VERSION 5.8 ;
BUSBITCHARS "[]" ;
DIVIDERCHAR "/" ;
UNITS
    DATABASE MICRONS 1000 ;
END UNITS

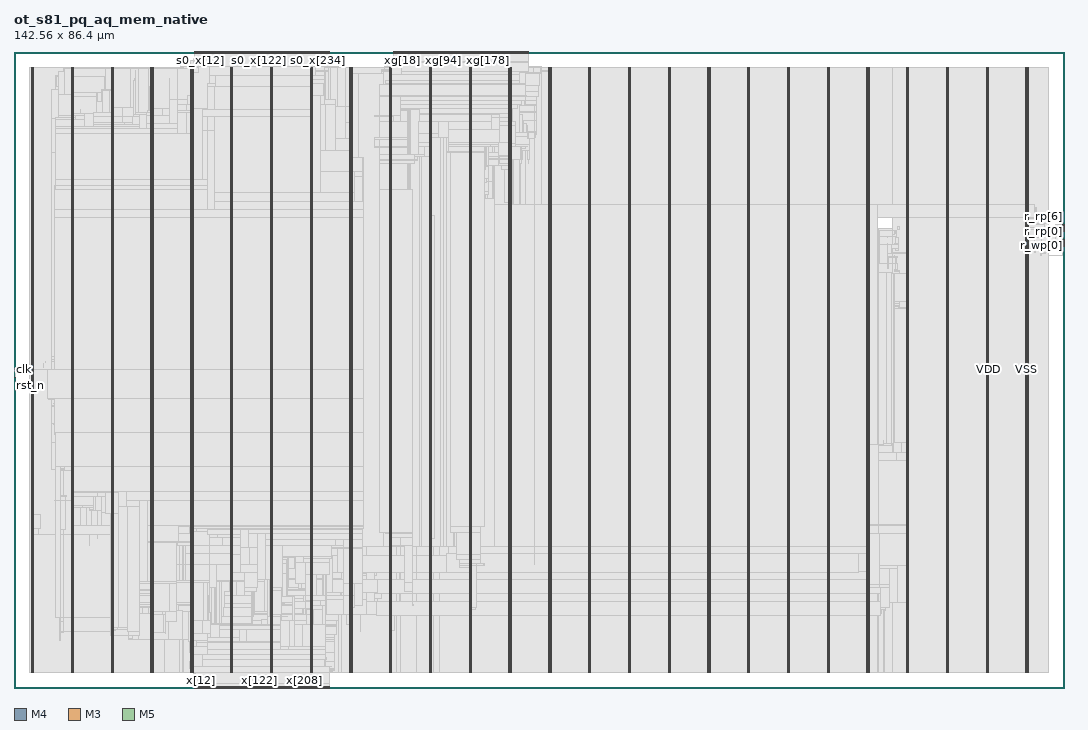
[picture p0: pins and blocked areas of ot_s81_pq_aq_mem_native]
MACRO ot_s81_pq_aq_mem_native
  FOREIGN ot_s81_pq_aq_mem_native 0 0 ;
  CLASS BLOCK ;
  SIZE 142.56 BY 86.4 ;
  PIN clk
    DIRECTION INPUT ;
    USE SIGNAL ;
    PORT
      LAYER M4 ;
        RECT  0 43.2 0.192 43.224 ;
    END
    PORT
      LAYER M4 ;
        RECT  0.156 43.2 0.205 43.224 ;
    END
  END clk
  PIN r_rp[0]
    DIRECTION OUTPUT ;
    USE SIGNAL ;
    PORT
      LAYER M4 ;
        RECT  142.368 62.016 142.56 62.04 ;
    END
  END r_rp[0]
  PIN r_rp[1]
    DIRECTION OUTPUT ;
    USE SIGNAL ;
    PORT
      LAYER M4 ;
        RECT  142.368 62.16 142.56 62.184 ;
    END
  END r_rp[1]
  PIN r_rp[2]
    DIRECTION OUTPUT ;
    USE SIGNAL ;
    PORT
      LAYER M4 ;
        RECT  142.368 62.304 142.56 62.328 ;
    END
  END r_rp[2]
  PIN r_rp[3]
    DIRECTION OUTPUT ;
    USE SIGNAL ;
    PORT
      LAYER M4 ;
        RECT  142.368 62.448 142.56 62.472 ;
    END
  END r_rp[3]
  PIN r_rp[4]
    DIRECTION OUTPUT ;
    USE SIGNAL ;
    PORT
      LAYER M4 ;
        RECT  142.368 62.592 142.56 62.616 ;
    END
  END r_rp[4]
  PIN r_rp[5]
    DIRECTION OUTPUT ;
    USE SIGNAL ;
    PORT
      LAYER M4 ;
        RECT  142.368 62.736 142.56 62.76 ;
    END
  END r_rp[5]
  PIN r_rp[6]
    DIRECTION OUTPUT ;
    USE SIGNAL ;
    PORT
      LAYER M4 ;
        RECT  142.368 62.88 142.56 62.904 ;
    END
  END r_rp[6]
  PIN r_wp[0]
    DIRECTION OUTPUT ;
    USE SIGNAL ;
    PORT
      LAYER M4 ;
        RECT  142.368 60 142.56 60.024 ;
    END
  END r_wp[0]
  PIN r_wp[1]
    DIRECTION OUTPUT ;
    USE SIGNAL ;
    PORT
      LAYER M4 ;
        RECT  142.368 60.144 142.56 60.168 ;
    END
  END r_wp[1]
  PIN r_wp[2]
    DIRECTION OUTPUT ;
    USE SIGNAL ;
    PORT
      LAYER M4 ;
        RECT  142.368 60.288 142.56 60.312 ;
    END
  END r_wp[2]
  PIN r_wp[3]
    DIRECTION OUTPUT ;
    USE SIGNAL ;
    PORT
      LAYER M4 ;
        RECT  142.368 60.432 142.56 60.456 ;
    END
  END r_wp[3]
  PIN r_wp[4]
    DIRECTION OUTPUT ;
    USE SIGNAL ;
    PORT
      LAYER M4 ;
        RECT  142.368 60.576 142.56 60.6 ;
    END
  END r_wp[4]
  PIN r_wp[5]
    DIRECTION OUTPUT ;
    USE SIGNAL ;
    PORT
      LAYER M4 ;
        RECT  142.368 60.72 142.56 60.744 ;
    END
  END r_wp[5]
  PIN r_wp[6]
    DIRECTION OUTPUT ;
    USE SIGNAL ;
    PORT
      LAYER M4 ;
        RECT  142.368 60.864 142.56 60.888 ;
    END
  END r_wp[6]
  PIN rst_n
    DIRECTION INPUT ;
    USE SIGNAL ;
    PORT
      LAYER M4 ;
        RECT  0 42.192 0.192 42.216 ;
    END
    PORT
      LAYER M4 ;
        RECT  0.156 42.192 0.245 42.216 ;
    END
  END rst_n
  PIN s0_x[0]
    DIRECTION OUTPUT ;
    USE SIGNAL ;
    PORT
      LAYER M3 ;
        RECT  24.48 86.256 24.498 86.4 ;
    END
  END s0_x[0]
  PIN s0_x[100]
    DIRECTION OUTPUT ;
    USE SIGNAL ;
    PORT
      LAYER M3 ;
        RECT  31.68 86.256 31.698 86.4 ;
    END
  END s0_x[100]
  PIN s0_x[101]
    DIRECTION OUTPUT ;
    USE SIGNAL ;
    PORT
      LAYER M5 ;
        RECT  31.728 86.208 31.752 86.4 ;
    END
  END s0_x[101]
  PIN s0_x[102]
    DIRECTION OUTPUT ;
    USE SIGNAL ;
    PORT
      LAYER M3 ;
        RECT  31.824 86.256 31.842 86.4 ;
    END
  END s0_x[102]
  PIN s0_x[103]
    DIRECTION OUTPUT ;
    USE SIGNAL ;
    PORT
      LAYER M5 ;
        RECT  31.872 86.208 31.896 86.4 ;
    END
  END s0_x[103]
  PIN s0_x[104]
    DIRECTION OUTPUT ;
    USE SIGNAL ;
    PORT
      LAYER M3 ;
        RECT  31.968 86.256 31.986 86.4 ;
    END
  END s0_x[104]
  PIN s0_x[105]
    DIRECTION OUTPUT ;
    USE SIGNAL ;
    PORT
      LAYER M5 ;
        RECT  32.016 86.208 32.04 86.4 ;
    END
  END s0_x[105]
  PIN s0_x[106]
    DIRECTION OUTPUT ;
    USE SIGNAL ;
    PORT
      LAYER M3 ;
        RECT  32.112 86.256 32.13 86.4 ;
    END
  END s0_x[106]
  PIN s0_x[107]
    DIRECTION OUTPUT ;
    USE SIGNAL ;
    PORT
      LAYER M5 ;
        RECT  32.16 86.208 32.184 86.4 ;
    END
  END s0_x[107]
  PIN s0_x[108]
    DIRECTION OUTPUT ;
    USE SIGNAL ;
    PORT
      LAYER M3 ;
        RECT  32.256 86.256 32.274 86.4 ;
    END
  END s0_x[108]
  PIN s0_x[109]
    DIRECTION OUTPUT ;
    USE SIGNAL ;
    PORT
      LAYER M5 ;
        RECT  32.304 86.208 32.328 86.4 ;
    END
  END s0_x[109]
  PIN s0_x[10]
    DIRECTION OUTPUT ;
    USE SIGNAL ;
    PORT
      LAYER M3 ;
        RECT  25.2 86.256 25.218 86.4 ;
    END
  END s0_x[10]
  PIN s0_x[110]
    DIRECTION OUTPUT ;
    USE SIGNAL ;
    PORT
      LAYER M3 ;
        RECT  32.4 86.256 32.418 86.4 ;
    END
  END s0_x[110]
  PIN s0_x[111]
    DIRECTION OUTPUT ;
    USE SIGNAL ;
    PORT
      LAYER M5 ;
        RECT  32.448 86.208 32.472 86.4 ;
    END
  END s0_x[111]
  PIN s0_x[112]
    DIRECTION OUTPUT ;
    USE SIGNAL ;
    PORT
      LAYER M3 ;
        RECT  32.544 86.256 32.562 86.4 ;
    END
  END s0_x[112]
  PIN s0_x[113]
    DIRECTION OUTPUT ;
    USE SIGNAL ;
    PORT
      LAYER M5 ;
        RECT  32.592 86.208 32.616 86.4 ;
    END
  END s0_x[113]
  PIN s0_x[114]
    DIRECTION OUTPUT ;
    USE SIGNAL ;
    PORT
      LAYER M3 ;
        RECT  32.688 86.256 32.706 86.4 ;
    END
  END s0_x[114]
  PIN s0_x[115]
    DIRECTION OUTPUT ;
    USE SIGNAL ;
    PORT
      LAYER M5 ;
        RECT  32.736 86.208 32.76 86.4 ;
    END
  END s0_x[115]
  PIN s0_x[116]
    DIRECTION OUTPUT ;
    USE SIGNAL ;
    PORT
      LAYER M3 ;
        RECT  32.832 86.256 32.85 86.4 ;
    END
  END s0_x[116]
  PIN s0_x[117]
    DIRECTION OUTPUT ;
    USE SIGNAL ;
    PORT
      LAYER M5 ;
        RECT  32.88 86.208 32.904 86.4 ;
    END
  END s0_x[117]
  PIN s0_x[118]
    DIRECTION OUTPUT ;
    USE SIGNAL ;
    PORT
      LAYER M3 ;
        RECT  32.976 86.256 32.994 86.4 ;
    END
  END s0_x[118]
  PIN s0_x[119]
    DIRECTION OUTPUT ;
    USE SIGNAL ;
    PORT
      LAYER M5 ;
        RECT  33.024 86.208 33.048 86.4 ;
    END
  END s0_x[119]
  PIN s0_x[11]
    DIRECTION OUTPUT ;
    USE SIGNAL ;
    PORT
      LAYER M5 ;
        RECT  25.248 86.208 25.272 86.4 ;
    END
  END s0_x[11]
  PIN s0_x[120]
    DIRECTION OUTPUT ;
    USE SIGNAL ;
    PORT
      LAYER M3 ;
        RECT  33.12 86.256 33.138 86.4 ;
    END
  END s0_x[120]
  PIN s0_x[121]
    DIRECTION OUTPUT ;
    USE SIGNAL ;
    PORT
      LAYER M5 ;
        RECT  33.168 86.208 33.192 86.4 ;
    END
  END s0_x[121]
  PIN s0_x[122]
    DIRECTION OUTPUT ;
    USE SIGNAL ;
    PORT
      LAYER M3 ;
        RECT  33.264 86.256 33.282 86.4 ;
    END
  END s0_x[122]
  PIN s0_x[123]
    DIRECTION OUTPUT ;
    USE SIGNAL ;
    PORT
      LAYER M5 ;
        RECT  33.312 86.208 33.336 86.4 ;
    END
  END s0_x[123]
  PIN s0_x[124]
    DIRECTION OUTPUT ;
    USE SIGNAL ;
    PORT
      LAYER M3 ;
        RECT  33.408 86.256 33.426 86.4 ;
    END
  END s0_x[124]
  PIN s0_x[125]
    DIRECTION OUTPUT ;
    USE SIGNAL ;
    PORT
      LAYER M5 ;
        RECT  33.456 86.208 33.48 86.4 ;
    END
  END s0_x[125]
  PIN s0_x[126]
    DIRECTION OUTPUT ;
    USE SIGNAL ;
    PORT
      LAYER M3 ;
        RECT  33.552 86.256 33.57 86.4 ;
    END
  END s0_x[126]
  PIN s0_x[127]
    DIRECTION OUTPUT ;
    USE SIGNAL ;
    PORT
      LAYER M5 ;
        RECT  33.6 86.208 33.624 86.4 ;
    END
  END s0_x[127]
  PIN s0_x[128]
    DIRECTION OUTPUT ;
    USE SIGNAL ;
    PORT
      LAYER M3 ;
        RECT  33.696 86.256 33.714 86.4 ;
    END
  END s0_x[128]
  PIN s0_x[129]
    DIRECTION OUTPUT ;
    USE SIGNAL ;
    PORT
      LAYER M5 ;
        RECT  33.744 86.208 33.768 86.4 ;
    END
  END s0_x[129]
  PIN s0_x[12]
    DIRECTION OUTPUT ;
    USE SIGNAL ;
    PORT
      LAYER M3 ;
        RECT  25.344 86.256 25.362 86.4 ;
    END
  END s0_x[12]
  PIN s0_x[130]
    DIRECTION OUTPUT ;
    USE SIGNAL ;
    PORT
      LAYER M3 ;
        RECT  33.84 86.256 33.858 86.4 ;
    END
  END s0_x[130]
  PIN s0_x[131]
    DIRECTION OUTPUT ;
    USE SIGNAL ;
    PORT
      LAYER M5 ;
        RECT  33.888 86.208 33.912 86.4 ;
    END
  END s0_x[131]
  PIN s0_x[132]
    DIRECTION OUTPUT ;
    USE SIGNAL ;
    PORT
      LAYER M3 ;
        RECT  33.984 86.256 34.002 86.4 ;
    END
  END s0_x[132]
  PIN s0_x[133]
    DIRECTION OUTPUT ;
    USE SIGNAL ;
    PORT
      LAYER M5 ;
        RECT  34.032 86.208 34.056 86.4 ;
    END
  END s0_x[133]
  PIN s0_x[134]
    DIRECTION OUTPUT ;
    USE SIGNAL ;
    PORT
      LAYER M3 ;
        RECT  34.128 86.256 34.146 86.4 ;
    END
  END s0_x[134]
  PIN s0_x[135]
    DIRECTION OUTPUT ;
    USE SIGNAL ;
    PORT
      LAYER M5 ;
        RECT  34.176 86.208 34.2 86.4 ;
    END
  END s0_x[135]
  PIN s0_x[136]
    DIRECTION OUTPUT ;
    USE SIGNAL ;
    PORT
      LAYER M3 ;
        RECT  34.272 86.256 34.29 86.4 ;
    END
  END s0_x[136]
  PIN s0_x[137]
    DIRECTION OUTPUT ;
    USE SIGNAL ;
    PORT
      LAYER M5 ;
        RECT  34.32 86.208 34.344 86.4 ;
    END
  END s0_x[137]
  PIN s0_x[138]
    DIRECTION OUTPUT ;
    USE SIGNAL ;
    PORT
      LAYER M3 ;
        RECT  34.416 86.256 34.434 86.4 ;
    END
  END s0_x[138]
  PIN s0_x[139]
    DIRECTION OUTPUT ;
    USE SIGNAL ;
    PORT
      LAYER M5 ;
        RECT  34.464 86.208 34.488 86.4 ;
    END
  END s0_x[139]
  PIN s0_x[13]
    DIRECTION OUTPUT ;
    USE SIGNAL ;
    PORT
      LAYER M5 ;
        RECT  25.392 86.208 25.416 86.4 ;
    END
  END s0_x[13]
  PIN s0_x[140]
    DIRECTION OUTPUT ;
    USE SIGNAL ;
    PORT
      LAYER M3 ;
        RECT  34.56 86.256 34.578 86.4 ;
    END
  END s0_x[140]
  PIN s0_x[141]
    DIRECTION OUTPUT ;
    USE SIGNAL ;
    PORT
      LAYER M5 ;
        RECT  34.608 86.208 34.632 86.4 ;
    END
  END s0_x[141]
  PIN s0_x[142]
    DIRECTION OUTPUT ;
    USE SIGNAL ;
    PORT
      LAYER M3 ;
        RECT  34.704 86.256 34.722 86.4 ;
    END
  END s0_x[142]
  PIN s0_x[143]
    DIRECTION OUTPUT ;
    USE SIGNAL ;
    PORT
      LAYER M5 ;
        RECT  34.752 86.208 34.776 86.4 ;
    END
  END s0_x[143]
  PIN s0_x[144]
    DIRECTION OUTPUT ;
    USE SIGNAL ;
    PORT
      LAYER M3 ;
        RECT  34.848 86.256 34.866 86.4 ;
    END
  END s0_x[144]
  PIN s0_x[145]
    DIRECTION OUTPUT ;
    USE SIGNAL ;
    PORT
      LAYER M5 ;
        RECT  34.896 86.208 34.92 86.4 ;
    END
  END s0_x[145]
  PIN s0_x[146]
    DIRECTION OUTPUT ;
    USE SIGNAL ;
    PORT
      LAYER M3 ;
        RECT  34.992 86.256 35.01 86.4 ;
    END
  END s0_x[146]
  PIN s0_x[147]
    DIRECTION OUTPUT ;
    USE SIGNAL ;
    PORT
      LAYER M5 ;
        RECT  35.04 86.208 35.064 86.4 ;
    END
  END s0_x[147]
  PIN s0_x[148]
    DIRECTION OUTPUT ;
    USE SIGNAL ;
    PORT
      LAYER M3 ;
        RECT  35.136 86.256 35.154 86.4 ;
    END
  END s0_x[148]
  PIN s0_x[149]
    DIRECTION OUTPUT ;
    USE SIGNAL ;
    PORT
      LAYER M5 ;
        RECT  35.184 86.208 35.208 86.4 ;
    END
  END s0_x[149]
  PIN s0_x[14]
    DIRECTION OUTPUT ;
    USE SIGNAL ;
    PORT
      LAYER M3 ;
        RECT  25.488 86.256 25.506 86.4 ;
    END
  END s0_x[14]
  PIN s0_x[150]
    DIRECTION OUTPUT ;
    USE SIGNAL ;
    PORT
      LAYER M3 ;
        RECT  35.28 86.256 35.298 86.4 ;
    END
  END s0_x[150]
  PIN s0_x[151]
    DIRECTION OUTPUT ;
    USE SIGNAL ;
    PORT
      LAYER M5 ;
        RECT  35.328 86.208 35.352 86.4 ;
    END
  END s0_x[151]
  PIN s0_x[152]
    DIRECTION OUTPUT ;
    USE SIGNAL ;
    PORT
      LAYER M3 ;
        RECT  35.424 86.256 35.442 86.4 ;
    END
  END s0_x[152]
  PIN s0_x[153]
    DIRECTION OUTPUT ;
    USE SIGNAL ;
    PORT
      LAYER M5 ;
        RECT  35.472 86.208 35.496 86.4 ;
    END
  END s0_x[153]
  PIN s0_x[154]
    DIRECTION OUTPUT ;
    USE SIGNAL ;
    PORT
      LAYER M3 ;
        RECT  35.568 86.256 35.586 86.4 ;
    END
  END s0_x[154]
  PIN s0_x[155]
    DIRECTION OUTPUT ;
    USE SIGNAL ;
    PORT
      LAYER M5 ;
        RECT  35.616 86.208 35.64 86.4 ;
    END
  END s0_x[155]
  PIN s0_x[156]
    DIRECTION OUTPUT ;
    USE SIGNAL ;
    PORT
      LAYER M3 ;
        RECT  35.712 86.256 35.73 86.4 ;
    END
  END s0_x[156]
  PIN s0_x[157]
    DIRECTION OUTPUT ;
    USE SIGNAL ;
    PORT
      LAYER M5 ;
        RECT  35.76 86.208 35.784 86.4 ;
    END
  END s0_x[157]
  PIN s0_x[158]
    DIRECTION OUTPUT ;
    USE SIGNAL ;
    PORT
      LAYER M3 ;
        RECT  35.856 86.256 35.874 86.4 ;
    END
  END s0_x[158]
  PIN s0_x[159]
    DIRECTION OUTPUT ;
    USE SIGNAL ;
    PORT
      LAYER M5 ;
        RECT  35.904 86.208 35.928 86.4 ;
    END
  END s0_x[159]
  PIN s0_x[15]
    DIRECTION OUTPUT ;
    USE SIGNAL ;
    PORT
      LAYER M5 ;
        RECT  25.536 86.208 25.56 86.4 ;
    END
  END s0_x[15]
  PIN s0_x[160]
    DIRECTION OUTPUT ;
    USE SIGNAL ;
    PORT
      LAYER M3 ;
        RECT  36 86.256 36.018 86.4 ;
    END
  END s0_x[160]
  PIN s0_x[161]
    DIRECTION OUTPUT ;
    USE SIGNAL ;
    PORT
      LAYER M5 ;
        RECT  36.048 86.208 36.072 86.4 ;
    END
  END s0_x[161]
  PIN s0_x[162]
    DIRECTION OUTPUT ;
    USE SIGNAL ;
    PORT
      LAYER M3 ;
        RECT  36.144 86.256 36.162 86.4 ;
    END
  END s0_x[162]
  PIN s0_x[163]
    DIRECTION OUTPUT ;
    USE SIGNAL ;
    PORT
      LAYER M5 ;
        RECT  36.192 86.208 36.216 86.4 ;
    END
  END s0_x[163]
  PIN s0_x[164]
    DIRECTION OUTPUT ;
    USE SIGNAL ;
    PORT
      LAYER M3 ;
        RECT  36.288 86.256 36.306 86.4 ;
    END
  END s0_x[164]
  PIN s0_x[165]
    DIRECTION OUTPUT ;
    USE SIGNAL ;
    PORT
      LAYER M5 ;
        RECT  36.336 86.208 36.36 86.4 ;
    END
  END s0_x[165]
  PIN s0_x[166]
    DIRECTION OUTPUT ;
    USE SIGNAL ;
    PORT
      LAYER M3 ;
        RECT  36.432 86.256 36.45 86.4 ;
    END
  END s0_x[166]
  PIN s0_x[167]
    DIRECTION OUTPUT ;
    USE SIGNAL ;
    PORT
      LAYER M5 ;
        RECT  36.48 86.208 36.504 86.4 ;
    END
  END s0_x[167]
  PIN s0_x[168]
    DIRECTION OUTPUT ;
    USE SIGNAL ;
    PORT
      LAYER M3 ;
        RECT  36.576 86.256 36.594 86.4 ;
    END
  END s0_x[168]
  PIN s0_x[169]
    DIRECTION OUTPUT ;
    USE SIGNAL ;
    PORT
      LAYER M5 ;
        RECT  36.624 86.208 36.648 86.4 ;
    END
  END s0_x[169]
  PIN s0_x[16]
    DIRECTION OUTPUT ;
    USE SIGNAL ;
    PORT
      LAYER M3 ;
        RECT  25.632 86.256 25.65 86.4 ;
    END
  END s0_x[16]
  PIN s0_x[170]
    DIRECTION OUTPUT ;
    USE SIGNAL ;
    PORT
      LAYER M3 ;
        RECT  36.72 86.256 36.738 86.4 ;
    END
  END s0_x[170]
  PIN s0_x[171]
    DIRECTION OUTPUT ;
    USE SIGNAL ;
    PORT
      LAYER M5 ;
        RECT  36.768 86.208 36.792 86.4 ;
    END
  END s0_x[171]
  PIN s0_x[172]
    DIRECTION OUTPUT ;
    USE SIGNAL ;
    PORT
      LAYER M3 ;
        RECT  36.864 86.256 36.882 86.4 ;
    END
  END s0_x[172]
  PIN s0_x[173]
    DIRECTION OUTPUT ;
    USE SIGNAL ;
    PORT
      LAYER M5 ;
        RECT  36.912 86.208 36.936 86.4 ;
    END
  END s0_x[173]
  PIN s0_x[174]
    DIRECTION OUTPUT ;
    USE SIGNAL ;
    PORT
      LAYER M3 ;
        RECT  37.008 86.256 37.026 86.4 ;
    END
  END s0_x[174]
  PIN s0_x[175]
    DIRECTION OUTPUT ;
    USE SIGNAL ;
    PORT
      LAYER M5 ;
        RECT  37.056 86.208 37.08 86.4 ;
    END
  END s0_x[175]
  PIN s0_x[176]
    DIRECTION OUTPUT ;
    USE SIGNAL ;
    PORT
      LAYER M3 ;
        RECT  37.152 86.256 37.17 86.4 ;
    END
  END s0_x[176]
  PIN s0_x[177]
    DIRECTION OUTPUT ;
    USE SIGNAL ;
    PORT
      LAYER M5 ;
        RECT  37.2 86.208 37.224 86.4 ;
    END
  END s0_x[177]
  PIN s0_x[178]
    DIRECTION OUTPUT ;
    USE SIGNAL ;
    PORT
      LAYER M3 ;
        RECT  37.296 86.256 37.314 86.4 ;
    END
  END s0_x[178]
  PIN s0_x[179]
    DIRECTION OUTPUT ;
    USE SIGNAL ;
    PORT
      LAYER M5 ;
        RECT  37.344 86.208 37.368 86.4 ;
    END
  END s0_x[179]
  PIN s0_x[17]
    DIRECTION OUTPUT ;
    USE SIGNAL ;
    PORT
      LAYER M5 ;
        RECT  25.68 86.208 25.704 86.4 ;
    END
  END s0_x[17]
  PIN s0_x[180]
    DIRECTION OUTPUT ;
    USE SIGNAL ;
    PORT
      LAYER M3 ;
        RECT  37.44 86.256 37.458 86.4 ;
    END
  END s0_x[180]
  PIN s0_x[181]
    DIRECTION OUTPUT ;
    USE SIGNAL ;
    PORT
      LAYER M5 ;
        RECT  37.488 86.208 37.512 86.4 ;
    END
  END s0_x[181]
  PIN s0_x[182]
    DIRECTION OUTPUT ;
    USE SIGNAL ;
    PORT
      LAYER M3 ;
        RECT  37.584 86.256 37.602 86.4 ;
    END
  END s0_x[182]
  PIN s0_x[183]
    DIRECTION OUTPUT ;
    USE SIGNAL ;
    PORT
      LAYER M5 ;
        RECT  37.632 86.208 37.656 86.4 ;
    END
  END s0_x[183]
  PIN s0_x[184]
    DIRECTION OUTPUT ;
    USE SIGNAL ;
    PORT
      LAYER M3 ;
        RECT  37.728 86.256 37.746 86.4 ;
    END
  END s0_x[184]
  PIN s0_x[185]
    DIRECTION OUTPUT ;
    USE SIGNAL ;
    PORT
      LAYER M5 ;
        RECT  37.776 86.208 37.8 86.4 ;
    END
  END s0_x[185]
  PIN s0_x[186]
    DIRECTION OUTPUT ;
    USE SIGNAL ;
    PORT
      LAYER M3 ;
        RECT  37.872 86.256 37.89 86.4 ;
    END
  END s0_x[186]
  PIN s0_x[187]
    DIRECTION OUTPUT ;
    USE SIGNAL ;
    PORT
      LAYER M5 ;
        RECT  37.92 86.208 37.944 86.4 ;
    END
  END s0_x[187]
  PIN s0_x[188]
    DIRECTION OUTPUT ;
    USE SIGNAL ;
    PORT
      LAYER M3 ;
        RECT  38.016 86.256 38.034 86.4 ;
    END
  END s0_x[188]
  PIN s0_x[189]
    DIRECTION OUTPUT ;
    USE SIGNAL ;
    PORT
      LAYER M5 ;
        RECT  38.064 86.208 38.088 86.4 ;
    END
  END s0_x[189]
  PIN s0_x[18]
    DIRECTION OUTPUT ;
    USE SIGNAL ;
    PORT
      LAYER M3 ;
        RECT  25.776 86.256 25.794 86.4 ;
    END
  END s0_x[18]
  PIN s0_x[190]
    DIRECTION OUTPUT ;
    USE SIGNAL ;
    PORT
      LAYER M3 ;
        RECT  38.16 86.256 38.178 86.4 ;
    END
  END s0_x[190]
  PIN s0_x[191]
    DIRECTION OUTPUT ;
    USE SIGNAL ;
    PORT
      LAYER M5 ;
        RECT  38.208 86.208 38.232 86.4 ;
    END
  END s0_x[191]
  PIN s0_x[192]
    DIRECTION OUTPUT ;
    USE SIGNAL ;
    PORT
      LAYER M3 ;
        RECT  38.304 86.256 38.322 86.4 ;
    END
  END s0_x[192]
  PIN s0_x[193]
    DIRECTION OUTPUT ;
    USE SIGNAL ;
    PORT
      LAYER M5 ;
        RECT  38.352 86.208 38.376 86.4 ;
    END
  END s0_x[193]
  PIN s0_x[194]
    DIRECTION OUTPUT ;
    USE SIGNAL ;
    PORT
      LAYER M3 ;
        RECT  38.448 86.256 38.466 86.4 ;
    END
  END s0_x[194]
  PIN s0_x[195]
    DIRECTION OUTPUT ;
    USE SIGNAL ;
    PORT
      LAYER M5 ;
        RECT  38.496 86.208 38.52 86.4 ;
    END
  END s0_x[195]
  PIN s0_x[196]
    DIRECTION OUTPUT ;
    USE SIGNAL ;
    PORT
      LAYER M3 ;
        RECT  38.592 86.256 38.61 86.4 ;
    END
  END s0_x[196]
  PIN s0_x[197]
    DIRECTION OUTPUT ;
    USE SIGNAL ;
    PORT
      LAYER M5 ;
        RECT  38.64 86.208 38.664 86.4 ;
    END
  END s0_x[197]
  PIN s0_x[198]
    DIRECTION OUTPUT ;
    USE SIGNAL ;
    PORT
      LAYER M3 ;
        RECT  38.736 86.256 38.754 86.4 ;
    END
  END s0_x[198]
  PIN s0_x[199]
    DIRECTION OUTPUT ;
    USE SIGNAL ;
    PORT
      LAYER M5 ;
        RECT  38.784 86.208 38.808 86.4 ;
    END
  END s0_x[199]
  PIN s0_x[19]
    DIRECTION OUTPUT ;
    USE SIGNAL ;
    PORT
      LAYER M5 ;
        RECT  25.824 86.208 25.848 86.4 ;
    END
  END s0_x[19]
  PIN s0_x[1]
    DIRECTION OUTPUT ;
    USE SIGNAL ;
    PORT
      LAYER M5 ;
        RECT  24.528 86.208 24.552 86.4 ;
    END
  END s0_x[1]
  PIN s0_x[200]
    DIRECTION OUTPUT ;
    USE SIGNAL ;
    PORT
      LAYER M3 ;
        RECT  38.88 86.256 38.898 86.4 ;
    END
  END s0_x[200]
  PIN s0_x[201]
    DIRECTION OUTPUT ;
    USE SIGNAL ;
    PORT
      LAYER M5 ;
        RECT  38.928 86.208 38.952 86.4 ;
    END
  END s0_x[201]
  PIN s0_x[202]
    DIRECTION OUTPUT ;
    USE SIGNAL ;
    PORT
      LAYER M3 ;
        RECT  39.024 86.256 39.042 86.4 ;
    END
  END s0_x[202]
  PIN s0_x[203]
    DIRECTION OUTPUT ;
    USE SIGNAL ;
    PORT
      LAYER M5 ;
        RECT  39.072 86.208 39.096 86.4 ;
    END
  END s0_x[203]
  PIN s0_x[204]
    DIRECTION OUTPUT ;
    USE SIGNAL ;
    PORT
      LAYER M3 ;
        RECT  39.168 86.256 39.186 86.4 ;
    END
  END s0_x[204]
  PIN s0_x[205]
    DIRECTION OUTPUT ;
    USE SIGNAL ;
    PORT
      LAYER M5 ;
        RECT  39.216 86.208 39.24 86.4 ;
    END
  END s0_x[205]
  PIN s0_x[206]
    DIRECTION OUTPUT ;
    USE SIGNAL ;
    PORT
      LAYER M3 ;
        RECT  39.312 86.256 39.33 86.4 ;
    END
  END s0_x[206]
  PIN s0_x[207]
    DIRECTION OUTPUT ;
    USE SIGNAL ;
    PORT
      LAYER M5 ;
        RECT  39.36 86.208 39.384 86.4 ;
    END
  END s0_x[207]
  PIN s0_x[208]
    DIRECTION OUTPUT ;
    USE SIGNAL ;
    PORT
      LAYER M3 ;
        RECT  39.456 86.256 39.474 86.4 ;
    END
  END s0_x[208]
  PIN s0_x[209]
    DIRECTION OUTPUT ;
    USE SIGNAL ;
    PORT
      LAYER M5 ;
        RECT  39.504 86.208 39.528 86.4 ;
    END
  END s0_x[209]
  PIN s0_x[20]
    DIRECTION OUTPUT ;
    USE SIGNAL ;
    PORT
      LAYER M3 ;
        RECT  25.92 86.256 25.938 86.4 ;
    END
  END s0_x[20]
  PIN s0_x[210]
    DIRECTION OUTPUT ;
    USE SIGNAL ;
    PORT
      LAYER M3 ;
        RECT  39.6 86.256 39.618 86.4 ;
    END
  END s0_x[210]
  PIN s0_x[211]
    DIRECTION OUTPUT ;
    USE SIGNAL ;
    PORT
      LAYER M5 ;
        RECT  39.648 86.208 39.672 86.4 ;
    END
  END s0_x[211]
  PIN s0_x[212]
    DIRECTION OUTPUT ;
    USE SIGNAL ;
    PORT
      LAYER M3 ;
        RECT  39.744 86.256 39.762 86.4 ;
    END
  END s0_x[212]
  PIN s0_x[213]
    DIRECTION OUTPUT ;
    USE SIGNAL ;
    PORT
      LAYER M5 ;
        RECT  39.792 86.208 39.816 86.4 ;
    END
  END s0_x[213]
  PIN s0_x[214]
    DIRECTION OUTPUT ;
    USE SIGNAL ;
    PORT
      LAYER M3 ;
        RECT  39.888 86.256 39.906 86.4 ;
    END
  END s0_x[214]
  PIN s0_x[215]
    DIRECTION OUTPUT ;
    USE SIGNAL ;
    PORT
      LAYER M5 ;
        RECT  39.936 86.208 39.96 86.4 ;
    END
  END s0_x[215]
  PIN s0_x[216]
    DIRECTION OUTPUT ;
    USE SIGNAL ;
    PORT
      LAYER M3 ;
        RECT  40.032 86.256 40.05 86.4 ;
    END
  END s0_x[216]
  PIN s0_x[217]
    DIRECTION OUTPUT ;
    USE SIGNAL ;
    PORT
      LAYER M5 ;
        RECT  40.08 86.208 40.104 86.4 ;
    END
  END s0_x[217]
  PIN s0_x[218]
    DIRECTION OUTPUT ;
    USE SIGNAL ;
    PORT
      LAYER M3 ;
        RECT  40.176 86.256 40.194 86.4 ;
    END
  END s0_x[218]
  PIN s0_x[219]
    DIRECTION OUTPUT ;
    USE SIGNAL ;
    PORT
      LAYER M5 ;
        RECT  40.224 86.208 40.248 86.4 ;
    END
  END s0_x[219]
  PIN s0_x[21]
    DIRECTION OUTPUT ;
    USE SIGNAL ;
    PORT
      LAYER M5 ;
        RECT  25.968 86.208 25.992 86.4 ;
    END
  END s0_x[21]
  PIN s0_x[220]
    DIRECTION OUTPUT ;
    USE SIGNAL ;
    PORT
      LAYER M3 ;
        RECT  40.32 86.256 40.338 86.4 ;
    END
  END s0_x[220]
  PIN s0_x[221]
    DIRECTION OUTPUT ;
    USE SIGNAL ;
    PORT
      LAYER M5 ;
        RECT  40.368 86.208 40.392 86.4 ;
    END
  END s0_x[221]
  PIN s0_x[222]
    DIRECTION OUTPUT ;
    USE SIGNAL ;
    PORT
      LAYER M3 ;
        RECT  40.464 86.256 40.482 86.4 ;
    END
  END s0_x[222]
  PIN s0_x[223]
    DIRECTION OUTPUT ;
    USE SIGNAL ;
    PORT
      LAYER M5 ;
        RECT  40.512 86.208 40.536 86.4 ;
    END
  END s0_x[223]
  PIN s0_x[224]
    DIRECTION OUTPUT ;
    USE SIGNAL ;
    PORT
      LAYER M3 ;
        RECT  40.608 86.256 40.626 86.4 ;
    END
  END s0_x[224]
  PIN s0_x[225]
    DIRECTION OUTPUT ;
    USE SIGNAL ;
    PORT
      LAYER M5 ;
        RECT  40.656 86.208 40.68 86.4 ;
    END
  END s0_x[225]
  PIN s0_x[226]
    DIRECTION OUTPUT ;
    USE SIGNAL ;
    PORT
      LAYER M3 ;
        RECT  40.752 86.256 40.77 86.4 ;
    END
  END s0_x[226]
  PIN s0_x[227]
    DIRECTION OUTPUT ;
    USE SIGNAL ;
    PORT
      LAYER M5 ;
        RECT  40.8 86.208 40.824 86.4 ;
    END
  END s0_x[227]
  PIN s0_x[228]
    DIRECTION OUTPUT ;
    USE SIGNAL ;
    PORT
      LAYER M3 ;
        RECT  40.896 86.256 40.914 86.4 ;
    END
  END s0_x[228]
  PIN s0_x[229]
    DIRECTION OUTPUT ;
    USE SIGNAL ;
    PORT
      LAYER M5 ;
        RECT  40.944 86.208 40.968 86.4 ;
    END
  END s0_x[229]
  PIN s0_x[22]
    DIRECTION OUTPUT ;
    USE SIGNAL ;
    PORT
      LAYER M3 ;
        RECT  26.064 86.256 26.082 86.4 ;
    END
  END s0_x[22]
  PIN s0_x[230]
    DIRECTION OUTPUT ;
    USE SIGNAL ;
    PORT
      LAYER M3 ;
        RECT  41.04 86.256 41.058 86.4 ;
    END
  END s0_x[230]
  PIN s0_x[231]
    DIRECTION OUTPUT ;
    USE SIGNAL ;
    PORT
      LAYER M5 ;
        RECT  41.088 86.208 41.112 86.4 ;
    END
  END s0_x[231]
  PIN s0_x[232]
    DIRECTION OUTPUT ;
    USE SIGNAL ;
    PORT
      LAYER M3 ;
        RECT  41.184 86.256 41.202 86.4 ;
    END
  END s0_x[232]
  PIN s0_x[233]
    DIRECTION OUTPUT ;
    USE SIGNAL ;
    PORT
      LAYER M5 ;
        RECT  41.232 86.208 41.256 86.4 ;
    END
  END s0_x[233]
  PIN s0_x[234]
    DIRECTION OUTPUT ;
    USE SIGNAL ;
    PORT
      LAYER M3 ;
        RECT  41.328 86.256 41.346 86.4 ;
    END
  END s0_x[234]
  PIN s0_x[235]
    DIRECTION OUTPUT ;
    USE SIGNAL ;
    PORT
      LAYER M5 ;
        RECT  41.376 86.208 41.4 86.4 ;
    END
  END s0_x[235]
  PIN s0_x[236]
    DIRECTION OUTPUT ;
    USE SIGNAL ;
    PORT
      LAYER M3 ;
        RECT  41.472 86.256 41.49 86.4 ;
    END
  END s0_x[236]
  PIN s0_x[237]
    DIRECTION OUTPUT ;
    USE SIGNAL ;
    PORT
      LAYER M5 ;
        RECT  41.52 86.208 41.544 86.4 ;
    END
  END s0_x[237]
  PIN s0_x[238]
    DIRECTION OUTPUT ;
    USE SIGNAL ;
    PORT
      LAYER M3 ;
        RECT  41.616 86.256 41.634 86.4 ;
    END
  END s0_x[238]
  PIN s0_x[239]
    DIRECTION OUTPUT ;
    USE SIGNAL ;
    PORT
      LAYER M5 ;
        RECT  41.664 86.208 41.688 86.4 ;
    END
  END s0_x[239]
  PIN s0_x[23]
    DIRECTION OUTPUT ;
    USE SIGNAL ;
    PORT
      LAYER M5 ;
        RECT  26.112 86.208 26.136 86.4 ;
    END
  END s0_x[23]
  PIN s0_x[240]
    DIRECTION OUTPUT ;
    USE SIGNAL ;
    PORT
      LAYER M3 ;
        RECT  41.76 86.256 41.778 86.4 ;
    END
  END s0_x[240]
  PIN s0_x[241]
    DIRECTION OUTPUT ;
    USE SIGNAL ;
    PORT
      LAYER M5 ;
        RECT  41.808 86.208 41.832 86.4 ;
    END
  END s0_x[241]
  PIN s0_x[242]
    DIRECTION OUTPUT ;
    USE SIGNAL ;
    PORT
      LAYER M3 ;
        RECT  41.904 86.256 41.922 86.4 ;
    END
  END s0_x[242]
  PIN s0_x[243]
    DIRECTION OUTPUT ;
    USE SIGNAL ;
    PORT
      LAYER M5 ;
        RECT  41.952 86.208 41.976 86.4 ;
    END
  END s0_x[243]
  PIN s0_x[244]
    DIRECTION OUTPUT ;
    USE SIGNAL ;
    PORT
      LAYER M3 ;
        RECT  42.048 86.256 42.066 86.4 ;
    END
  END s0_x[244]
  PIN s0_x[245]
    DIRECTION OUTPUT ;
    USE SIGNAL ;
    PORT
      LAYER M5 ;
        RECT  42.096 86.208 42.12 86.4 ;
    END
  END s0_x[245]
  PIN s0_x[246]
    DIRECTION OUTPUT ;
    USE SIGNAL ;
    PORT
      LAYER M3 ;
        RECT  42.192 86.256 42.21 86.4 ;
    END
  END s0_x[246]
  PIN s0_x[247]
    DIRECTION OUTPUT ;
    USE SIGNAL ;
    PORT
      LAYER M5 ;
        RECT  42.24 86.208 42.264 86.4 ;
    END
  END s0_x[247]
  PIN s0_x[248]
    DIRECTION OUTPUT ;
    USE SIGNAL ;
    PORT
      LAYER M3 ;
        RECT  42.336 86.256 42.354 86.4 ;
    END
  END s0_x[248]
  PIN s0_x[249]
    DIRECTION OUTPUT ;
    USE SIGNAL ;
    PORT
      LAYER M5 ;
        RECT  42.384 86.208 42.408 86.4 ;
    END
  END s0_x[249]
  PIN s0_x[24]
    DIRECTION OUTPUT ;
    USE SIGNAL ;
    PORT
      LAYER M3 ;
        RECT  26.208 86.256 26.226 86.4 ;
    END
  END s0_x[24]
  PIN s0_x[250]
    DIRECTION OUTPUT ;
    USE SIGNAL ;
    PORT
      LAYER M3 ;
        RECT  42.48 86.256 42.498 86.4 ;
    END
  END s0_x[250]
  PIN s0_x[251]
    DIRECTION OUTPUT ;
    USE SIGNAL ;
    PORT
      LAYER M5 ;
        RECT  42.528 86.208 42.552 86.4 ;
    END
  END s0_x[251]
  PIN s0_x[252]
    DIRECTION OUTPUT ;
    USE SIGNAL ;
    PORT
      LAYER M3 ;
        RECT  42.624 86.256 42.642 86.4 ;
    END
  END s0_x[252]
  PIN s0_x[253]
    DIRECTION OUTPUT ;
    USE SIGNAL ;
    PORT
      LAYER M5 ;
        RECT  42.672 86.208 42.696 86.4 ;
    END
  END s0_x[253]
  PIN s0_x[254]
    DIRECTION OUTPUT ;
    USE SIGNAL ;
    PORT
      LAYER M3 ;
        RECT  42.768 86.256 42.786 86.4 ;
    END
  END s0_x[254]
  PIN s0_x[255]
    DIRECTION OUTPUT ;
    USE SIGNAL ;
    PORT
      LAYER M5 ;
        RECT  42.816 86.208 42.84 86.4 ;
    END
  END s0_x[255]
  PIN s0_x[25]
    DIRECTION OUTPUT ;
    USE SIGNAL ;
    PORT
      LAYER M5 ;
        RECT  26.256 86.208 26.28 86.4 ;
    END
  END s0_x[25]
  PIN s0_x[26]
    DIRECTION OUTPUT ;
    USE SIGNAL ;
    PORT
      LAYER M3 ;
        RECT  26.352 86.256 26.37 86.4 ;
    END
  END s0_x[26]
  PIN s0_x[27]
    DIRECTION OUTPUT ;
    USE SIGNAL ;
    PORT
      LAYER M5 ;
        RECT  26.4 86.208 26.424 86.4 ;
    END
  END s0_x[27]
  PIN s0_x[28]
    DIRECTION OUTPUT ;
    USE SIGNAL ;
    PORT
      LAYER M3 ;
        RECT  26.496 86.256 26.514 86.4 ;
    END
  END s0_x[28]
  PIN s0_x[29]
    DIRECTION OUTPUT ;
    USE SIGNAL ;
    PORT
      LAYER M5 ;
        RECT  26.544 86.208 26.568 86.4 ;
    END
  END s0_x[29]
  PIN s0_x[2]
    DIRECTION OUTPUT ;
    USE SIGNAL ;
    PORT
      LAYER M3 ;
        RECT  24.624 86.256 24.642 86.4 ;
    END
  END s0_x[2]
  PIN s0_x[30]
    DIRECTION OUTPUT ;
    USE SIGNAL ;
    PORT
      LAYER M3 ;
        RECT  26.64 86.256 26.658 86.4 ;
    END
  END s0_x[30]
  PIN s0_x[31]
    DIRECTION OUTPUT ;
    USE SIGNAL ;
    PORT
      LAYER M5 ;
        RECT  26.688 86.208 26.712 86.4 ;
    END
  END s0_x[31]
  PIN s0_x[32]
    DIRECTION OUTPUT ;
    USE SIGNAL ;
    PORT
      LAYER M3 ;
        RECT  26.784 86.256 26.802 86.4 ;
    END
  END s0_x[32]
  PIN s0_x[33]
    DIRECTION OUTPUT ;
    USE SIGNAL ;
    PORT
      LAYER M5 ;
        RECT  26.832 86.208 26.856 86.4 ;
    END
  END s0_x[33]
  PIN s0_x[34]
    DIRECTION OUTPUT ;
    USE SIGNAL ;
    PORT
      LAYER M3 ;
        RECT  26.928 86.256 26.946 86.4 ;
    END
  END s0_x[34]
  PIN s0_x[35]
    DIRECTION OUTPUT ;
    USE SIGNAL ;
    PORT
      LAYER M5 ;
        RECT  26.976 86.208 27 86.4 ;
    END
  END s0_x[35]
  PIN s0_x[36]
    DIRECTION OUTPUT ;
    USE SIGNAL ;
    PORT
      LAYER M3 ;
        RECT  27.072 86.256 27.09 86.4 ;
    END
  END s0_x[36]
  PIN s0_x[37]
    DIRECTION OUTPUT ;
    USE SIGNAL ;
    PORT
      LAYER M5 ;
        RECT  27.12 86.208 27.144 86.4 ;
    END
  END s0_x[37]
  PIN s0_x[38]
    DIRECTION OUTPUT ;
    USE SIGNAL ;
    PORT
      LAYER M3 ;
        RECT  27.216 86.256 27.234 86.4 ;
    END
  END s0_x[38]
  PIN s0_x[39]
    DIRECTION OUTPUT ;
    USE SIGNAL ;
    PORT
      LAYER M5 ;
        RECT  27.264 86.208 27.288 86.4 ;
    END
  END s0_x[39]
  PIN s0_x[3]
    DIRECTION OUTPUT ;
    USE SIGNAL ;
    PORT
      LAYER M5 ;
        RECT  24.672 86.208 24.696 86.4 ;
    END
  END s0_x[3]
  PIN s0_x[40]
    DIRECTION OUTPUT ;
    USE SIGNAL ;
    PORT
      LAYER M3 ;
        RECT  27.36 86.256 27.378 86.4 ;
    END
  END s0_x[40]
  PIN s0_x[41]
    DIRECTION OUTPUT ;
    USE SIGNAL ;
    PORT
      LAYER M5 ;
        RECT  27.408 86.208 27.432 86.4 ;
    END
  END s0_x[41]
  PIN s0_x[42]
    DIRECTION OUTPUT ;
    USE SIGNAL ;
    PORT
      LAYER M3 ;
        RECT  27.504 86.256 27.522 86.4 ;
    END
  END s0_x[42]
  PIN s0_x[43]
    DIRECTION OUTPUT ;
    USE SIGNAL ;
    PORT
      LAYER M5 ;
        RECT  27.552 86.208 27.576 86.4 ;
    END
  END s0_x[43]
  PIN s0_x[44]
    DIRECTION OUTPUT ;
    USE SIGNAL ;
    PORT
      LAYER M3 ;
        RECT  27.648 86.256 27.666 86.4 ;
    END
  END s0_x[44]
  PIN s0_x[45]
    DIRECTION OUTPUT ;
    USE SIGNAL ;
    PORT
      LAYER M5 ;
        RECT  27.696 86.208 27.72 86.4 ;
    END
  END s0_x[45]
  PIN s0_x[46]
    DIRECTION OUTPUT ;
    USE SIGNAL ;
    PORT
      LAYER M3 ;
        RECT  27.792 86.256 27.81 86.4 ;
    END
  END s0_x[46]
  PIN s0_x[47]
    DIRECTION OUTPUT ;
    USE SIGNAL ;
    PORT
      LAYER M5 ;
        RECT  27.84 86.208 27.864 86.4 ;
    END
  END s0_x[47]
  PIN s0_x[48]
    DIRECTION OUTPUT ;
    USE SIGNAL ;
    PORT
      LAYER M3 ;
        RECT  27.936 86.256 27.954 86.4 ;
    END
  END s0_x[48]
  PIN s0_x[49]
    DIRECTION OUTPUT ;
    USE SIGNAL ;
    PORT
      LAYER M5 ;
        RECT  27.984 86.208 28.008 86.4 ;
    END
  END s0_x[49]
  PIN s0_x[4]
    DIRECTION OUTPUT ;
    USE SIGNAL ;
    PORT
      LAYER M3 ;
        RECT  24.768 86.256 24.786 86.4 ;
    END
  END s0_x[4]
  PIN s0_x[50]
    DIRECTION OUTPUT ;
    USE SIGNAL ;
    PORT
      LAYER M3 ;
        RECT  28.08 86.256 28.098 86.4 ;
    END
  END s0_x[50]
  PIN s0_x[51]
    DIRECTION OUTPUT ;
    USE SIGNAL ;
    PORT
      LAYER M5 ;
        RECT  28.128 86.208 28.152 86.4 ;
    END
  END s0_x[51]
  PIN s0_x[52]
    DIRECTION OUTPUT ;
    USE SIGNAL ;
    PORT
      LAYER M3 ;
        RECT  28.224 86.256 28.242 86.4 ;
    END
  END s0_x[52]
  PIN s0_x[53]
    DIRECTION OUTPUT ;
    USE SIGNAL ;
    PORT
      LAYER M5 ;
        RECT  28.272 86.208 28.296 86.4 ;
    END
  END s0_x[53]
  PIN s0_x[54]
    DIRECTION OUTPUT ;
    USE SIGNAL ;
    PORT
      LAYER M3 ;
        RECT  28.368 86.256 28.386 86.4 ;
    END
  END s0_x[54]
  PIN s0_x[55]
    DIRECTION OUTPUT ;
    USE SIGNAL ;
    PORT
      LAYER M5 ;
        RECT  28.416 86.208 28.44 86.4 ;
    END
  END s0_x[55]
  PIN s0_x[56]
    DIRECTION OUTPUT ;
    USE SIGNAL ;
    PORT
      LAYER M3 ;
        RECT  28.512 86.256 28.53 86.4 ;
    END
  END s0_x[56]
  PIN s0_x[57]
    DIRECTION OUTPUT ;
    USE SIGNAL ;
    PORT
      LAYER M5 ;
        RECT  28.56 86.208 28.584 86.4 ;
    END
  END s0_x[57]
  PIN s0_x[58]
    DIRECTION OUTPUT ;
    USE SIGNAL ;
    PORT
      LAYER M3 ;
        RECT  28.656 86.256 28.674 86.4 ;
    END
  END s0_x[58]
  PIN s0_x[59]
    DIRECTION OUTPUT ;
    USE SIGNAL ;
    PORT
      LAYER M5 ;
        RECT  28.704 86.208 28.728 86.4 ;
    END
  END s0_x[59]
  PIN s0_x[5]
    DIRECTION OUTPUT ;
    USE SIGNAL ;
    PORT
      LAYER M5 ;
        RECT  24.816 86.208 24.84 86.4 ;
    END
  END s0_x[5]
  PIN s0_x[60]
    DIRECTION OUTPUT ;
    USE SIGNAL ;
    PORT
      LAYER M3 ;
        RECT  28.8 86.256 28.818 86.4 ;
    END
  END s0_x[60]
  PIN s0_x[61]
    DIRECTION OUTPUT ;
    USE SIGNAL ;
    PORT
      LAYER M5 ;
        RECT  28.848 86.208 28.872 86.4 ;
    END
  END s0_x[61]
  PIN s0_x[62]
    DIRECTION OUTPUT ;
    USE SIGNAL ;
    PORT
      LAYER M3 ;
        RECT  28.944 86.256 28.962 86.4 ;
    END
  END s0_x[62]
  PIN s0_x[63]
    DIRECTION OUTPUT ;
    USE SIGNAL ;
    PORT
      LAYER M5 ;
        RECT  28.992 86.208 29.016 86.4 ;
    END
  END s0_x[63]
  PIN s0_x[64]
    DIRECTION OUTPUT ;
    USE SIGNAL ;
    PORT
      LAYER M3 ;
        RECT  29.088 86.256 29.106 86.4 ;
    END
  END s0_x[64]
  PIN s0_x[65]
    DIRECTION OUTPUT ;
    USE SIGNAL ;
    PORT
      LAYER M5 ;
        RECT  29.136 86.208 29.16 86.4 ;
    END
  END s0_x[65]
  PIN s0_x[66]
    DIRECTION OUTPUT ;
    USE SIGNAL ;
    PORT
      LAYER M3 ;
        RECT  29.232 86.256 29.25 86.4 ;
    END
  END s0_x[66]
  PIN s0_x[67]
    DIRECTION OUTPUT ;
    USE SIGNAL ;
    PORT
      LAYER M5 ;
        RECT  29.28 86.208 29.304 86.4 ;
    END
  END s0_x[67]
  PIN s0_x[68]
    DIRECTION OUTPUT ;
    USE SIGNAL ;
    PORT
      LAYER M3 ;
        RECT  29.376 86.256 29.394 86.4 ;
    END
  END s0_x[68]
  PIN s0_x[69]
    DIRECTION OUTPUT ;
    USE SIGNAL ;
    PORT
      LAYER M5 ;
        RECT  29.424 86.208 29.448 86.4 ;
    END
  END s0_x[69]
  PIN s0_x[6]
    DIRECTION OUTPUT ;
    USE SIGNAL ;
    PORT
      LAYER M3 ;
        RECT  24.912 86.256 24.93 86.4 ;
    END
  END s0_x[6]
  PIN s0_x[70]
    DIRECTION OUTPUT ;
    USE SIGNAL ;
    PORT
      LAYER M3 ;
        RECT  29.52 86.256 29.538 86.4 ;
    END
  END s0_x[70]
  PIN s0_x[71]
    DIRECTION OUTPUT ;
    USE SIGNAL ;
    PORT
      LAYER M5 ;
        RECT  29.568 86.208 29.592 86.4 ;
    END
  END s0_x[71]
  PIN s0_x[72]
    DIRECTION OUTPUT ;
    USE SIGNAL ;
    PORT
      LAYER M3 ;
        RECT  29.664 86.256 29.682 86.4 ;
    END
  END s0_x[72]
  PIN s0_x[73]
    DIRECTION OUTPUT ;
    USE SIGNAL ;
    PORT
      LAYER M5 ;
        RECT  29.712 86.208 29.736 86.4 ;
    END
  END s0_x[73]
  PIN s0_x[74]
    DIRECTION OUTPUT ;
    USE SIGNAL ;
    PORT
      LAYER M3 ;
        RECT  29.808 86.256 29.826 86.4 ;
    END
  END s0_x[74]
  PIN s0_x[75]
    DIRECTION OUTPUT ;
    USE SIGNAL ;
    PORT
      LAYER M5 ;
        RECT  29.856 86.208 29.88 86.4 ;
    END
  END s0_x[75]
  PIN s0_x[76]
    DIRECTION OUTPUT ;
    USE SIGNAL ;
    PORT
      LAYER M3 ;
        RECT  29.952 86.256 29.97 86.4 ;
    END
  END s0_x[76]
  PIN s0_x[77]
    DIRECTION OUTPUT ;
    USE SIGNAL ;
    PORT
      LAYER M5 ;
        RECT  30 86.208 30.024 86.4 ;
    END
  END s0_x[77]
  PIN s0_x[78]
    DIRECTION OUTPUT ;
    USE SIGNAL ;
    PORT
      LAYER M3 ;
        RECT  30.096 86.256 30.114 86.4 ;
    END
  END s0_x[78]
  PIN s0_x[79]
    DIRECTION OUTPUT ;
    USE SIGNAL ;
    PORT
      LAYER M5 ;
        RECT  30.144 86.208 30.168 86.4 ;
    END
  END s0_x[79]
  PIN s0_x[7]
    DIRECTION OUTPUT ;
    USE SIGNAL ;
    PORT
      LAYER M5 ;
        RECT  24.96 86.208 24.984 86.4 ;
    END
  END s0_x[7]
  PIN s0_x[80]
    DIRECTION OUTPUT ;
    USE SIGNAL ;
    PORT
      LAYER M3 ;
        RECT  30.24 86.256 30.258 86.4 ;
    END
  END s0_x[80]
  PIN s0_x[81]
    DIRECTION OUTPUT ;
    USE SIGNAL ;
    PORT
      LAYER M5 ;
        RECT  30.288 86.208 30.312 86.4 ;
    END
  END s0_x[81]
  PIN s0_x[82]
    DIRECTION OUTPUT ;
    USE SIGNAL ;
    PORT
      LAYER M3 ;
        RECT  30.384 86.256 30.402 86.4 ;
    END
  END s0_x[82]
  PIN s0_x[83]
    DIRECTION OUTPUT ;
    USE SIGNAL ;
    PORT
      LAYER M5 ;
        RECT  30.432 86.208 30.456 86.4 ;
    END
  END s0_x[83]
  PIN s0_x[84]
    DIRECTION OUTPUT ;
    USE SIGNAL ;
    PORT
      LAYER M3 ;
        RECT  30.528 86.256 30.546 86.4 ;
    END
  END s0_x[84]
  PIN s0_x[85]
    DIRECTION OUTPUT ;
    USE SIGNAL ;
    PORT
      LAYER M5 ;
        RECT  30.576 86.208 30.6 86.4 ;
    END
  END s0_x[85]
  PIN s0_x[86]
    DIRECTION OUTPUT ;
    USE SIGNAL ;
    PORT
      LAYER M3 ;
        RECT  30.672 86.256 30.69 86.4 ;
    END
  END s0_x[86]
  PIN s0_x[87]
    DIRECTION OUTPUT ;
    USE SIGNAL ;
    PORT
      LAYER M5 ;
        RECT  30.72 86.208 30.744 86.4 ;
    END
  END s0_x[87]
  PIN s0_x[88]
    DIRECTION OUTPUT ;
    USE SIGNAL ;
    PORT
      LAYER M3 ;
        RECT  30.816 86.256 30.834 86.4 ;
    END
  END s0_x[88]
  PIN s0_x[89]
    DIRECTION OUTPUT ;
    USE SIGNAL ;
    PORT
      LAYER M5 ;
        RECT  30.864 86.208 30.888 86.4 ;
    END
  END s0_x[89]
  PIN s0_x[8]
    DIRECTION OUTPUT ;
    USE SIGNAL ;
    PORT
      LAYER M3 ;
        RECT  25.056 86.256 25.074 86.4 ;
    END
  END s0_x[8]
  PIN s0_x[90]
    DIRECTION OUTPUT ;
    USE SIGNAL ;
    PORT
      LAYER M3 ;
        RECT  30.96 86.256 30.978 86.4 ;
    END
  END s0_x[90]
  PIN s0_x[91]
    DIRECTION OUTPUT ;
    USE SIGNAL ;
    PORT
      LAYER M5 ;
        RECT  31.008 86.208 31.032 86.4 ;
    END
  END s0_x[91]
  PIN s0_x[92]
    DIRECTION OUTPUT ;
    USE SIGNAL ;
    PORT
      LAYER M3 ;
        RECT  31.104 86.256 31.122 86.4 ;
    END
  END s0_x[92]
  PIN s0_x[93]
    DIRECTION OUTPUT ;
    USE SIGNAL ;
    PORT
      LAYER M5 ;
        RECT  31.152 86.208 31.176 86.4 ;
    END
  END s0_x[93]
  PIN s0_x[94]
    DIRECTION OUTPUT ;
    USE SIGNAL ;
    PORT
      LAYER M3 ;
        RECT  31.248 86.256 31.266 86.4 ;
    END
  END s0_x[94]
  PIN s0_x[95]
    DIRECTION OUTPUT ;
    USE SIGNAL ;
    PORT
      LAYER M5 ;
        RECT  31.296 86.208 31.32 86.4 ;
    END
  END s0_x[95]
  PIN s0_x[96]
    DIRECTION OUTPUT ;
    USE SIGNAL ;
    PORT
      LAYER M3 ;
        RECT  31.392 86.256 31.41 86.4 ;
    END
  END s0_x[96]
  PIN s0_x[97]
    DIRECTION OUTPUT ;
    USE SIGNAL ;
    PORT
      LAYER M5 ;
        RECT  31.44 86.208 31.464 86.4 ;
    END
  END s0_x[97]
  PIN s0_x[98]
    DIRECTION OUTPUT ;
    USE SIGNAL ;
    PORT
      LAYER M3 ;
        RECT  31.536 86.256 31.554 86.4 ;
    END
  END s0_x[98]
  PIN s0_x[99]
    DIRECTION OUTPUT ;
    USE SIGNAL ;
    PORT
      LAYER M5 ;
        RECT  31.584 86.208 31.608 86.4 ;
    END
  END s0_x[99]
  PIN s0_x[9]
    DIRECTION OUTPUT ;
    USE SIGNAL ;
    PORT
      LAYER M5 ;
        RECT  25.104 86.208 25.128 86.4 ;
    END
  END s0_x[9]
  PIN x[0]
    DIRECTION INPUT ;
    USE SIGNAL ;
    PORT
      LAYER M3 ;
        RECT  24.48 0 24.498 0.144 ;
    END
  END x[0]
  PIN x[100]
    DIRECTION INPUT ;
    USE SIGNAL ;
    PORT
      LAYER M3 ;
        RECT  31.68 0 31.698 0.144 ;
    END
  END x[100]
  PIN x[101]
    DIRECTION INPUT ;
    USE SIGNAL ;
    PORT
      LAYER M5 ;
        RECT  31.728 0 31.752 0.192 ;
    END
  END x[101]
  PIN x[102]
    DIRECTION INPUT ;
    USE SIGNAL ;
    PORT
      LAYER M3 ;
        RECT  31.824 0 31.842 0.144 ;
    END
  END x[102]
  PIN x[103]
    DIRECTION INPUT ;
    USE SIGNAL ;
    PORT
      LAYER M5 ;
        RECT  31.872 0 31.896 0.192 ;
    END
  END x[103]
  PIN x[104]
    DIRECTION INPUT ;
    USE SIGNAL ;
    PORT
      LAYER M3 ;
        RECT  31.968 0 31.986 0.144 ;
    END
  END x[104]
  PIN x[105]
    DIRECTION INPUT ;
    USE SIGNAL ;
    PORT
      LAYER M5 ;
        RECT  32.016 0 32.04 0.192 ;
    END
  END x[105]
  PIN x[106]
    DIRECTION INPUT ;
    USE SIGNAL ;
    PORT
      LAYER M3 ;
        RECT  32.112 0 32.13 0.144 ;
    END
  END x[106]
  PIN x[107]
    DIRECTION INPUT ;
    USE SIGNAL ;
    PORT
      LAYER M5 ;
        RECT  32.16 0 32.184 0.192 ;
    END
  END x[107]
  PIN x[108]
    DIRECTION INPUT ;
    USE SIGNAL ;
    PORT
      LAYER M3 ;
        RECT  32.256 0 32.274 0.144 ;
    END
  END x[108]
  PIN x[109]
    DIRECTION INPUT ;
    USE SIGNAL ;
    PORT
      LAYER M5 ;
        RECT  32.304 0 32.328 0.192 ;
    END
  END x[109]
  PIN x[10]
    DIRECTION INPUT ;
    USE SIGNAL ;
    PORT
      LAYER M3 ;
        RECT  25.2 0 25.218 0.144 ;
    END
  END x[10]
  PIN x[110]
    DIRECTION INPUT ;
    USE SIGNAL ;
    PORT
      LAYER M3 ;
        RECT  32.4 0 32.418 0.144 ;
    END
  END x[110]
  PIN x[111]
    DIRECTION INPUT ;
    USE SIGNAL ;
    PORT
      LAYER M5 ;
        RECT  32.448 0 32.472 0.192 ;
    END
  END x[111]
  PIN x[112]
    DIRECTION INPUT ;
    USE SIGNAL ;
    PORT
      LAYER M3 ;
        RECT  32.544 0 32.562 0.144 ;
    END
  END x[112]
  PIN x[113]
    DIRECTION INPUT ;
    USE SIGNAL ;
    PORT
      LAYER M5 ;
        RECT  32.592 0 32.616 0.192 ;
    END
  END x[113]
  PIN x[114]
    DIRECTION INPUT ;
    USE SIGNAL ;
    PORT
      LAYER M3 ;
        RECT  32.688 0 32.706 0.144 ;
    END
  END x[114]
  PIN x[115]
    DIRECTION INPUT ;
    USE SIGNAL ;
    PORT
      LAYER M5 ;
        RECT  32.736 0 32.76 0.192 ;
    END
  END x[115]
  PIN x[116]
    DIRECTION INPUT ;
    USE SIGNAL ;
    PORT
      LAYER M3 ;
        RECT  32.832 0 32.85 0.144 ;
    END
  END x[116]
  PIN x[117]
    DIRECTION INPUT ;
    USE SIGNAL ;
    PORT
      LAYER M5 ;
        RECT  32.88 0 32.904 0.192 ;
    END
  END x[117]
  PIN x[118]
    DIRECTION INPUT ;
    USE SIGNAL ;
    PORT
      LAYER M3 ;
        RECT  32.976 0 32.994 0.144 ;
    END
  END x[118]
  PIN x[119]
    DIRECTION INPUT ;
    USE SIGNAL ;
    PORT
      LAYER M5 ;
        RECT  33.024 0 33.048 0.192 ;
    END
  END x[119]
  PIN x[11]
    DIRECTION INPUT ;
    USE SIGNAL ;
    PORT
      LAYER M5 ;
        RECT  25.248 0 25.272 0.192 ;
    END
  END x[11]
  PIN x[120]
    DIRECTION INPUT ;
    USE SIGNAL ;
    PORT
      LAYER M3 ;
        RECT  33.12 0 33.138 0.144 ;
    END
  END x[120]
  PIN x[121]
    DIRECTION INPUT ;
    USE SIGNAL ;
    PORT
      LAYER M5 ;
        RECT  33.168 0 33.192 0.192 ;
    END
  END x[121]
  PIN x[122]
    DIRECTION INPUT ;
    USE SIGNAL ;
    PORT
      LAYER M3 ;
        RECT  33.264 0 33.282 0.144 ;
    END
  END x[122]
  PIN x[123]
    DIRECTION INPUT ;
    USE SIGNAL ;
    PORT
      LAYER M5 ;
        RECT  33.312 0 33.336 0.192 ;
    END
  END x[123]
  PIN x[124]
    DIRECTION INPUT ;
    USE SIGNAL ;
    PORT
      LAYER M3 ;
        RECT  33.408 0 33.426 0.144 ;
    END
  END x[124]
  PIN x[125]
    DIRECTION INPUT ;
    USE SIGNAL ;
    PORT
      LAYER M5 ;
        RECT  33.456 0 33.48 0.192 ;
    END
  END x[125]
  PIN x[126]
    DIRECTION INPUT ;
    USE SIGNAL ;
    PORT
      LAYER M3 ;
        RECT  33.552 0 33.57 0.144 ;
    END
  END x[126]
  PIN x[127]
    DIRECTION INPUT ;
    USE SIGNAL ;
    PORT
      LAYER M5 ;
        RECT  33.6 0 33.624 0.192 ;
    END
  END x[127]
  PIN x[128]
    DIRECTION INPUT ;
    USE SIGNAL ;
    PORT
      LAYER M3 ;
        RECT  33.696 0 33.714 0.144 ;
    END
  END x[128]
  PIN x[129]
    DIRECTION INPUT ;
    USE SIGNAL ;
    PORT
      LAYER M5 ;
        RECT  33.744 0 33.768 0.192 ;
    END
  END x[129]
  PIN x[12]
    DIRECTION INPUT ;
    USE SIGNAL ;
    PORT
      LAYER M3 ;
        RECT  25.344 0 25.362 0.144 ;
    END
  END x[12]
  PIN x[130]
    DIRECTION INPUT ;
    USE SIGNAL ;
    PORT
      LAYER M3 ;
        RECT  33.84 0 33.858 0.144 ;
    END
  END x[130]
  PIN x[131]
    DIRECTION INPUT ;
    USE SIGNAL ;
    PORT
      LAYER M5 ;
        RECT  33.888 0 33.912 0.192 ;
    END
  END x[131]
  PIN x[132]
    DIRECTION INPUT ;
    USE SIGNAL ;
    PORT
      LAYER M3 ;
        RECT  33.984 0 34.002 0.144 ;
    END
  END x[132]
  PIN x[133]
    DIRECTION INPUT ;
    USE SIGNAL ;
    PORT
      LAYER M5 ;
        RECT  34.032 0 34.056 0.192 ;
    END
  END x[133]
  PIN x[134]
    DIRECTION INPUT ;
    USE SIGNAL ;
    PORT
      LAYER M3 ;
        RECT  34.128 0 34.146 0.144 ;
    END
  END x[134]
  PIN x[135]
    DIRECTION INPUT ;
    USE SIGNAL ;
    PORT
      LAYER M5 ;
        RECT  34.176 0 34.2 0.192 ;
    END
  END x[135]
  PIN x[136]
    DIRECTION INPUT ;
    USE SIGNAL ;
    PORT
      LAYER M3 ;
        RECT  34.272 0 34.29 0.144 ;
    END
  END x[136]
  PIN x[137]
    DIRECTION INPUT ;
    USE SIGNAL ;
    PORT
      LAYER M5 ;
        RECT  34.32 0 34.344 0.192 ;
    END
  END x[137]
  PIN x[138]
    DIRECTION INPUT ;
    USE SIGNAL ;
    PORT
      LAYER M3 ;
        RECT  34.416 0 34.434 0.144 ;
    END
  END x[138]
  PIN x[139]
    DIRECTION INPUT ;
    USE SIGNAL ;
    PORT
      LAYER M5 ;
        RECT  34.464 0 34.488 0.192 ;
    END
  END x[139]
  PIN x[13]
    DIRECTION INPUT ;
    USE SIGNAL ;
    PORT
      LAYER M5 ;
        RECT  25.392 0 25.416 0.192 ;
    END
  END x[13]
  PIN x[140]
    DIRECTION INPUT ;
    USE SIGNAL ;
    PORT
      LAYER M3 ;
        RECT  34.56 0 34.578 0.144 ;
    END
  END x[140]
  PIN x[141]
    DIRECTION INPUT ;
    USE SIGNAL ;
    PORT
      LAYER M5 ;
        RECT  34.608 0 34.632 0.192 ;
    END
  END x[141]
  PIN x[142]
    DIRECTION INPUT ;
    USE SIGNAL ;
    PORT
      LAYER M3 ;
        RECT  34.704 0 34.722 0.144 ;
    END
  END x[142]
  PIN x[143]
    DIRECTION INPUT ;
    USE SIGNAL ;
    PORT
      LAYER M5 ;
        RECT  34.752 0 34.776 0.192 ;
    END
  END x[143]
  PIN x[144]
    DIRECTION INPUT ;
    USE SIGNAL ;
    PORT
      LAYER M3 ;
        RECT  34.848 0 34.866 0.144 ;
    END
  END x[144]
  PIN x[145]
    DIRECTION INPUT ;
    USE SIGNAL ;
    PORT
      LAYER M5 ;
        RECT  34.896 0 34.92 0.192 ;
    END
  END x[145]
  PIN x[146]
    DIRECTION INPUT ;
    USE SIGNAL ;
    PORT
      LAYER M3 ;
        RECT  34.992 0 35.01 0.144 ;
    END
  END x[146]
  PIN x[147]
    DIRECTION INPUT ;
    USE SIGNAL ;
    PORT
      LAYER M5 ;
        RECT  35.04 0 35.064 0.192 ;
    END
  END x[147]
  PIN x[148]
    DIRECTION INPUT ;
    USE SIGNAL ;
    PORT
      LAYER M3 ;
        RECT  35.136 0 35.154 0.144 ;
    END
  END x[148]
  PIN x[149]
    DIRECTION INPUT ;
    USE SIGNAL ;
    PORT
      LAYER M5 ;
        RECT  35.184 0 35.208 0.192 ;
    END
  END x[149]
  PIN x[14]
    DIRECTION INPUT ;
    USE SIGNAL ;
    PORT
      LAYER M3 ;
        RECT  25.488 0 25.506 0.144 ;
    END
  END x[14]
  PIN x[150]
    DIRECTION INPUT ;
    USE SIGNAL ;
    PORT
      LAYER M3 ;
        RECT  35.28 0 35.298 0.144 ;
    END
  END x[150]
  PIN x[151]
    DIRECTION INPUT ;
    USE SIGNAL ;
    PORT
      LAYER M5 ;
        RECT  35.328 0 35.352 0.192 ;
    END
  END x[151]
  PIN x[152]
    DIRECTION INPUT ;
    USE SIGNAL ;
    PORT
      LAYER M3 ;
        RECT  35.424 0 35.442 0.144 ;
    END
  END x[152]
  PIN x[153]
    DIRECTION INPUT ;
    USE SIGNAL ;
    PORT
      LAYER M5 ;
        RECT  35.472 0 35.496 0.192 ;
    END
  END x[153]
  PIN x[154]
    DIRECTION INPUT ;
    USE SIGNAL ;
    PORT
      LAYER M3 ;
        RECT  35.568 0 35.586 0.144 ;
    END
  END x[154]
  PIN x[155]
    DIRECTION INPUT ;
    USE SIGNAL ;
    PORT
      LAYER M5 ;
        RECT  35.616 0 35.64 0.192 ;
    END
  END x[155]
  PIN x[156]
    DIRECTION INPUT ;
    USE SIGNAL ;
    PORT
      LAYER M3 ;
        RECT  35.712 0 35.73 0.144 ;
    END
  END x[156]
  PIN x[157]
    DIRECTION INPUT ;
    USE SIGNAL ;
    PORT
      LAYER M5 ;
        RECT  35.76 0 35.784 0.192 ;
    END
  END x[157]
  PIN x[158]
    DIRECTION INPUT ;
    USE SIGNAL ;
    PORT
      LAYER M3 ;
        RECT  35.856 0 35.874 0.144 ;
    END
  END x[158]
  PIN x[159]
    DIRECTION INPUT ;
    USE SIGNAL ;
    PORT
      LAYER M5 ;
        RECT  35.904 0 35.928 0.192 ;
    END
  END x[159]
  PIN x[15]
    DIRECTION INPUT ;
    USE SIGNAL ;
    PORT
      LAYER M5 ;
        RECT  25.536 0 25.56 0.192 ;
    END
  END x[15]
  PIN x[160]
    DIRECTION INPUT ;
    USE SIGNAL ;
    PORT
      LAYER M3 ;
        RECT  36 0 36.018 0.144 ;
    END
  END x[160]
  PIN x[161]
    DIRECTION INPUT ;
    USE SIGNAL ;
    PORT
      LAYER M5 ;
        RECT  36.048 0 36.072 0.192 ;
    END
  END x[161]
  PIN x[162]
    DIRECTION INPUT ;
    USE SIGNAL ;
    PORT
      LAYER M3 ;
        RECT  36.144 0 36.162 0.144 ;
    END
  END x[162]
  PIN x[163]
    DIRECTION INPUT ;
    USE SIGNAL ;
    PORT
      LAYER M5 ;
        RECT  36.192 0 36.216 0.192 ;
    END
  END x[163]
  PIN x[164]
    DIRECTION INPUT ;
    USE SIGNAL ;
    PORT
      LAYER M3 ;
        RECT  36.288 0 36.306 0.144 ;
    END
  END x[164]
  PIN x[165]
    DIRECTION INPUT ;
    USE SIGNAL ;
    PORT
      LAYER M5 ;
        RECT  36.336 0 36.36 0.192 ;
    END
  END x[165]
  PIN x[166]
    DIRECTION INPUT ;
    USE SIGNAL ;
    PORT
      LAYER M3 ;
        RECT  36.432 0 36.45 0.144 ;
    END
  END x[166]
  PIN x[167]
    DIRECTION INPUT ;
    USE SIGNAL ;
    PORT
      LAYER M5 ;
        RECT  36.48 0 36.504 0.192 ;
    END
  END x[167]
  PIN x[168]
    DIRECTION INPUT ;
    USE SIGNAL ;
    PORT
      LAYER M3 ;
        RECT  36.576 0 36.594 0.144 ;
    END
  END x[168]
  PIN x[169]
    DIRECTION INPUT ;
    USE SIGNAL ;
    PORT
      LAYER M5 ;
        RECT  36.624 0 36.648 0.192 ;
    END
  END x[169]
  PIN x[16]
    DIRECTION INPUT ;
    USE SIGNAL ;
    PORT
      LAYER M3 ;
        RECT  25.632 0 25.65 0.144 ;
    END
  END x[16]
  PIN x[170]
    DIRECTION INPUT ;
    USE SIGNAL ;
    PORT
      LAYER M3 ;
        RECT  36.72 0 36.738 0.144 ;
    END
  END x[170]
  PIN x[171]
    DIRECTION INPUT ;
    USE SIGNAL ;
    PORT
      LAYER M5 ;
        RECT  36.768 0 36.792 0.192 ;
    END
  END x[171]
  PIN x[172]
    DIRECTION INPUT ;
    USE SIGNAL ;
    PORT
      LAYER M3 ;
        RECT  36.864 0 36.882 0.144 ;
    END
  END x[172]
  PIN x[173]
    DIRECTION INPUT ;
    USE SIGNAL ;
    PORT
      LAYER M5 ;
        RECT  36.912 0 36.936 0.192 ;
    END
  END x[173]
  PIN x[174]
    DIRECTION INPUT ;
    USE SIGNAL ;
    PORT
      LAYER M3 ;
        RECT  37.008 0 37.026 0.144 ;
    END
  END x[174]
  PIN x[175]
    DIRECTION INPUT ;
    USE SIGNAL ;
    PORT
      LAYER M5 ;
        RECT  37.056 0 37.08 0.192 ;
    END
  END x[175]
  PIN x[176]
    DIRECTION INPUT ;
    USE SIGNAL ;
    PORT
      LAYER M3 ;
        RECT  37.152 0 37.17 0.144 ;
    END
  END x[176]
  PIN x[177]
    DIRECTION INPUT ;
    USE SIGNAL ;
    PORT
      LAYER M5 ;
        RECT  37.2 0 37.224 0.192 ;
    END
  END x[177]
  PIN x[178]
    DIRECTION INPUT ;
    USE SIGNAL ;
    PORT
      LAYER M3 ;
        RECT  37.296 0 37.314 0.144 ;
    END
  END x[178]
  PIN x[179]
    DIRECTION INPUT ;
    USE SIGNAL ;
    PORT
      LAYER M5 ;
        RECT  37.344 0 37.368 0.192 ;
    END
  END x[179]
  PIN x[17]
    DIRECTION INPUT ;
    USE SIGNAL ;
    PORT
      LAYER M5 ;
        RECT  25.68 0 25.704 0.192 ;
    END
  END x[17]
  PIN x[180]
    DIRECTION INPUT ;
    USE SIGNAL ;
    PORT
      LAYER M3 ;
        RECT  37.44 0 37.458 0.144 ;
    END
  END x[180]
  PIN x[181]
    DIRECTION INPUT ;
    USE SIGNAL ;
    PORT
      LAYER M5 ;
        RECT  37.488 0 37.512 0.192 ;
    END
  END x[181]
  PIN x[182]
    DIRECTION INPUT ;
    USE SIGNAL ;
    PORT
      LAYER M3 ;
        RECT  37.584 0 37.602 0.144 ;
    END
  END x[182]
  PIN x[183]
    DIRECTION INPUT ;
    USE SIGNAL ;
    PORT
      LAYER M5 ;
        RECT  37.632 0 37.656 0.192 ;
    END
  END x[183]
  PIN x[184]
    DIRECTION INPUT ;
    USE SIGNAL ;
    PORT
      LAYER M3 ;
        RECT  37.728 0 37.746 0.144 ;
    END
  END x[184]
  PIN x[185]
    DIRECTION INPUT ;
    USE SIGNAL ;
    PORT
      LAYER M5 ;
        RECT  37.776 0 37.8 0.192 ;
    END
  END x[185]
  PIN x[186]
    DIRECTION INPUT ;
    USE SIGNAL ;
    PORT
      LAYER M3 ;
        RECT  37.872 0 37.89 0.144 ;
    END
  END x[186]
  PIN x[187]
    DIRECTION INPUT ;
    USE SIGNAL ;
    PORT
      LAYER M5 ;
        RECT  37.92 0 37.944 0.192 ;
    END
  END x[187]
  PIN x[188]
    DIRECTION INPUT ;
    USE SIGNAL ;
    PORT
      LAYER M3 ;
        RECT  38.016 0 38.034 0.144 ;
    END
  END x[188]
  PIN x[189]
    DIRECTION INPUT ;
    USE SIGNAL ;
    PORT
      LAYER M5 ;
        RECT  38.064 0 38.088 0.192 ;
    END
  END x[189]
  PIN x[18]
    DIRECTION INPUT ;
    USE SIGNAL ;
    PORT
      LAYER M3 ;
        RECT  25.776 0 25.794 0.144 ;
    END
  END x[18]
  PIN x[190]
    DIRECTION INPUT ;
    USE SIGNAL ;
    PORT
      LAYER M3 ;
        RECT  38.16 0 38.178 0.144 ;
    END
  END x[190]
  PIN x[191]
    DIRECTION INPUT ;
    USE SIGNAL ;
    PORT
      LAYER M5 ;
        RECT  38.208 0 38.232 0.192 ;
    END
  END x[191]
  PIN x[192]
    DIRECTION INPUT ;
    USE SIGNAL ;
    PORT
      LAYER M3 ;
        RECT  38.304 0 38.322 0.144 ;
    END
  END x[192]
  PIN x[193]
    DIRECTION INPUT ;
    USE SIGNAL ;
    PORT
      LAYER M5 ;
        RECT  38.352 0 38.376 0.192 ;
    END
  END x[193]
  PIN x[194]
    DIRECTION INPUT ;
    USE SIGNAL ;
    PORT
      LAYER M3 ;
        RECT  38.448 0 38.466 0.144 ;
    END
  END x[194]
  PIN x[195]
    DIRECTION INPUT ;
    USE SIGNAL ;
    PORT
      LAYER M5 ;
        RECT  38.496 0 38.52 0.192 ;
    END
  END x[195]
  PIN x[196]
    DIRECTION INPUT ;
    USE SIGNAL ;
    PORT
      LAYER M3 ;
        RECT  38.592 0 38.61 0.144 ;
    END
  END x[196]
  PIN x[197]
    DIRECTION INPUT ;
    USE SIGNAL ;
    PORT
      LAYER M5 ;
        RECT  38.64 0 38.664 0.192 ;
    END
  END x[197]
  PIN x[198]
    DIRECTION INPUT ;
    USE SIGNAL ;
    PORT
      LAYER M3 ;
        RECT  38.736 0 38.754 0.144 ;
    END
  END x[198]
  PIN x[199]
    DIRECTION INPUT ;
    USE SIGNAL ;
    PORT
      LAYER M5 ;
        RECT  38.784 0 38.808 0.192 ;
    END
  END x[199]
  PIN x[19]
    DIRECTION INPUT ;
    USE SIGNAL ;
    PORT
      LAYER M5 ;
        RECT  25.824 0 25.848 0.192 ;
    END
  END x[19]
  PIN x[1]
    DIRECTION INPUT ;
    USE SIGNAL ;
    PORT
      LAYER M5 ;
        RECT  24.528 0 24.552 0.192 ;
    END
  END x[1]
  PIN x[200]
    DIRECTION INPUT ;
    USE SIGNAL ;
    PORT
      LAYER M3 ;
        RECT  38.88 0 38.898 0.144 ;
    END
  END x[200]
  PIN x[201]
    DIRECTION INPUT ;
    USE SIGNAL ;
    PORT
      LAYER M5 ;
        RECT  38.928 0 38.952 0.192 ;
    END
  END x[201]
  PIN x[202]
    DIRECTION INPUT ;
    USE SIGNAL ;
    PORT
      LAYER M3 ;
        RECT  39.024 0 39.042 0.144 ;
    END
  END x[202]
  PIN x[203]
    DIRECTION INPUT ;
    USE SIGNAL ;
    PORT
      LAYER M5 ;
        RECT  39.072 0 39.096 0.192 ;
    END
  END x[203]
  PIN x[204]
    DIRECTION INPUT ;
    USE SIGNAL ;
    PORT
      LAYER M3 ;
        RECT  39.168 0 39.186 0.144 ;
    END
  END x[204]
  PIN x[205]
    DIRECTION INPUT ;
    USE SIGNAL ;
    PORT
      LAYER M5 ;
        RECT  39.216 0 39.24 0.192 ;
    END
  END x[205]
  PIN x[206]
    DIRECTION INPUT ;
    USE SIGNAL ;
    PORT
      LAYER M3 ;
        RECT  39.312 0 39.33 0.144 ;
    END
  END x[206]
  PIN x[207]
    DIRECTION INPUT ;
    USE SIGNAL ;
    PORT
      LAYER M5 ;
        RECT  39.36 0 39.384 0.192 ;
    END
  END x[207]
  PIN x[208]
    DIRECTION INPUT ;
    USE SIGNAL ;
    PORT
      LAYER M3 ;
        RECT  39.456 0 39.474 0.144 ;
    END
  END x[208]
  PIN x[209]
    DIRECTION INPUT ;
    USE SIGNAL ;
    PORT
      LAYER M5 ;
        RECT  39.504 0 39.528 0.192 ;
    END
  END x[209]
  PIN x[20]
    DIRECTION INPUT ;
    USE SIGNAL ;
    PORT
      LAYER M3 ;
        RECT  25.92 0 25.938 0.144 ;
    END
  END x[20]
  PIN x[210]
    DIRECTION INPUT ;
    USE SIGNAL ;
    PORT
      LAYER M3 ;
        RECT  39.6 0 39.618 0.144 ;
    END
  END x[210]
  PIN x[211]
    DIRECTION INPUT ;
    USE SIGNAL ;
    PORT
      LAYER M5 ;
        RECT  39.648 0 39.672 0.192 ;
    END
  END x[211]
  PIN x[212]
    DIRECTION INPUT ;
    USE SIGNAL ;
    PORT
      LAYER M3 ;
        RECT  39.744 0 39.762 0.144 ;
    END
  END x[212]
  PIN x[213]
    DIRECTION INPUT ;
    USE SIGNAL ;
    PORT
      LAYER M5 ;
        RECT  39.792 0 39.816 0.192 ;
    END
  END x[213]
  PIN x[214]
    DIRECTION INPUT ;
    USE SIGNAL ;
    PORT
      LAYER M3 ;
        RECT  39.888 0 39.906 0.144 ;
    END
  END x[214]
  PIN x[215]
    DIRECTION INPUT ;
    USE SIGNAL ;
    PORT
      LAYER M5 ;
        RECT  39.936 0 39.96 0.192 ;
    END
  END x[215]
  PIN x[216]
    DIRECTION INPUT ;
    USE SIGNAL ;
    PORT
      LAYER M3 ;
        RECT  40.032 0 40.05 0.144 ;
    END
  END x[216]
  PIN x[217]
    DIRECTION INPUT ;
    USE SIGNAL ;
    PORT
      LAYER M5 ;
        RECT  40.08 0 40.104 0.192 ;
    END
  END x[217]
  PIN x[218]
    DIRECTION INPUT ;
    USE SIGNAL ;
    PORT
      LAYER M3 ;
        RECT  40.176 0 40.194 0.144 ;
    END
  END x[218]
  PIN x[219]
    DIRECTION INPUT ;
    USE SIGNAL ;
    PORT
      LAYER M5 ;
        RECT  40.224 0 40.248 0.192 ;
    END
  END x[219]
  PIN x[21]
    DIRECTION INPUT ;
    USE SIGNAL ;
    PORT
      LAYER M5 ;
        RECT  25.968 0 25.992 0.192 ;
    END
  END x[21]
  PIN x[220]
    DIRECTION INPUT ;
    USE SIGNAL ;
    PORT
      LAYER M3 ;
        RECT  40.32 0 40.338 0.144 ;
    END
  END x[220]
  PIN x[221]
    DIRECTION INPUT ;
    USE SIGNAL ;
    PORT
      LAYER M5 ;
        RECT  40.368 0 40.392 0.192 ;
    END
  END x[221]
  PIN x[222]
    DIRECTION INPUT ;
    USE SIGNAL ;
    PORT
      LAYER M3 ;
        RECT  40.464 0 40.482 0.144 ;
    END
  END x[222]
  PIN x[223]
    DIRECTION INPUT ;
    USE SIGNAL ;
    PORT
      LAYER M5 ;
        RECT  40.512 0 40.536 0.192 ;
    END
  END x[223]
  PIN x[224]
    DIRECTION INPUT ;
    USE SIGNAL ;
    PORT
      LAYER M3 ;
        RECT  40.608 0 40.626 0.144 ;
    END
  END x[224]
  PIN x[225]
    DIRECTION INPUT ;
    USE SIGNAL ;
    PORT
      LAYER M5 ;
        RECT  40.656 0 40.68 0.192 ;
    END
  END x[225]
  PIN x[226]
    DIRECTION INPUT ;
    USE SIGNAL ;
    PORT
      LAYER M3 ;
        RECT  40.752 0 40.77 0.144 ;
    END
  END x[226]
  PIN x[227]
    DIRECTION INPUT ;
    USE SIGNAL ;
    PORT
      LAYER M5 ;
        RECT  40.8 0 40.824 0.192 ;
    END
  END x[227]
  PIN x[228]
    DIRECTION INPUT ;
    USE SIGNAL ;
    PORT
      LAYER M3 ;
        RECT  40.896 0 40.914 0.144 ;
    END
  END x[228]
  PIN x[229]
    DIRECTION INPUT ;
    USE SIGNAL ;
    PORT
      LAYER M5 ;
        RECT  40.944 0 40.968 0.192 ;
    END
  END x[229]
  PIN x[22]
    DIRECTION INPUT ;
    USE SIGNAL ;
    PORT
      LAYER M3 ;
        RECT  26.064 0 26.082 0.144 ;
    END
  END x[22]
  PIN x[230]
    DIRECTION INPUT ;
    USE SIGNAL ;
    PORT
      LAYER M3 ;
        RECT  41.04 0 41.058 0.144 ;
    END
  END x[230]
  PIN x[231]
    DIRECTION INPUT ;
    USE SIGNAL ;
    PORT
      LAYER M5 ;
        RECT  41.088 0 41.112 0.192 ;
    END
  END x[231]
  PIN x[232]
    DIRECTION INPUT ;
    USE SIGNAL ;
    PORT
      LAYER M3 ;
        RECT  41.184 0 41.202 0.144 ;
    END
  END x[232]
  PIN x[233]
    DIRECTION INPUT ;
    USE SIGNAL ;
    PORT
      LAYER M5 ;
        RECT  41.232 0 41.256 0.192 ;
    END
  END x[233]
  PIN x[234]
    DIRECTION INPUT ;
    USE SIGNAL ;
    PORT
      LAYER M3 ;
        RECT  41.328 0 41.346 0.144 ;
    END
  END x[234]
  PIN x[235]
    DIRECTION INPUT ;
    USE SIGNAL ;
    PORT
      LAYER M5 ;
        RECT  41.376 0 41.4 0.192 ;
    END
  END x[235]
  PIN x[236]
    DIRECTION INPUT ;
    USE SIGNAL ;
    PORT
      LAYER M3 ;
        RECT  41.472 0 41.49 0.144 ;
    END
  END x[236]
  PIN x[237]
    DIRECTION INPUT ;
    USE SIGNAL ;
    PORT
      LAYER M5 ;
        RECT  41.52 0 41.544 0.192 ;
    END
  END x[237]
  PIN x[238]
    DIRECTION INPUT ;
    USE SIGNAL ;
    PORT
      LAYER M3 ;
        RECT  41.616 0 41.634 0.144 ;
    END
  END x[238]
  PIN x[239]
    DIRECTION INPUT ;
    USE SIGNAL ;
    PORT
      LAYER M5 ;
        RECT  41.664 0 41.688 0.192 ;
    END
  END x[239]
  PIN x[23]
    DIRECTION INPUT ;
    USE SIGNAL ;
    PORT
      LAYER M5 ;
        RECT  26.112 0 26.136 0.192 ;
    END
  END x[23]
  PIN x[240]
    DIRECTION INPUT ;
    USE SIGNAL ;
    PORT
      LAYER M3 ;
        RECT  41.76 0 41.778 0.144 ;
    END
  END x[240]
  PIN x[241]
    DIRECTION INPUT ;
    USE SIGNAL ;
    PORT
      LAYER M5 ;
        RECT  41.808 0 41.832 0.192 ;
    END
  END x[241]
  PIN x[242]
    DIRECTION INPUT ;
    USE SIGNAL ;
    PORT
      LAYER M3 ;
        RECT  41.904 0 41.922 0.144 ;
    END
  END x[242]
  PIN x[243]
    DIRECTION INPUT ;
    USE SIGNAL ;
    PORT
      LAYER M5 ;
        RECT  41.952 0 41.976 0.192 ;
    END
  END x[243]
  PIN x[244]
    DIRECTION INPUT ;
    USE SIGNAL ;
    PORT
      LAYER M3 ;
        RECT  42.048 0 42.066 0.144 ;
    END
  END x[244]
  PIN x[245]
    DIRECTION INPUT ;
    USE SIGNAL ;
    PORT
      LAYER M5 ;
        RECT  42.096 0 42.12 0.192 ;
    END
  END x[245]
  PIN x[246]
    DIRECTION INPUT ;
    USE SIGNAL ;
    PORT
      LAYER M3 ;
        RECT  42.192 0 42.21 0.144 ;
    END
  END x[246]
  PIN x[247]
    DIRECTION INPUT ;
    USE SIGNAL ;
    PORT
      LAYER M5 ;
        RECT  42.24 0 42.264 0.192 ;
    END
  END x[247]
  PIN x[248]
    DIRECTION INPUT ;
    USE SIGNAL ;
    PORT
      LAYER M3 ;
        RECT  42.336 0 42.354 0.144 ;
    END
  END x[248]
  PIN x[249]
    DIRECTION INPUT ;
    USE SIGNAL ;
    PORT
      LAYER M5 ;
        RECT  42.384 0 42.408 0.192 ;
    END
  END x[249]
  PIN x[24]
    DIRECTION INPUT ;
    USE SIGNAL ;
    PORT
      LAYER M3 ;
        RECT  26.208 0 26.226 0.144 ;
    END
  END x[24]
  PIN x[250]
    DIRECTION INPUT ;
    USE SIGNAL ;
    PORT
      LAYER M3 ;
        RECT  42.48 0 42.498 0.144 ;
    END
  END x[250]
  PIN x[251]
    DIRECTION INPUT ;
    USE SIGNAL ;
    PORT
      LAYER M5 ;
        RECT  42.528 0 42.552 0.192 ;
    END
  END x[251]
  PIN x[252]
    DIRECTION INPUT ;
    USE SIGNAL ;
    PORT
      LAYER M3 ;
        RECT  42.624 0 42.642 0.144 ;
    END
  END x[252]
  PIN x[253]
    DIRECTION INPUT ;
    USE SIGNAL ;
    PORT
      LAYER M5 ;
        RECT  42.672 0 42.696 0.192 ;
    END
  END x[253]
  PIN x[254]
    DIRECTION INPUT ;
    USE SIGNAL ;
    PORT
      LAYER M3 ;
        RECT  42.768 0 42.786 0.144 ;
    END
  END x[254]
  PIN x[255]
    DIRECTION INPUT ;
    USE SIGNAL ;
    PORT
      LAYER M5 ;
        RECT  42.816 0 42.84 0.192 ;
    END
  END x[255]
  PIN x[25]
    DIRECTION INPUT ;
    USE SIGNAL ;
    PORT
      LAYER M5 ;
        RECT  26.256 0 26.28 0.192 ;
    END
  END x[25]
  PIN x[26]
    DIRECTION INPUT ;
    USE SIGNAL ;
    PORT
      LAYER M3 ;
        RECT  26.352 0 26.37 0.144 ;
    END
  END x[26]
  PIN x[27]
    DIRECTION INPUT ;
    USE SIGNAL ;
    PORT
      LAYER M5 ;
        RECT  26.4 0 26.424 0.192 ;
    END
  END x[27]
  PIN x[28]
    DIRECTION INPUT ;
    USE SIGNAL ;
    PORT
      LAYER M3 ;
        RECT  26.496 0 26.514 0.144 ;
    END
  END x[28]
  PIN x[29]
    DIRECTION INPUT ;
    USE SIGNAL ;
    PORT
      LAYER M5 ;
        RECT  26.544 0 26.568 0.192 ;
    END
  END x[29]
  PIN x[2]
    DIRECTION INPUT ;
    USE SIGNAL ;
    PORT
      LAYER M3 ;
        RECT  24.624 0 24.642 0.144 ;
    END
  END x[2]
  PIN x[30]
    DIRECTION INPUT ;
    USE SIGNAL ;
    PORT
      LAYER M3 ;
        RECT  26.64 0 26.658 0.144 ;
    END
  END x[30]
  PIN x[31]
    DIRECTION INPUT ;
    USE SIGNAL ;
    PORT
      LAYER M5 ;
        RECT  26.688 0 26.712 0.192 ;
    END
  END x[31]
  PIN x[32]
    DIRECTION INPUT ;
    USE SIGNAL ;
    PORT
      LAYER M3 ;
        RECT  26.784 0 26.802 0.144 ;
    END
  END x[32]
  PIN x[33]
    DIRECTION INPUT ;
    USE SIGNAL ;
    PORT
      LAYER M5 ;
        RECT  26.832 0 26.856 0.192 ;
    END
  END x[33]
  PIN x[34]
    DIRECTION INPUT ;
    USE SIGNAL ;
    PORT
      LAYER M3 ;
        RECT  26.928 0 26.946 0.144 ;
    END
  END x[34]
  PIN x[35]
    DIRECTION INPUT ;
    USE SIGNAL ;
    PORT
      LAYER M5 ;
        RECT  26.976 0 27 0.192 ;
    END
  END x[35]
  PIN x[36]
    DIRECTION INPUT ;
    USE SIGNAL ;
    PORT
      LAYER M3 ;
        RECT  27.072 0 27.09 0.144 ;
    END
  END x[36]
  PIN x[37]
    DIRECTION INPUT ;
    USE SIGNAL ;
    PORT
      LAYER M5 ;
        RECT  27.12 0 27.144 0.192 ;
    END
  END x[37]
  PIN x[38]
    DIRECTION INPUT ;
    USE SIGNAL ;
    PORT
      LAYER M3 ;
        RECT  27.216 0 27.234 0.144 ;
    END
  END x[38]
  PIN x[39]
    DIRECTION INPUT ;
    USE SIGNAL ;
    PORT
      LAYER M5 ;
        RECT  27.264 0 27.288 0.192 ;
    END
  END x[39]
  PIN x[3]
    DIRECTION INPUT ;
    USE SIGNAL ;
    PORT
      LAYER M5 ;
        RECT  24.672 0 24.696 0.192 ;
    END
  END x[3]
  PIN x[40]
    DIRECTION INPUT ;
    USE SIGNAL ;
    PORT
      LAYER M3 ;
        RECT  27.36 0 27.378 0.144 ;
    END
  END x[40]
  PIN x[41]
    DIRECTION INPUT ;
    USE SIGNAL ;
    PORT
      LAYER M5 ;
        RECT  27.408 0 27.432 0.192 ;
    END
  END x[41]
  PIN x[42]
    DIRECTION INPUT ;
    USE SIGNAL ;
    PORT
      LAYER M3 ;
        RECT  27.504 0 27.522 0.144 ;
    END
  END x[42]
  PIN x[43]
    DIRECTION INPUT ;
    USE SIGNAL ;
    PORT
      LAYER M5 ;
        RECT  27.552 0 27.576 0.192 ;
    END
  END x[43]
  PIN x[44]
    DIRECTION INPUT ;
    USE SIGNAL ;
    PORT
      LAYER M3 ;
        RECT  27.648 0 27.666 0.144 ;
    END
  END x[44]
  PIN x[45]
    DIRECTION INPUT ;
    USE SIGNAL ;
    PORT
      LAYER M5 ;
        RECT  27.696 0 27.72 0.192 ;
    END
  END x[45]
  PIN x[46]
    DIRECTION INPUT ;
    USE SIGNAL ;
    PORT
      LAYER M3 ;
        RECT  27.792 0 27.81 0.144 ;
    END
  END x[46]
  PIN x[47]
    DIRECTION INPUT ;
    USE SIGNAL ;
    PORT
      LAYER M5 ;
        RECT  27.84 0 27.864 0.192 ;
    END
  END x[47]
  PIN x[48]
    DIRECTION INPUT ;
    USE SIGNAL ;
    PORT
      LAYER M3 ;
        RECT  27.936 0 27.954 0.144 ;
    END
  END x[48]
  PIN x[49]
    DIRECTION INPUT ;
    USE SIGNAL ;
    PORT
      LAYER M5 ;
        RECT  27.984 0 28.008 0.192 ;
    END
  END x[49]
  PIN x[4]
    DIRECTION INPUT ;
    USE SIGNAL ;
    PORT
      LAYER M3 ;
        RECT  24.768 0 24.786 0.144 ;
    END
  END x[4]
  PIN x[50]
    DIRECTION INPUT ;
    USE SIGNAL ;
    PORT
      LAYER M3 ;
        RECT  28.08 0 28.098 0.144 ;
    END
  END x[50]
  PIN x[51]
    DIRECTION INPUT ;
    USE SIGNAL ;
    PORT
      LAYER M5 ;
        RECT  28.128 0 28.152 0.192 ;
    END
  END x[51]
  PIN x[52]
    DIRECTION INPUT ;
    USE SIGNAL ;
    PORT
      LAYER M3 ;
        RECT  28.224 0 28.242 0.144 ;
    END
  END x[52]
  PIN x[53]
    DIRECTION INPUT ;
    USE SIGNAL ;
    PORT
      LAYER M5 ;
        RECT  28.272 0 28.296 0.192 ;
    END
  END x[53]
  PIN x[54]
    DIRECTION INPUT ;
    USE SIGNAL ;
    PORT
      LAYER M3 ;
        RECT  28.368 0 28.386 0.144 ;
    END
  END x[54]
  PIN x[55]
    DIRECTION INPUT ;
    USE SIGNAL ;
    PORT
      LAYER M5 ;
        RECT  28.416 0 28.44 0.192 ;
    END
  END x[55]
  PIN x[56]
    DIRECTION INPUT ;
    USE SIGNAL ;
    PORT
      LAYER M3 ;
        RECT  28.512 0 28.53 0.144 ;
    END
  END x[56]
  PIN x[57]
    DIRECTION INPUT ;
    USE SIGNAL ;
    PORT
      LAYER M5 ;
        RECT  28.56 0 28.584 0.192 ;
    END
  END x[57]
  PIN x[58]
    DIRECTION INPUT ;
    USE SIGNAL ;
    PORT
      LAYER M3 ;
        RECT  28.656 0 28.674 0.144 ;
    END
  END x[58]
  PIN x[59]
    DIRECTION INPUT ;
    USE SIGNAL ;
    PORT
      LAYER M5 ;
        RECT  28.704 0 28.728 0.192 ;
    END
  END x[59]
  PIN x[5]
    DIRECTION INPUT ;
    USE SIGNAL ;
    PORT
      LAYER M5 ;
        RECT  24.816 0 24.84 0.192 ;
    END
  END x[5]
  PIN x[60]
    DIRECTION INPUT ;
    USE SIGNAL ;
    PORT
      LAYER M3 ;
        RECT  28.8 0 28.818 0.144 ;
    END
  END x[60]
  PIN x[61]
    DIRECTION INPUT ;
    USE SIGNAL ;
    PORT
      LAYER M5 ;
        RECT  28.848 0 28.872 0.192 ;
    END
  END x[61]
  PIN x[62]
    DIRECTION INPUT ;
    USE SIGNAL ;
    PORT
      LAYER M3 ;
        RECT  28.944 0 28.962 0.144 ;
    END
  END x[62]
  PIN x[63]
    DIRECTION INPUT ;
    USE SIGNAL ;
    PORT
      LAYER M5 ;
        RECT  28.992 0 29.016 0.192 ;
    END
  END x[63]
  PIN x[64]
    DIRECTION INPUT ;
    USE SIGNAL ;
    PORT
      LAYER M3 ;
        RECT  29.088 0 29.106 0.144 ;
    END
  END x[64]
  PIN x[65]
    DIRECTION INPUT ;
    USE SIGNAL ;
    PORT
      LAYER M5 ;
        RECT  29.136 0 29.16 0.192 ;
    END
  END x[65]
  PIN x[66]
    DIRECTION INPUT ;
    USE SIGNAL ;
    PORT
      LAYER M3 ;
        RECT  29.232 0 29.25 0.144 ;
    END
  END x[66]
  PIN x[67]
    DIRECTION INPUT ;
    USE SIGNAL ;
    PORT
      LAYER M5 ;
        RECT  29.28 0 29.304 0.192 ;
    END
  END x[67]
  PIN x[68]
    DIRECTION INPUT ;
    USE SIGNAL ;
    PORT
      LAYER M3 ;
        RECT  29.376 0 29.394 0.144 ;
    END
  END x[68]
  PIN x[69]
    DIRECTION INPUT ;
    USE SIGNAL ;
    PORT
      LAYER M5 ;
        RECT  29.424 0 29.448 0.192 ;
    END
  END x[69]
  PIN x[6]
    DIRECTION INPUT ;
    USE SIGNAL ;
    PORT
      LAYER M3 ;
        RECT  24.912 0 24.93 0.144 ;
    END
  END x[6]
  PIN x[70]
    DIRECTION INPUT ;
    USE SIGNAL ;
    PORT
      LAYER M3 ;
        RECT  29.52 0 29.538 0.144 ;
    END
  END x[70]
  PIN x[71]
    DIRECTION INPUT ;
    USE SIGNAL ;
    PORT
      LAYER M5 ;
        RECT  29.568 0 29.592 0.192 ;
    END
  END x[71]
  PIN x[72]
    DIRECTION INPUT ;
    USE SIGNAL ;
    PORT
      LAYER M3 ;
        RECT  29.664 0 29.682 0.144 ;
    END
  END x[72]
  PIN x[73]
    DIRECTION INPUT ;
    USE SIGNAL ;
    PORT
      LAYER M5 ;
        RECT  29.712 0 29.736 0.192 ;
    END
  END x[73]
  PIN x[74]
    DIRECTION INPUT ;
    USE SIGNAL ;
    PORT
      LAYER M3 ;
        RECT  29.808 0 29.826 0.144 ;
    END
  END x[74]
  PIN x[75]
    DIRECTION INPUT ;
    USE SIGNAL ;
    PORT
      LAYER M5 ;
        RECT  29.856 0 29.88 0.192 ;
    END
  END x[75]
  PIN x[76]
    DIRECTION INPUT ;
    USE SIGNAL ;
    PORT
      LAYER M3 ;
        RECT  29.952 0 29.97 0.144 ;
    END
  END x[76]
  PIN x[77]
    DIRECTION INPUT ;
    USE SIGNAL ;
    PORT
      LAYER M5 ;
        RECT  30 0 30.024 0.192 ;
    END
  END x[77]
  PIN x[78]
    DIRECTION INPUT ;
    USE SIGNAL ;
    PORT
      LAYER M3 ;
        RECT  30.096 0 30.114 0.144 ;
    END
  END x[78]
  PIN x[79]
    DIRECTION INPUT ;
    USE SIGNAL ;
    PORT
      LAYER M5 ;
        RECT  30.144 0 30.168 0.192 ;
    END
  END x[79]
  PIN x[7]
    DIRECTION INPUT ;
    USE SIGNAL ;
    PORT
      LAYER M5 ;
        RECT  24.96 0 24.984 0.192 ;
    END
  END x[7]
  PIN x[80]
    DIRECTION INPUT ;
    USE SIGNAL ;
    PORT
      LAYER M3 ;
        RECT  30.24 0 30.258 0.144 ;
    END
  END x[80]
  PIN x[81]
    DIRECTION INPUT ;
    USE SIGNAL ;
    PORT
      LAYER M5 ;
        RECT  30.288 0 30.312 0.192 ;
    END
  END x[81]
  PIN x[82]
    DIRECTION INPUT ;
    USE SIGNAL ;
    PORT
      LAYER M3 ;
        RECT  30.384 0 30.402 0.144 ;
    END
  END x[82]
  PIN x[83]
    DIRECTION INPUT ;
    USE SIGNAL ;
    PORT
      LAYER M5 ;
        RECT  30.432 0 30.456 0.192 ;
    END
  END x[83]
  PIN x[84]
    DIRECTION INPUT ;
    USE SIGNAL ;
    PORT
      LAYER M3 ;
        RECT  30.528 0 30.546 0.144 ;
    END
  END x[84]
  PIN x[85]
    DIRECTION INPUT ;
    USE SIGNAL ;
    PORT
      LAYER M5 ;
        RECT  30.576 0 30.6 0.192 ;
    END
  END x[85]
  PIN x[86]
    DIRECTION INPUT ;
    USE SIGNAL ;
    PORT
      LAYER M3 ;
        RECT  30.672 0 30.69 0.144 ;
    END
  END x[86]
  PIN x[87]
    DIRECTION INPUT ;
    USE SIGNAL ;
    PORT
      LAYER M5 ;
        RECT  30.72 0 30.744 0.192 ;
    END
  END x[87]
  PIN x[88]
    DIRECTION INPUT ;
    USE SIGNAL ;
    PORT
      LAYER M3 ;
        RECT  30.816 0 30.834 0.144 ;
    END
  END x[88]
  PIN x[89]
    DIRECTION INPUT ;
    USE SIGNAL ;
    PORT
      LAYER M5 ;
        RECT  30.864 0 30.888 0.192 ;
    END
  END x[89]
  PIN x[8]
    DIRECTION INPUT ;
    USE SIGNAL ;
    PORT
      LAYER M3 ;
        RECT  25.056 0 25.074 0.144 ;
    END
  END x[8]
  PIN x[90]
    DIRECTION INPUT ;
    USE SIGNAL ;
    PORT
      LAYER M3 ;
        RECT  30.96 0 30.978 0.144 ;
    END
  END x[90]
  PIN x[91]
    DIRECTION INPUT ;
    USE SIGNAL ;
    PORT
      LAYER M5 ;
        RECT  31.008 0 31.032 0.192 ;
    END
  END x[91]
  PIN x[92]
    DIRECTION INPUT ;
    USE SIGNAL ;
    PORT
      LAYER M3 ;
        RECT  31.104 0 31.122 0.144 ;
    END
  END x[92]
  PIN x[93]
    DIRECTION INPUT ;
    USE SIGNAL ;
    PORT
      LAYER M5 ;
        RECT  31.152 0 31.176 0.192 ;
    END
  END x[93]
  PIN x[94]
    DIRECTION INPUT ;
    USE SIGNAL ;
    PORT
      LAYER M3 ;
        RECT  31.248 0 31.266 0.144 ;
    END
  END x[94]
  PIN x[95]
    DIRECTION INPUT ;
    USE SIGNAL ;
    PORT
      LAYER M5 ;
        RECT  31.296 0 31.32 0.192 ;
    END
  END x[95]
  PIN x[96]
    DIRECTION INPUT ;
    USE SIGNAL ;
    PORT
      LAYER M3 ;
        RECT  31.392 0 31.41 0.144 ;
    END
  END x[96]
  PIN x[97]
    DIRECTION INPUT ;
    USE SIGNAL ;
    PORT
      LAYER M5 ;
        RECT  31.44 0 31.464 0.192 ;
    END
  END x[97]
  PIN x[98]
    DIRECTION INPUT ;
    USE SIGNAL ;
    PORT
      LAYER M3 ;
        RECT  31.536 0 31.554 0.144 ;
    END
  END x[98]
  PIN x[99]
    DIRECTION INPUT ;
    USE SIGNAL ;
    PORT
      LAYER M5 ;
        RECT  31.584 0 31.608 0.192 ;
    END
  END x[99]
  PIN x[9]
    DIRECTION INPUT ;
    USE SIGNAL ;
    PORT
      LAYER M5 ;
        RECT  25.104 0 25.128 0.192 ;
    END
  END x[9]
  PIN xg[0]
    DIRECTION OUTPUT ;
    USE SIGNAL ;
    PORT
      LAYER M3 ;
        RECT  51.48 86.256 51.498 86.4 ;
    END
  END xg[0]
  PIN xg[100]
    DIRECTION OUTPUT ;
    USE SIGNAL ;
    PORT
      LAYER M3 ;
        RECT  58.68 86.256 58.698 86.4 ;
    END
  END xg[100]
  PIN xg[101]
    DIRECTION OUTPUT ;
    USE SIGNAL ;
    PORT
      LAYER M5 ;
        RECT  58.704 86.208 58.728 86.4 ;
    END
  END xg[101]
  PIN xg[102]
    DIRECTION OUTPUT ;
    USE SIGNAL ;
    PORT
      LAYER M3 ;
        RECT  58.824 86.256 58.842 86.4 ;
    END
  END xg[102]
  PIN xg[103]
    DIRECTION OUTPUT ;
    USE SIGNAL ;
    PORT
      LAYER M5 ;
        RECT  58.848 86.208 58.872 86.4 ;
    END
  END xg[103]
  PIN xg[104]
    DIRECTION OUTPUT ;
    USE SIGNAL ;
    PORT
      LAYER M3 ;
        RECT  58.968 86.256 58.986 86.4 ;
    END
  END xg[104]
  PIN xg[105]
    DIRECTION OUTPUT ;
    USE SIGNAL ;
    PORT
      LAYER M5 ;
        RECT  58.992 86.208 59.016 86.4 ;
    END
  END xg[105]
  PIN xg[106]
    DIRECTION OUTPUT ;
    USE SIGNAL ;
    PORT
      LAYER M3 ;
        RECT  59.112 86.256 59.13 86.4 ;
    END
  END xg[106]
  PIN xg[107]
    DIRECTION OUTPUT ;
    USE SIGNAL ;
    PORT
      LAYER M5 ;
        RECT  59.136 86.208 59.16 86.4 ;
    END
  END xg[107]
  PIN xg[108]
    DIRECTION OUTPUT ;
    USE SIGNAL ;
    PORT
      LAYER M3 ;
        RECT  59.256 86.256 59.274 86.4 ;
    END
  END xg[108]
  PIN xg[109]
    DIRECTION OUTPUT ;
    USE SIGNAL ;
    PORT
      LAYER M5 ;
        RECT  59.28 86.208 59.304 86.4 ;
    END
  END xg[109]
  PIN xg[10]
    DIRECTION OUTPUT ;
    USE SIGNAL ;
    PORT
      LAYER M3 ;
        RECT  52.2 86.256 52.218 86.4 ;
    END
  END xg[10]
  PIN xg[110]
    DIRECTION OUTPUT ;
    USE SIGNAL ;
    PORT
      LAYER M3 ;
        RECT  59.4 86.256 59.418 86.4 ;
    END
  END xg[110]
  PIN xg[111]
    DIRECTION OUTPUT ;
    USE SIGNAL ;
    PORT
      LAYER M5 ;
        RECT  59.424 86.208 59.448 86.4 ;
    END
  END xg[111]
  PIN xg[112]
    DIRECTION OUTPUT ;
    USE SIGNAL ;
    PORT
      LAYER M3 ;
        RECT  59.544 86.256 59.562 86.4 ;
    END
  END xg[112]
  PIN xg[113]
    DIRECTION OUTPUT ;
    USE SIGNAL ;
    PORT
      LAYER M5 ;
        RECT  59.568 86.208 59.592 86.4 ;
    END
  END xg[113]
  PIN xg[114]
    DIRECTION OUTPUT ;
    USE SIGNAL ;
    PORT
      LAYER M3 ;
        RECT  59.688 86.256 59.706 86.4 ;
    END
  END xg[114]
  PIN xg[115]
    DIRECTION OUTPUT ;
    USE SIGNAL ;
    PORT
      LAYER M5 ;
        RECT  59.712 86.208 59.736 86.4 ;
    END
  END xg[115]
  PIN xg[116]
    DIRECTION OUTPUT ;
    USE SIGNAL ;
    PORT
      LAYER M3 ;
        RECT  59.832 86.256 59.85 86.4 ;
    END
  END xg[116]
  PIN xg[117]
    DIRECTION OUTPUT ;
    USE SIGNAL ;
    PORT
      LAYER M5 ;
        RECT  59.856 86.208 59.88 86.4 ;
    END
  END xg[117]
  PIN xg[118]
    DIRECTION OUTPUT ;
    USE SIGNAL ;
    PORT
      LAYER M3 ;
        RECT  59.976 86.256 59.994 86.4 ;
    END
  END xg[118]
  PIN xg[119]
    DIRECTION OUTPUT ;
    USE SIGNAL ;
    PORT
      LAYER M5 ;
        RECT  60 86.208 60.024 86.4 ;
    END
  END xg[119]
  PIN xg[11]
    DIRECTION OUTPUT ;
    USE SIGNAL ;
    PORT
      LAYER M5 ;
        RECT  52.224 86.208 52.248 86.4 ;
    END
  END xg[11]
  PIN xg[120]
    DIRECTION OUTPUT ;
    USE SIGNAL ;
    PORT
      LAYER M3 ;
        RECT  60.12 86.256 60.138 86.4 ;
    END
  END xg[120]
  PIN xg[121]
    DIRECTION OUTPUT ;
    USE SIGNAL ;
    PORT
      LAYER M5 ;
        RECT  60.144 86.208 60.168 86.4 ;
    END
  END xg[121]
  PIN xg[122]
    DIRECTION OUTPUT ;
    USE SIGNAL ;
    PORT
      LAYER M3 ;
        RECT  60.264 86.256 60.282 86.4 ;
    END
  END xg[122]
  PIN xg[123]
    DIRECTION OUTPUT ;
    USE SIGNAL ;
    PORT
      LAYER M5 ;
        RECT  60.288 86.208 60.312 86.4 ;
    END
  END xg[123]
  PIN xg[124]
    DIRECTION OUTPUT ;
    USE SIGNAL ;
    PORT
      LAYER M3 ;
        RECT  60.408 86.256 60.426 86.4 ;
    END
  END xg[124]
  PIN xg[125]
    DIRECTION OUTPUT ;
    USE SIGNAL ;
    PORT
      LAYER M5 ;
        RECT  60.432 86.208 60.456 86.4 ;
    END
  END xg[125]
  PIN xg[126]
    DIRECTION OUTPUT ;
    USE SIGNAL ;
    PORT
      LAYER M3 ;
        RECT  60.552 86.256 60.57 86.4 ;
    END
  END xg[126]
  PIN xg[127]
    DIRECTION OUTPUT ;
    USE SIGNAL ;
    PORT
      LAYER M5 ;
        RECT  60.576 86.208 60.6 86.4 ;
    END
  END xg[127]
  PIN xg[128]
    DIRECTION OUTPUT ;
    USE SIGNAL ;
    PORT
      LAYER M3 ;
        RECT  60.696 86.256 60.714 86.4 ;
    END
  END xg[128]
  PIN xg[129]
    DIRECTION OUTPUT ;
    USE SIGNAL ;
    PORT
      LAYER M5 ;
        RECT  60.72 86.208 60.744 86.4 ;
    END
  END xg[129]
  PIN xg[12]
    DIRECTION OUTPUT ;
    USE SIGNAL ;
    PORT
      LAYER M3 ;
        RECT  52.344 86.256 52.362 86.4 ;
    END
  END xg[12]
  PIN xg[130]
    DIRECTION OUTPUT ;
    USE SIGNAL ;
    PORT
      LAYER M3 ;
        RECT  60.84 86.256 60.858 86.4 ;
    END
  END xg[130]
  PIN xg[131]
    DIRECTION OUTPUT ;
    USE SIGNAL ;
    PORT
      LAYER M5 ;
        RECT  60.864 86.208 60.888 86.4 ;
    END
  END xg[131]
  PIN xg[132]
    DIRECTION OUTPUT ;
    USE SIGNAL ;
    PORT
      LAYER M3 ;
        RECT  60.984 86.256 61.002 86.4 ;
    END
  END xg[132]
  PIN xg[133]
    DIRECTION OUTPUT ;
    USE SIGNAL ;
    PORT
      LAYER M5 ;
        RECT  61.008 86.208 61.032 86.4 ;
    END
  END xg[133]
  PIN xg[134]
    DIRECTION OUTPUT ;
    USE SIGNAL ;
    PORT
      LAYER M3 ;
        RECT  61.128 86.256 61.146 86.4 ;
    END
  END xg[134]
  PIN xg[135]
    DIRECTION OUTPUT ;
    USE SIGNAL ;
    PORT
      LAYER M5 ;
        RECT  61.152 86.208 61.176 86.4 ;
    END
  END xg[135]
  PIN xg[136]
    DIRECTION OUTPUT ;
    USE SIGNAL ;
    PORT
      LAYER M3 ;
        RECT  61.272 86.256 61.29 86.4 ;
    END
  END xg[136]
  PIN xg[137]
    DIRECTION OUTPUT ;
    USE SIGNAL ;
    PORT
      LAYER M5 ;
        RECT  61.296 86.208 61.32 86.4 ;
    END
  END xg[137]
  PIN xg[138]
    DIRECTION OUTPUT ;
    USE SIGNAL ;
    PORT
      LAYER M3 ;
        RECT  61.416 86.256 61.434 86.4 ;
    END
  END xg[138]
  PIN xg[139]
    DIRECTION OUTPUT ;
    USE SIGNAL ;
    PORT
      LAYER M5 ;
        RECT  61.44 86.208 61.464 86.4 ;
    END
  END xg[139]
  PIN xg[13]
    DIRECTION OUTPUT ;
    USE SIGNAL ;
    PORT
      LAYER M5 ;
        RECT  52.368 86.208 52.392 86.4 ;
    END
  END xg[13]
  PIN xg[140]
    DIRECTION OUTPUT ;
    USE SIGNAL ;
    PORT
      LAYER M3 ;
        RECT  61.56 86.256 61.578 86.4 ;
    END
  END xg[140]
  PIN xg[141]
    DIRECTION OUTPUT ;
    USE SIGNAL ;
    PORT
      LAYER M5 ;
        RECT  61.584 86.208 61.608 86.4 ;
    END
  END xg[141]
  PIN xg[142]
    DIRECTION OUTPUT ;
    USE SIGNAL ;
    PORT
      LAYER M3 ;
        RECT  61.704 86.256 61.722 86.4 ;
    END
  END xg[142]
  PIN xg[143]
    DIRECTION OUTPUT ;
    USE SIGNAL ;
    PORT
      LAYER M5 ;
        RECT  61.728 86.208 61.752 86.4 ;
    END
  END xg[143]
  PIN xg[144]
    DIRECTION OUTPUT ;
    USE SIGNAL ;
    PORT
      LAYER M3 ;
        RECT  61.848 86.256 61.866 86.4 ;
    END
  END xg[144]
  PIN xg[145]
    DIRECTION OUTPUT ;
    USE SIGNAL ;
    PORT
      LAYER M5 ;
        RECT  61.872 86.208 61.896 86.4 ;
    END
  END xg[145]
  PIN xg[146]
    DIRECTION OUTPUT ;
    USE SIGNAL ;
    PORT
      LAYER M3 ;
        RECT  61.992 86.256 62.01 86.4 ;
    END
  END xg[146]
  PIN xg[147]
    DIRECTION OUTPUT ;
    USE SIGNAL ;
    PORT
      LAYER M5 ;
        RECT  62.016 86.208 62.04 86.4 ;
    END
  END xg[147]
  PIN xg[148]
    DIRECTION OUTPUT ;
    USE SIGNAL ;
    PORT
      LAYER M3 ;
        RECT  62.136 86.256 62.154 86.4 ;
    END
  END xg[148]
  PIN xg[149]
    DIRECTION OUTPUT ;
    USE SIGNAL ;
    PORT
      LAYER M5 ;
        RECT  62.16 86.208 62.184 86.4 ;
    END
  END xg[149]
  PIN xg[14]
    DIRECTION OUTPUT ;
    USE SIGNAL ;
    PORT
      LAYER M3 ;
        RECT  52.488 86.256 52.506 86.4 ;
    END
  END xg[14]
  PIN xg[150]
    DIRECTION OUTPUT ;
    USE SIGNAL ;
    PORT
      LAYER M3 ;
        RECT  62.28 86.256 62.298 86.4 ;
    END
  END xg[150]
  PIN xg[151]
    DIRECTION OUTPUT ;
    USE SIGNAL ;
    PORT
      LAYER M5 ;
        RECT  62.304 86.208 62.328 86.4 ;
    END
  END xg[151]
  PIN xg[152]
    DIRECTION OUTPUT ;
    USE SIGNAL ;
    PORT
      LAYER M3 ;
        RECT  62.424 86.256 62.442 86.4 ;
    END
  END xg[152]
  PIN xg[153]
    DIRECTION OUTPUT ;
    USE SIGNAL ;
    PORT
      LAYER M5 ;
        RECT  62.448 86.208 62.472 86.4 ;
    END
  END xg[153]
  PIN xg[154]
    DIRECTION OUTPUT ;
    USE SIGNAL ;
    PORT
      LAYER M3 ;
        RECT  62.568 86.256 62.586 86.4 ;
    END
  END xg[154]
  PIN xg[155]
    DIRECTION OUTPUT ;
    USE SIGNAL ;
    PORT
      LAYER M5 ;
        RECT  62.592 86.208 62.616 86.4 ;
    END
  END xg[155]
  PIN xg[156]
    DIRECTION OUTPUT ;
    USE SIGNAL ;
    PORT
      LAYER M3 ;
        RECT  62.712 86.256 62.73 86.4 ;
    END
  END xg[156]
  PIN xg[157]
    DIRECTION OUTPUT ;
    USE SIGNAL ;
    PORT
      LAYER M5 ;
        RECT  62.736 86.208 62.76 86.4 ;
    END
  END xg[157]
  PIN xg[158]
    DIRECTION OUTPUT ;
    USE SIGNAL ;
    PORT
      LAYER M3 ;
        RECT  62.856 86.256 62.874 86.4 ;
    END
  END xg[158]
  PIN xg[159]
    DIRECTION OUTPUT ;
    USE SIGNAL ;
    PORT
      LAYER M5 ;
        RECT  62.88 86.208 62.904 86.4 ;
    END
  END xg[159]
  PIN xg[15]
    DIRECTION OUTPUT ;
    USE SIGNAL ;
    PORT
      LAYER M5 ;
        RECT  52.512 86.208 52.536 86.4 ;
    END
  END xg[15]
  PIN xg[160]
    DIRECTION OUTPUT ;
    USE SIGNAL ;
    PORT
      LAYER M3 ;
        RECT  63 86.256 63.018 86.4 ;
    END
  END xg[160]
  PIN xg[161]
    DIRECTION OUTPUT ;
    USE SIGNAL ;
    PORT
      LAYER M5 ;
        RECT  63.024 86.208 63.048 86.4 ;
    END
  END xg[161]
  PIN xg[162]
    DIRECTION OUTPUT ;
    USE SIGNAL ;
    PORT
      LAYER M3 ;
        RECT  63.144 86.256 63.162 86.4 ;
    END
  END xg[162]
  PIN xg[163]
    DIRECTION OUTPUT ;
    USE SIGNAL ;
    PORT
      LAYER M5 ;
        RECT  63.168 86.208 63.192 86.4 ;
    END
  END xg[163]
  PIN xg[164]
    DIRECTION OUTPUT ;
    USE SIGNAL ;
    PORT
      LAYER M3 ;
        RECT  63.288 86.256 63.306 86.4 ;
    END
  END xg[164]
  PIN xg[165]
    DIRECTION OUTPUT ;
    USE SIGNAL ;
    PORT
      LAYER M5 ;
        RECT  63.312 86.208 63.336 86.4 ;
    END
  END xg[165]
  PIN xg[166]
    DIRECTION OUTPUT ;
    USE SIGNAL ;
    PORT
      LAYER M3 ;
        RECT  63.432 86.256 63.45 86.4 ;
    END
  END xg[166]
  PIN xg[167]
    DIRECTION OUTPUT ;
    USE SIGNAL ;
    PORT
      LAYER M5 ;
        RECT  63.456 86.208 63.48 86.4 ;
    END
  END xg[167]
  PIN xg[168]
    DIRECTION OUTPUT ;
    USE SIGNAL ;
    PORT
      LAYER M3 ;
        RECT  63.576 86.256 63.594 86.4 ;
    END
  END xg[168]
  PIN xg[169]
    DIRECTION OUTPUT ;
    USE SIGNAL ;
    PORT
      LAYER M5 ;
        RECT  63.6 86.208 63.624 86.4 ;
    END
  END xg[169]
  PIN xg[16]
    DIRECTION OUTPUT ;
    USE SIGNAL ;
    PORT
      LAYER M3 ;
        RECT  52.632 86.256 52.65 86.4 ;
    END
  END xg[16]
  PIN xg[170]
    DIRECTION OUTPUT ;
    USE SIGNAL ;
    PORT
      LAYER M3 ;
        RECT  63.72 86.256 63.738 86.4 ;
    END
  END xg[170]
  PIN xg[171]
    DIRECTION OUTPUT ;
    USE SIGNAL ;
    PORT
      LAYER M5 ;
        RECT  63.744 86.208 63.768 86.4 ;
    END
  END xg[171]
  PIN xg[172]
    DIRECTION OUTPUT ;
    USE SIGNAL ;
    PORT
      LAYER M3 ;
        RECT  63.864 86.256 63.882 86.4 ;
    END
  END xg[172]
  PIN xg[173]
    DIRECTION OUTPUT ;
    USE SIGNAL ;
    PORT
      LAYER M5 ;
        RECT  63.888 86.208 63.912 86.4 ;
    END
  END xg[173]
  PIN xg[174]
    DIRECTION OUTPUT ;
    USE SIGNAL ;
    PORT
      LAYER M3 ;
        RECT  64.008 86.256 64.026 86.4 ;
    END
  END xg[174]
  PIN xg[175]
    DIRECTION OUTPUT ;
    USE SIGNAL ;
    PORT
      LAYER M5 ;
        RECT  64.032 86.208 64.056 86.4 ;
    END
  END xg[175]
  PIN xg[176]
    DIRECTION OUTPUT ;
    USE SIGNAL ;
    PORT
      LAYER M3 ;
        RECT  64.152 86.256 64.17 86.4 ;
    END
  END xg[176]
  PIN xg[177]
    DIRECTION OUTPUT ;
    USE SIGNAL ;
    PORT
      LAYER M5 ;
        RECT  64.176 86.208 64.2 86.4 ;
    END
  END xg[177]
  PIN xg[178]
    DIRECTION OUTPUT ;
    USE SIGNAL ;
    PORT
      LAYER M3 ;
        RECT  64.296 86.256 64.314 86.4 ;
    END
  END xg[178]
  PIN xg[179]
    DIRECTION OUTPUT ;
    USE SIGNAL ;
    PORT
      LAYER M5 ;
        RECT  64.32 86.208 64.344 86.4 ;
    END
  END xg[179]
  PIN xg[17]
    DIRECTION OUTPUT ;
    USE SIGNAL ;
    PORT
      LAYER M5 ;
        RECT  52.656 86.208 52.68 86.4 ;
    END
  END xg[17]
  PIN xg[180]
    DIRECTION OUTPUT ;
    USE SIGNAL ;
    PORT
      LAYER M3 ;
        RECT  64.44 86.256 64.458 86.4 ;
    END
  END xg[180]
  PIN xg[181]
    DIRECTION OUTPUT ;
    USE SIGNAL ;
    PORT
      LAYER M5 ;
        RECT  64.464 86.208 64.488 86.4 ;
    END
  END xg[181]
  PIN xg[182]
    DIRECTION OUTPUT ;
    USE SIGNAL ;
    PORT
      LAYER M3 ;
        RECT  64.584 86.256 64.602 86.4 ;
    END
  END xg[182]
  PIN xg[183]
    DIRECTION OUTPUT ;
    USE SIGNAL ;
    PORT
      LAYER M5 ;
        RECT  64.608 86.208 64.632 86.4 ;
    END
  END xg[183]
  PIN xg[184]
    DIRECTION OUTPUT ;
    USE SIGNAL ;
    PORT
      LAYER M3 ;
        RECT  64.728 86.256 64.746 86.4 ;
    END
  END xg[184]
  PIN xg[185]
    DIRECTION OUTPUT ;
    USE SIGNAL ;
    PORT
      LAYER M5 ;
        RECT  64.752 86.208 64.776 86.4 ;
    END
  END xg[185]
  PIN xg[186]
    DIRECTION OUTPUT ;
    USE SIGNAL ;
    PORT
      LAYER M3 ;
        RECT  64.872 86.256 64.89 86.4 ;
    END
  END xg[186]
  PIN xg[187]
    DIRECTION OUTPUT ;
    USE SIGNAL ;
    PORT
      LAYER M5 ;
        RECT  64.896 86.208 64.92 86.4 ;
    END
  END xg[187]
  PIN xg[188]
    DIRECTION OUTPUT ;
    USE SIGNAL ;
    PORT
      LAYER M3 ;
        RECT  65.016 86.256 65.034 86.4 ;
    END
  END xg[188]
  PIN xg[189]
    DIRECTION OUTPUT ;
    USE SIGNAL ;
    PORT
      LAYER M5 ;
        RECT  65.04 86.208 65.064 86.4 ;
    END
  END xg[189]
  PIN xg[18]
    DIRECTION OUTPUT ;
    USE SIGNAL ;
    PORT
      LAYER M3 ;
        RECT  52.776 86.256 52.794 86.4 ;
    END
  END xg[18]
  PIN xg[190]
    DIRECTION OUTPUT ;
    USE SIGNAL ;
    PORT
      LAYER M3 ;
        RECT  65.16 86.256 65.178 86.4 ;
    END
  END xg[190]
  PIN xg[191]
    DIRECTION OUTPUT ;
    USE SIGNAL ;
    PORT
      LAYER M5 ;
        RECT  65.184 86.208 65.208 86.4 ;
    END
  END xg[191]
  PIN xg[192]
    DIRECTION OUTPUT ;
    USE SIGNAL ;
    PORT
      LAYER M3 ;
        RECT  65.304 86.256 65.322 86.4 ;
    END
  END xg[192]
  PIN xg[193]
    DIRECTION OUTPUT ;
    USE SIGNAL ;
    PORT
      LAYER M5 ;
        RECT  65.328 86.208 65.352 86.4 ;
    END
  END xg[193]
  PIN xg[194]
    DIRECTION OUTPUT ;
    USE SIGNAL ;
    PORT
      LAYER M3 ;
        RECT  65.448 86.256 65.466 86.4 ;
    END
  END xg[194]
  PIN xg[195]
    DIRECTION OUTPUT ;
    USE SIGNAL ;
    PORT
      LAYER M5 ;
        RECT  65.472 86.208 65.496 86.4 ;
    END
  END xg[195]
  PIN xg[196]
    DIRECTION OUTPUT ;
    USE SIGNAL ;
    PORT
      LAYER M3 ;
        RECT  65.592 86.256 65.61 86.4 ;
    END
  END xg[196]
  PIN xg[197]
    DIRECTION OUTPUT ;
    USE SIGNAL ;
    PORT
      LAYER M5 ;
        RECT  65.616 86.208 65.64 86.4 ;
    END
  END xg[197]
  PIN xg[198]
    DIRECTION OUTPUT ;
    USE SIGNAL ;
    PORT
      LAYER M3 ;
        RECT  65.736 86.256 65.754 86.4 ;
    END
  END xg[198]
  PIN xg[199]
    DIRECTION OUTPUT ;
    USE SIGNAL ;
    PORT
      LAYER M5 ;
        RECT  65.76 86.208 65.784 86.4 ;
    END
  END xg[199]
  PIN xg[19]
    DIRECTION OUTPUT ;
    USE SIGNAL ;
    PORT
      LAYER M5 ;
        RECT  52.8 86.208 52.824 86.4 ;
    END
  END xg[19]
  PIN xg[1]
    DIRECTION OUTPUT ;
    USE SIGNAL ;
    PORT
      LAYER M5 ;
        RECT  51.504 86.208 51.528 86.4 ;
    END
  END xg[1]
  PIN xg[200]
    DIRECTION OUTPUT ;
    USE SIGNAL ;
    PORT
      LAYER M3 ;
        RECT  65.88 86.256 65.898 86.4 ;
    END
  END xg[200]
  PIN xg[201]
    DIRECTION OUTPUT ;
    USE SIGNAL ;
    PORT
      LAYER M5 ;
        RECT  65.904 86.208 65.928 86.4 ;
    END
  END xg[201]
  PIN xg[202]
    DIRECTION OUTPUT ;
    USE SIGNAL ;
    PORT
      LAYER M3 ;
        RECT  66.024 86.256 66.042 86.4 ;
    END
  END xg[202]
  PIN xg[203]
    DIRECTION OUTPUT ;
    USE SIGNAL ;
    PORT
      LAYER M5 ;
        RECT  66.048 86.208 66.072 86.4 ;
    END
  END xg[203]
  PIN xg[204]
    DIRECTION OUTPUT ;
    USE SIGNAL ;
    PORT
      LAYER M3 ;
        RECT  66.168 86.256 66.186 86.4 ;
    END
  END xg[204]
  PIN xg[205]
    DIRECTION OUTPUT ;
    USE SIGNAL ;
    PORT
      LAYER M5 ;
        RECT  66.192 86.208 66.216 86.4 ;
    END
  END xg[205]
  PIN xg[206]
    DIRECTION OUTPUT ;
    USE SIGNAL ;
    PORT
      LAYER M3 ;
        RECT  66.312 86.256 66.33 86.4 ;
    END
  END xg[206]
  PIN xg[207]
    DIRECTION OUTPUT ;
    USE SIGNAL ;
    PORT
      LAYER M5 ;
        RECT  66.336 86.208 66.36 86.4 ;
    END
  END xg[207]
  PIN xg[208]
    DIRECTION OUTPUT ;
    USE SIGNAL ;
    PORT
      LAYER M3 ;
        RECT  66.456 86.256 66.474 86.4 ;
    END
  END xg[208]
  PIN xg[209]
    DIRECTION OUTPUT ;
    USE SIGNAL ;
    PORT
      LAYER M5 ;
        RECT  66.48 86.208 66.504 86.4 ;
    END
  END xg[209]
  PIN xg[20]
    DIRECTION OUTPUT ;
    USE SIGNAL ;
    PORT
      LAYER M3 ;
        RECT  52.92 86.256 52.938 86.4 ;
    END
  END xg[20]
  PIN xg[210]
    DIRECTION OUTPUT ;
    USE SIGNAL ;
    PORT
      LAYER M3 ;
        RECT  66.6 86.256 66.618 86.4 ;
    END
  END xg[210]
  PIN xg[211]
    DIRECTION OUTPUT ;
    USE SIGNAL ;
    PORT
      LAYER M5 ;
        RECT  66.624 86.208 66.648 86.4 ;
    END
  END xg[211]
  PIN xg[212]
    DIRECTION OUTPUT ;
    USE SIGNAL ;
    PORT
      LAYER M3 ;
        RECT  66.744 86.256 66.762 86.4 ;
    END
  END xg[212]
  PIN xg[213]
    DIRECTION OUTPUT ;
    USE SIGNAL ;
    PORT
      LAYER M5 ;
        RECT  66.768 86.208 66.792 86.4 ;
    END
  END xg[213]
  PIN xg[214]
    DIRECTION OUTPUT ;
    USE SIGNAL ;
    PORT
      LAYER M3 ;
        RECT  66.888 86.256 66.906 86.4 ;
    END
  END xg[214]
  PIN xg[215]
    DIRECTION OUTPUT ;
    USE SIGNAL ;
    PORT
      LAYER M5 ;
        RECT  66.912 86.208 66.936 86.4 ;
    END
  END xg[215]
  PIN xg[216]
    DIRECTION OUTPUT ;
    USE SIGNAL ;
    PORT
      LAYER M3 ;
        RECT  67.032 86.256 67.05 86.4 ;
    END
  END xg[216]
  PIN xg[217]
    DIRECTION OUTPUT ;
    USE SIGNAL ;
    PORT
      LAYER M5 ;
        RECT  67.056 86.208 67.08 86.4 ;
    END
  END xg[217]
  PIN xg[218]
    DIRECTION OUTPUT ;
    USE SIGNAL ;
    PORT
      LAYER M3 ;
        RECT  67.176 86.256 67.194 86.4 ;
    END
  END xg[218]
  PIN xg[219]
    DIRECTION OUTPUT ;
    USE SIGNAL ;
    PORT
      LAYER M5 ;
        RECT  67.2 86.208 67.224 86.4 ;
    END
  END xg[219]
  PIN xg[21]
    DIRECTION OUTPUT ;
    USE SIGNAL ;
    PORT
      LAYER M5 ;
        RECT  52.944 86.208 52.968 86.4 ;
    END
  END xg[21]
  PIN xg[220]
    DIRECTION OUTPUT ;
    USE SIGNAL ;
    PORT
      LAYER M3 ;
        RECT  67.32 86.256 67.338 86.4 ;
    END
  END xg[220]
  PIN xg[221]
    DIRECTION OUTPUT ;
    USE SIGNAL ;
    PORT
      LAYER M5 ;
        RECT  67.344 86.208 67.368 86.4 ;
    END
  END xg[221]
  PIN xg[222]
    DIRECTION OUTPUT ;
    USE SIGNAL ;
    PORT
      LAYER M3 ;
        RECT  67.464 86.256 67.482 86.4 ;
    END
  END xg[222]
  PIN xg[223]
    DIRECTION OUTPUT ;
    USE SIGNAL ;
    PORT
      LAYER M5 ;
        RECT  67.488 86.208 67.512 86.4 ;
    END
  END xg[223]
  PIN xg[224]
    DIRECTION OUTPUT ;
    USE SIGNAL ;
    PORT
      LAYER M3 ;
        RECT  67.608 86.256 67.626 86.4 ;
    END
  END xg[224]
  PIN xg[225]
    DIRECTION OUTPUT ;
    USE SIGNAL ;
    PORT
      LAYER M5 ;
        RECT  67.632 86.208 67.656 86.4 ;
    END
  END xg[225]
  PIN xg[226]
    DIRECTION OUTPUT ;
    USE SIGNAL ;
    PORT
      LAYER M3 ;
        RECT  67.752 86.256 67.77 86.4 ;
    END
  END xg[226]
  PIN xg[227]
    DIRECTION OUTPUT ;
    USE SIGNAL ;
    PORT
      LAYER M5 ;
        RECT  67.776 86.208 67.8 86.4 ;
    END
  END xg[227]
  PIN xg[228]
    DIRECTION OUTPUT ;
    USE SIGNAL ;
    PORT
      LAYER M3 ;
        RECT  67.896 86.256 67.914 86.4 ;
    END
  END xg[228]
  PIN xg[229]
    DIRECTION OUTPUT ;
    USE SIGNAL ;
    PORT
      LAYER M5 ;
        RECT  67.92 86.208 67.944 86.4 ;
    END
  END xg[229]
  PIN xg[22]
    DIRECTION OUTPUT ;
    USE SIGNAL ;
    PORT
      LAYER M3 ;
        RECT  53.064 86.256 53.082 86.4 ;
    END
  END xg[22]
  PIN xg[230]
    DIRECTION OUTPUT ;
    USE SIGNAL ;
    PORT
      LAYER M3 ;
        RECT  68.04 86.256 68.058 86.4 ;
    END
  END xg[230]
  PIN xg[231]
    DIRECTION OUTPUT ;
    USE SIGNAL ;
    PORT
      LAYER M5 ;
        RECT  68.064 86.208 68.088 86.4 ;
    END
  END xg[231]
  PIN xg[232]
    DIRECTION OUTPUT ;
    USE SIGNAL ;
    PORT
      LAYER M3 ;
        RECT  68.184 86.256 68.202 86.4 ;
    END
  END xg[232]
  PIN xg[233]
    DIRECTION OUTPUT ;
    USE SIGNAL ;
    PORT
      LAYER M5 ;
        RECT  68.208 86.208 68.232 86.4 ;
    END
  END xg[233]
  PIN xg[234]
    DIRECTION OUTPUT ;
    USE SIGNAL ;
    PORT
      LAYER M3 ;
        RECT  68.328 86.256 68.346 86.4 ;
    END
  END xg[234]
  PIN xg[235]
    DIRECTION OUTPUT ;
    USE SIGNAL ;
    PORT
      LAYER M5 ;
        RECT  68.352 86.208 68.376 86.4 ;
    END
  END xg[235]
  PIN xg[236]
    DIRECTION OUTPUT ;
    USE SIGNAL ;
    PORT
      LAYER M3 ;
        RECT  68.472 86.256 68.49 86.4 ;
    END
  END xg[236]
  PIN xg[237]
    DIRECTION OUTPUT ;
    USE SIGNAL ;
    PORT
      LAYER M5 ;
        RECT  68.496 86.208 68.52 86.4 ;
    END
  END xg[237]
  PIN xg[238]
    DIRECTION OUTPUT ;
    USE SIGNAL ;
    PORT
      LAYER M3 ;
        RECT  68.616 86.256 68.634 86.4 ;
    END
  END xg[238]
  PIN xg[239]
    DIRECTION OUTPUT ;
    USE SIGNAL ;
    PORT
      LAYER M5 ;
        RECT  68.64 86.208 68.664 86.4 ;
    END
  END xg[239]
  PIN xg[23]
    DIRECTION OUTPUT ;
    USE SIGNAL ;
    PORT
      LAYER M5 ;
        RECT  53.088 86.208 53.112 86.4 ;
    END
  END xg[23]
  PIN xg[240]
    DIRECTION OUTPUT ;
    USE SIGNAL ;
    PORT
      LAYER M3 ;
        RECT  68.76 86.256 68.778 86.4 ;
    END
  END xg[240]
  PIN xg[241]
    DIRECTION OUTPUT ;
    USE SIGNAL ;
    PORT
      LAYER M5 ;
        RECT  68.784 86.208 68.808 86.4 ;
    END
  END xg[241]
  PIN xg[242]
    DIRECTION OUTPUT ;
    USE SIGNAL ;
    PORT
      LAYER M3 ;
        RECT  68.904 86.256 68.922 86.4 ;
    END
  END xg[242]
  PIN xg[243]
    DIRECTION OUTPUT ;
    USE SIGNAL ;
    PORT
      LAYER M5 ;
        RECT  68.928 86.208 68.952 86.4 ;
    END
  END xg[243]
  PIN xg[244]
    DIRECTION OUTPUT ;
    USE SIGNAL ;
    PORT
      LAYER M3 ;
        RECT  69.048 86.256 69.066 86.4 ;
    END
  END xg[244]
  PIN xg[245]
    DIRECTION OUTPUT ;
    USE SIGNAL ;
    PORT
      LAYER M5 ;
        RECT  69.072 86.208 69.096 86.4 ;
    END
  END xg[245]
  PIN xg[246]
    DIRECTION OUTPUT ;
    USE SIGNAL ;
    PORT
      LAYER M3 ;
        RECT  69.192 86.256 69.21 86.4 ;
    END
  END xg[246]
  PIN xg[247]
    DIRECTION OUTPUT ;
    USE SIGNAL ;
    PORT
      LAYER M5 ;
        RECT  69.216 86.208 69.24 86.4 ;
    END
  END xg[247]
  PIN xg[248]
    DIRECTION OUTPUT ;
    USE SIGNAL ;
    PORT
      LAYER M3 ;
        RECT  69.336 86.256 69.354 86.4 ;
    END
  END xg[248]
  PIN xg[249]
    DIRECTION OUTPUT ;
    USE SIGNAL ;
    PORT
      LAYER M5 ;
        RECT  69.36 86.208 69.384 86.4 ;
    END
  END xg[249]
  PIN xg[24]
    DIRECTION OUTPUT ;
    USE SIGNAL ;
    PORT
      LAYER M3 ;
        RECT  53.208 86.256 53.226 86.4 ;
    END
  END xg[24]
  PIN xg[250]
    DIRECTION OUTPUT ;
    USE SIGNAL ;
    PORT
      LAYER M3 ;
        RECT  69.48 86.256 69.498 86.4 ;
    END
  END xg[250]
  PIN xg[251]
    DIRECTION OUTPUT ;
    USE SIGNAL ;
    PORT
      LAYER M5 ;
        RECT  69.504 86.208 69.528 86.4 ;
    END
  END xg[251]
  PIN xg[252]
    DIRECTION OUTPUT ;
    USE SIGNAL ;
    PORT
      LAYER M3 ;
        RECT  69.624 86.256 69.642 86.4 ;
    END
  END xg[252]
  PIN xg[253]
    DIRECTION OUTPUT ;
    USE SIGNAL ;
    PORT
      LAYER M5 ;
        RECT  69.648 86.208 69.672 86.4 ;
    END
  END xg[253]
  PIN xg[254]
    DIRECTION OUTPUT ;
    USE SIGNAL ;
    PORT
      LAYER M3 ;
        RECT  69.768 86.256 69.786 86.4 ;
    END
  END xg[254]
  PIN xg[255]
    DIRECTION OUTPUT ;
    USE SIGNAL ;
    PORT
      LAYER M5 ;
        RECT  69.792 86.208 69.816 86.4 ;
    END
  END xg[255]
  PIN xg[25]
    DIRECTION OUTPUT ;
    USE SIGNAL ;
    PORT
      LAYER M5 ;
        RECT  53.232 86.208 53.256 86.4 ;
    END
  END xg[25]
  PIN xg[26]
    DIRECTION OUTPUT ;
    USE SIGNAL ;
    PORT
      LAYER M3 ;
        RECT  53.352 86.256 53.37 86.4 ;
    END
  END xg[26]
  PIN xg[27]
    DIRECTION OUTPUT ;
    USE SIGNAL ;
    PORT
      LAYER M5 ;
        RECT  53.376 86.208 53.4 86.4 ;
    END
  END xg[27]
  PIN xg[28]
    DIRECTION OUTPUT ;
    USE SIGNAL ;
    PORT
      LAYER M3 ;
        RECT  53.496 86.256 53.514 86.4 ;
    END
  END xg[28]
  PIN xg[29]
    DIRECTION OUTPUT ;
    USE SIGNAL ;
    PORT
      LAYER M5 ;
        RECT  53.52 86.208 53.544 86.4 ;
    END
  END xg[29]
  PIN xg[2]
    DIRECTION OUTPUT ;
    USE SIGNAL ;
    PORT
      LAYER M3 ;
        RECT  51.624 86.256 51.642 86.4 ;
    END
  END xg[2]
  PIN xg[30]
    DIRECTION OUTPUT ;
    USE SIGNAL ;
    PORT
      LAYER M3 ;
        RECT  53.64 86.256 53.658 86.4 ;
    END
  END xg[30]
  PIN xg[31]
    DIRECTION OUTPUT ;
    USE SIGNAL ;
    PORT
      LAYER M5 ;
        RECT  53.664 86.208 53.688 86.4 ;
    END
  END xg[31]
  PIN xg[32]
    DIRECTION OUTPUT ;
    USE SIGNAL ;
    PORT
      LAYER M3 ;
        RECT  53.784 86.256 53.802 86.4 ;
    END
  END xg[32]
  PIN xg[33]
    DIRECTION OUTPUT ;
    USE SIGNAL ;
    PORT
      LAYER M5 ;
        RECT  53.808 86.208 53.832 86.4 ;
    END
  END xg[33]
  PIN xg[34]
    DIRECTION OUTPUT ;
    USE SIGNAL ;
    PORT
      LAYER M3 ;
        RECT  53.928 86.256 53.946 86.4 ;
    END
  END xg[34]
  PIN xg[35]
    DIRECTION OUTPUT ;
    USE SIGNAL ;
    PORT
      LAYER M5 ;
        RECT  53.952 86.208 53.976 86.4 ;
    END
  END xg[35]
  PIN xg[36]
    DIRECTION OUTPUT ;
    USE SIGNAL ;
    PORT
      LAYER M3 ;
        RECT  54.072 86.256 54.09 86.4 ;
    END
  END xg[36]
  PIN xg[37]
    DIRECTION OUTPUT ;
    USE SIGNAL ;
    PORT
      LAYER M5 ;
        RECT  54.096 86.208 54.12 86.4 ;
    END
  END xg[37]
  PIN xg[38]
    DIRECTION OUTPUT ;
    USE SIGNAL ;
    PORT
      LAYER M3 ;
        RECT  54.216 86.256 54.234 86.4 ;
    END
  END xg[38]
  PIN xg[39]
    DIRECTION OUTPUT ;
    USE SIGNAL ;
    PORT
      LAYER M5 ;
        RECT  54.24 86.208 54.264 86.4 ;
    END
  END xg[39]
  PIN xg[3]
    DIRECTION OUTPUT ;
    USE SIGNAL ;
    PORT
      LAYER M5 ;
        RECT  51.648 86.208 51.672 86.4 ;
    END
  END xg[3]
  PIN xg[40]
    DIRECTION OUTPUT ;
    USE SIGNAL ;
    PORT
      LAYER M3 ;
        RECT  54.36 86.256 54.378 86.4 ;
    END
  END xg[40]
  PIN xg[41]
    DIRECTION OUTPUT ;
    USE SIGNAL ;
    PORT
      LAYER M5 ;
        RECT  54.384 86.208 54.408 86.4 ;
    END
  END xg[41]
  PIN xg[42]
    DIRECTION OUTPUT ;
    USE SIGNAL ;
    PORT
      LAYER M3 ;
        RECT  54.504 86.256 54.522 86.4 ;
    END
  END xg[42]
  PIN xg[43]
    DIRECTION OUTPUT ;
    USE SIGNAL ;
    PORT
      LAYER M5 ;
        RECT  54.528 86.208 54.552 86.4 ;
    END
  END xg[43]
  PIN xg[44]
    DIRECTION OUTPUT ;
    USE SIGNAL ;
    PORT
      LAYER M3 ;
        RECT  54.648 86.256 54.666 86.4 ;
    END
  END xg[44]
  PIN xg[45]
    DIRECTION OUTPUT ;
    USE SIGNAL ;
    PORT
      LAYER M5 ;
        RECT  54.672 86.208 54.696 86.4 ;
    END
  END xg[45]
  PIN xg[46]
    DIRECTION OUTPUT ;
    USE SIGNAL ;
    PORT
      LAYER M3 ;
        RECT  54.792 86.256 54.81 86.4 ;
    END
  END xg[46]
  PIN xg[47]
    DIRECTION OUTPUT ;
    USE SIGNAL ;
    PORT
      LAYER M5 ;
        RECT  54.816 86.208 54.84 86.4 ;
    END
  END xg[47]
  PIN xg[48]
    DIRECTION OUTPUT ;
    USE SIGNAL ;
    PORT
      LAYER M3 ;
        RECT  54.936 86.256 54.954 86.4 ;
    END
  END xg[48]
  PIN xg[49]
    DIRECTION OUTPUT ;
    USE SIGNAL ;
    PORT
      LAYER M5 ;
        RECT  54.96 86.208 54.984 86.4 ;
    END
  END xg[49]
  PIN xg[4]
    DIRECTION OUTPUT ;
    USE SIGNAL ;
    PORT
      LAYER M3 ;
        RECT  51.768 86.256 51.786 86.4 ;
    END
  END xg[4]
  PIN xg[50]
    DIRECTION OUTPUT ;
    USE SIGNAL ;
    PORT
      LAYER M3 ;
        RECT  55.08 86.256 55.098 86.4 ;
    END
  END xg[50]
  PIN xg[51]
    DIRECTION OUTPUT ;
    USE SIGNAL ;
    PORT
      LAYER M5 ;
        RECT  55.104 86.208 55.128 86.4 ;
    END
  END xg[51]
  PIN xg[52]
    DIRECTION OUTPUT ;
    USE SIGNAL ;
    PORT
      LAYER M3 ;
        RECT  55.224 86.256 55.242 86.4 ;
    END
  END xg[52]
  PIN xg[53]
    DIRECTION OUTPUT ;
    USE SIGNAL ;
    PORT
      LAYER M5 ;
        RECT  55.248 86.208 55.272 86.4 ;
    END
  END xg[53]
  PIN xg[54]
    DIRECTION OUTPUT ;
    USE SIGNAL ;
    PORT
      LAYER M3 ;
        RECT  55.368 86.256 55.386 86.4 ;
    END
  END xg[54]
  PIN xg[55]
    DIRECTION OUTPUT ;
    USE SIGNAL ;
    PORT
      LAYER M5 ;
        RECT  55.392 86.208 55.416 86.4 ;
    END
  END xg[55]
  PIN xg[56]
    DIRECTION OUTPUT ;
    USE SIGNAL ;
    PORT
      LAYER M3 ;
        RECT  55.512 86.256 55.53 86.4 ;
    END
  END xg[56]
  PIN xg[57]
    DIRECTION OUTPUT ;
    USE SIGNAL ;
    PORT
      LAYER M5 ;
        RECT  55.536 86.208 55.56 86.4 ;
    END
  END xg[57]
  PIN xg[58]
    DIRECTION OUTPUT ;
    USE SIGNAL ;
    PORT
      LAYER M3 ;
        RECT  55.656 86.256 55.674 86.4 ;
    END
  END xg[58]
  PIN xg[59]
    DIRECTION OUTPUT ;
    USE SIGNAL ;
    PORT
      LAYER M5 ;
        RECT  55.68 86.208 55.704 86.4 ;
    END
  END xg[59]
  PIN xg[5]
    DIRECTION OUTPUT ;
    USE SIGNAL ;
    PORT
      LAYER M5 ;
        RECT  51.792 86.208 51.816 86.4 ;
    END
  END xg[5]
  PIN xg[60]
    DIRECTION OUTPUT ;
    USE SIGNAL ;
    PORT
      LAYER M3 ;
        RECT  55.8 86.256 55.818 86.4 ;
    END
  END xg[60]
  PIN xg[61]
    DIRECTION OUTPUT ;
    USE SIGNAL ;
    PORT
      LAYER M5 ;
        RECT  55.824 86.208 55.848 86.4 ;
    END
  END xg[61]
  PIN xg[62]
    DIRECTION OUTPUT ;
    USE SIGNAL ;
    PORT
      LAYER M3 ;
        RECT  55.944 86.256 55.962 86.4 ;
    END
  END xg[62]
  PIN xg[63]
    DIRECTION OUTPUT ;
    USE SIGNAL ;
    PORT
      LAYER M5 ;
        RECT  55.968 86.208 55.992 86.4 ;
    END
  END xg[63]
  PIN xg[64]
    DIRECTION OUTPUT ;
    USE SIGNAL ;
    PORT
      LAYER M3 ;
        RECT  56.088 86.256 56.106 86.4 ;
    END
  END xg[64]
  PIN xg[65]
    DIRECTION OUTPUT ;
    USE SIGNAL ;
    PORT
      LAYER M5 ;
        RECT  56.112 86.208 56.136 86.4 ;
    END
  END xg[65]
  PIN xg[66]
    DIRECTION OUTPUT ;
    USE SIGNAL ;
    PORT
      LAYER M3 ;
        RECT  56.232 86.256 56.25 86.4 ;
    END
  END xg[66]
  PIN xg[67]
    DIRECTION OUTPUT ;
    USE SIGNAL ;
    PORT
      LAYER M5 ;
        RECT  56.256 86.208 56.28 86.4 ;
    END
  END xg[67]
  PIN xg[68]
    DIRECTION OUTPUT ;
    USE SIGNAL ;
    PORT
      LAYER M3 ;
        RECT  56.376 86.256 56.394 86.4 ;
    END
  END xg[68]
  PIN xg[69]
    DIRECTION OUTPUT ;
    USE SIGNAL ;
    PORT
      LAYER M5 ;
        RECT  56.4 86.208 56.424 86.4 ;
    END
  END xg[69]
  PIN xg[6]
    DIRECTION OUTPUT ;
    USE SIGNAL ;
    PORT
      LAYER M3 ;
        RECT  51.912 86.256 51.93 86.4 ;
    END
  END xg[6]
  PIN xg[70]
    DIRECTION OUTPUT ;
    USE SIGNAL ;
    PORT
      LAYER M3 ;
        RECT  56.52 86.256 56.538 86.4 ;
    END
  END xg[70]
  PIN xg[71]
    DIRECTION OUTPUT ;
    USE SIGNAL ;
    PORT
      LAYER M5 ;
        RECT  56.544 86.208 56.568 86.4 ;
    END
  END xg[71]
  PIN xg[72]
    DIRECTION OUTPUT ;
    USE SIGNAL ;
    PORT
      LAYER M3 ;
        RECT  56.664 86.256 56.682 86.4 ;
    END
  END xg[72]
  PIN xg[73]
    DIRECTION OUTPUT ;
    USE SIGNAL ;
    PORT
      LAYER M5 ;
        RECT  56.688 86.208 56.712 86.4 ;
    END
  END xg[73]
  PIN xg[74]
    DIRECTION OUTPUT ;
    USE SIGNAL ;
    PORT
      LAYER M3 ;
        RECT  56.808 86.256 56.826 86.4 ;
    END
  END xg[74]
  PIN xg[75]
    DIRECTION OUTPUT ;
    USE SIGNAL ;
    PORT
      LAYER M5 ;
        RECT  56.832 86.208 56.856 86.4 ;
    END
  END xg[75]
  PIN xg[76]
    DIRECTION OUTPUT ;
    USE SIGNAL ;
    PORT
      LAYER M3 ;
        RECT  56.952 86.256 56.97 86.4 ;
    END
  END xg[76]
  PIN xg[77]
    DIRECTION OUTPUT ;
    USE SIGNAL ;
    PORT
      LAYER M5 ;
        RECT  56.976 86.208 57 86.4 ;
    END
  END xg[77]
  PIN xg[78]
    DIRECTION OUTPUT ;
    USE SIGNAL ;
    PORT
      LAYER M3 ;
        RECT  57.096 86.256 57.114 86.4 ;
    END
  END xg[78]
  PIN xg[79]
    DIRECTION OUTPUT ;
    USE SIGNAL ;
    PORT
      LAYER M5 ;
        RECT  57.12 86.208 57.144 86.4 ;
    END
  END xg[79]
  PIN xg[7]
    DIRECTION OUTPUT ;
    USE SIGNAL ;
    PORT
      LAYER M5 ;
        RECT  51.936 86.208 51.96 86.4 ;
    END
  END xg[7]
  PIN xg[80]
    DIRECTION OUTPUT ;
    USE SIGNAL ;
    PORT
      LAYER M3 ;
        RECT  57.24 86.256 57.258 86.4 ;
    END
  END xg[80]
  PIN xg[81]
    DIRECTION OUTPUT ;
    USE SIGNAL ;
    PORT
      LAYER M5 ;
        RECT  57.264 86.208 57.288 86.4 ;
    END
  END xg[81]
  PIN xg[82]
    DIRECTION OUTPUT ;
    USE SIGNAL ;
    PORT
      LAYER M3 ;
        RECT  57.384 86.256 57.402 86.4 ;
    END
  END xg[82]
  PIN xg[83]
    DIRECTION OUTPUT ;
    USE SIGNAL ;
    PORT
      LAYER M5 ;
        RECT  57.408 86.208 57.432 86.4 ;
    END
  END xg[83]
  PIN xg[84]
    DIRECTION OUTPUT ;
    USE SIGNAL ;
    PORT
      LAYER M3 ;
        RECT  57.528 86.256 57.546 86.4 ;
    END
  END xg[84]
  PIN xg[85]
    DIRECTION OUTPUT ;
    USE SIGNAL ;
    PORT
      LAYER M5 ;
        RECT  57.552 86.208 57.576 86.4 ;
    END
  END xg[85]
  PIN xg[86]
    DIRECTION OUTPUT ;
    USE SIGNAL ;
    PORT
      LAYER M3 ;
        RECT  57.672 86.256 57.69 86.4 ;
    END
  END xg[86]
  PIN xg[87]
    DIRECTION OUTPUT ;
    USE SIGNAL ;
    PORT
      LAYER M5 ;
        RECT  57.696 86.208 57.72 86.4 ;
    END
  END xg[87]
  PIN xg[88]
    DIRECTION OUTPUT ;
    USE SIGNAL ;
    PORT
      LAYER M3 ;
        RECT  57.816 86.256 57.834 86.4 ;
    END
  END xg[88]
  PIN xg[89]
    DIRECTION OUTPUT ;
    USE SIGNAL ;
    PORT
      LAYER M5 ;
        RECT  57.84 86.208 57.864 86.4 ;
    END
  END xg[89]
  PIN xg[8]
    DIRECTION OUTPUT ;
    USE SIGNAL ;
    PORT
      LAYER M3 ;
        RECT  52.056 86.256 52.074 86.4 ;
    END
  END xg[8]
  PIN xg[90]
    DIRECTION OUTPUT ;
    USE SIGNAL ;
    PORT
      LAYER M3 ;
        RECT  57.96 86.256 57.978 86.4 ;
    END
  END xg[90]
  PIN xg[91]
    DIRECTION OUTPUT ;
    USE SIGNAL ;
    PORT
      LAYER M5 ;
        RECT  57.984 86.208 58.008 86.4 ;
    END
  END xg[91]
  PIN xg[92]
    DIRECTION OUTPUT ;
    USE SIGNAL ;
    PORT
      LAYER M3 ;
        RECT  58.104 86.256 58.122 86.4 ;
    END
  END xg[92]
  PIN xg[93]
    DIRECTION OUTPUT ;
    USE SIGNAL ;
    PORT
      LAYER M5 ;
        RECT  58.128 86.208 58.152 86.4 ;
    END
  END xg[93]
  PIN xg[94]
    DIRECTION OUTPUT ;
    USE SIGNAL ;
    PORT
      LAYER M3 ;
        RECT  58.248 86.256 58.266 86.4 ;
    END
  END xg[94]
  PIN xg[95]
    DIRECTION OUTPUT ;
    USE SIGNAL ;
    PORT
      LAYER M5 ;
        RECT  58.272 86.208 58.296 86.4 ;
    END
  END xg[95]
  PIN xg[96]
    DIRECTION OUTPUT ;
    USE SIGNAL ;
    PORT
      LAYER M3 ;
        RECT  58.392 86.256 58.41 86.4 ;
    END
  END xg[96]
  PIN xg[97]
    DIRECTION OUTPUT ;
    USE SIGNAL ;
    PORT
      LAYER M5 ;
        RECT  58.416 86.208 58.44 86.4 ;
    END
  END xg[97]
  PIN xg[98]
    DIRECTION OUTPUT ;
    USE SIGNAL ;
    PORT
      LAYER M3 ;
        RECT  58.536 86.256 58.554 86.4 ;
    END
  END xg[98]
  PIN xg[99]
    DIRECTION OUTPUT ;
    USE SIGNAL ;
    PORT
      LAYER M5 ;
        RECT  58.56 86.208 58.584 86.4 ;
    END
  END xg[99]
  PIN xg[9]
    DIRECTION OUTPUT ;
    USE SIGNAL ;
    PORT
      LAYER M5 ;
        RECT  52.08 86.208 52.104 86.4 ;
    END
  END xg[9]
  PIN VDD
    DIRECTION INOUT ;
    USE POWER ;
    PORT
      LAYER M5 ;
        RECT  137.592 2.151 137.712 84.249 ;
        RECT  132.192 2.151 132.312 84.249 ;
        RECT  126.792 2.151 126.912 84.249 ;
        RECT  121.392 2.151 121.512 84.249 ;
        RECT  115.992 2.151 116.112 84.249 ;
        RECT  110.592 2.151 110.712 84.249 ;
        RECT  105.192 2.151 105.312 84.249 ;
        RECT  99.792 2.151 99.912 84.249 ;
        RECT  94.392 2.151 94.512 84.249 ;
        RECT  88.992 2.151 89.112 84.249 ;
        RECT  83.592 2.151 83.712 84.249 ;
        RECT  78.192 2.151 78.312 84.249 ;
        RECT  72.792 2.151 72.912 84.249 ;
        RECT  67.392 2.151 67.512 84.249 ;
        RECT  61.992 2.151 62.112 84.249 ;
        RECT  56.592 2.151 56.712 84.249 ;
        RECT  51.192 2.151 51.312 84.249 ;
        RECT  45.792 2.151 45.912 84.249 ;
        RECT  40.392 2.151 40.512 84.249 ;
        RECT  34.992 2.151 35.112 84.249 ;
        RECT  29.592 2.151 29.712 84.249 ;
        RECT  24.192 2.151 24.312 84.249 ;
        RECT  18.792 2.151 18.912 84.249 ;
        RECT  13.392 2.151 13.512 84.249 ;
        RECT  7.992 2.151 8.112 84.249 ;
        RECT  2.592 2.151 2.712 84.249 ;
    END
  END VDD
  PIN VSS
    DIRECTION INOUT ;
    USE GROUND ;
    PORT
      LAYER M5 ;
        RECT  137.4 2.137 137.52 84.263 ;
        RECT  132 2.137 132.12 84.263 ;
        RECT  126.6 2.137 126.72 84.263 ;
        RECT  121.2 2.137 121.32 84.263 ;
        RECT  115.8 2.137 115.92 84.263 ;
        RECT  110.4 2.137 110.52 84.263 ;
        RECT  105 2.137 105.12 84.263 ;
        RECT  99.6 2.137 99.72 84.263 ;
        RECT  94.2 2.137 94.32 84.263 ;
        RECT  88.8 2.137 88.92 84.263 ;
        RECT  83.4 2.137 83.52 84.263 ;
        RECT  78 2.137 78.12 84.263 ;
        RECT  72.6 2.137 72.72 84.263 ;
        RECT  67.2 2.137 67.32 84.263 ;
        RECT  61.8 2.137 61.92 84.263 ;
        RECT  56.4 2.137 56.52 84.263 ;
        RECT  51 2.137 51.12 84.263 ;
        RECT  45.6 2.137 45.72 84.263 ;
        RECT  40.2 2.137 40.32 84.263 ;
        RECT  34.8 2.137 34.92 84.263 ;
        RECT  29.4 2.137 29.52 84.263 ;
        RECT  24 2.137 24.12 84.263 ;
        RECT  18.6 2.137 18.72 84.263 ;
        RECT  13.2 2.137 13.32 84.263 ;
        RECT  7.8 2.137 7.92 84.263 ;
        RECT  2.4 2.137 2.52 84.263 ;
    END
  END VSS
  # OT_OBS_CLOSED layer=M5 d_um=1.536 added=124
  OBS
    LAYER RVTN ;
     RECT  2.16 2.16 140.4 2.295 ;
     RECT  2.16 2.565 140.4 2.835 ;
     RECT  2.16 3.105 140.4 3.375 ;
     RECT  2.16 3.645 140.4 3.915 ;
     RECT  2.16 4.185 140.4 4.455 ;
     RECT  2.16 4.725 140.4 4.995 ;
     RECT  2.16 5.265 140.4 5.535 ;
     RECT  2.16 5.805 140.4 6.075 ;
     RECT  2.16 6.345 140.4 6.615 ;
     RECT  2.16 6.885 140.4 7.155 ;
     RECT  2.16 7.425 140.4 7.695 ;
     RECT  2.16 7.965 140.4 8.235 ;
     RECT  2.16 8.505 140.4 8.775 ;
     RECT  2.16 9.045 140.4 9.315 ;
     RECT  2.16 9.585 140.4 9.855 ;
     RECT  2.16 10.125 140.4 10.395 ;
     RECT  2.16 10.665 140.4 10.935 ;
     RECT  2.16 11.205 140.4 11.475 ;
     RECT  2.16 11.745 140.4 12.015 ;
     RECT  2.16 12.285 140.4 12.555 ;
     RECT  2.16 12.825 140.4 13.095 ;
     RECT  2.16 13.365 140.4 13.635 ;
     RECT  2.16 13.905 140.4 14.175 ;
     RECT  2.16 14.445 140.4 14.715 ;
     RECT  2.16 14.985 140.4 15.255 ;
     RECT  2.16 15.525 140.4 15.795 ;
     RECT  2.16 16.065 140.4 16.335 ;
     RECT  2.16 16.605 140.4 16.875 ;
     RECT  2.16 17.145 140.4 17.415 ;
     RECT  2.16 17.685 140.4 17.955 ;
     RECT  2.16 18.225 140.4 18.495 ;
     RECT  2.16 18.765 140.4 19.035 ;
     RECT  2.16 19.305 140.4 19.575 ;
     RECT  2.16 19.845 140.4 20.115 ;
     RECT  2.16 20.385 20.412 20.655 ;
     RECT  119.34 20.385 140.4 20.655 ;
     RECT  2.16 20.925 20.412 21.195 ;
     RECT  119.34 20.925 140.4 21.195 ;
     RECT  2.16 21.465 20.412 21.735 ;
     RECT  119.34 21.465 140.4 21.735 ;
     RECT  2.16 22.005 20.412 22.275 ;
     RECT  119.34 22.005 140.4 22.275 ;
     RECT  2.16 22.545 20.412 22.815 ;
     RECT  119.34 22.545 140.4 22.815 ;
     RECT  2.16 23.085 20.412 23.355 ;
     RECT  119.34 23.085 140.4 23.355 ;
     RECT  2.16 23.625 20.412 23.895 ;
     RECT  119.34 23.625 140.4 23.895 ;
     RECT  2.16 24.165 20.412 24.435 ;
     RECT  119.34 24.165 140.4 24.435 ;
     RECT  2.16 24.705 20.412 24.975 ;
     RECT  119.34 24.705 140.4 24.975 ;
     RECT  2.16 25.245 20.412 25.515 ;
     RECT  119.34 25.245 140.4 25.515 ;
     RECT  2.16 25.785 20.412 26.055 ;
     RECT  119.34 25.785 140.4 26.055 ;
     RECT  2.16 26.325 20.412 26.595 ;
     RECT  119.34 26.325 140.4 26.595 ;
     RECT  2.16 26.865 20.412 27.135 ;
     RECT  119.34 26.865 140.4 27.135 ;
     RECT  2.16 27.405 20.412 27.675 ;
     RECT  119.34 27.405 140.4 27.675 ;
     RECT  2.16 27.945 20.412 28.215 ;
     RECT  119.34 27.945 140.4 28.215 ;
     RECT  2.16 28.485 20.412 28.755 ;
     RECT  119.34 28.485 140.4 28.755 ;
     RECT  2.16 29.025 20.412 29.295 ;
     RECT  119.34 29.025 140.4 29.295 ;
     RECT  2.16 29.565 20.412 29.835 ;
     RECT  119.34 29.565 140.4 29.835 ;
     RECT  2.16 30.105 20.412 30.375 ;
     RECT  119.34 30.105 140.4 30.375 ;
     RECT  2.16 30.645 20.412 30.915 ;
     RECT  119.34 30.645 140.4 30.915 ;
     RECT  2.16 31.185 20.412 31.455 ;
     RECT  119.34 31.185 140.4 31.455 ;
     RECT  2.16 31.725 20.412 31.995 ;
     RECT  119.34 31.725 140.4 31.995 ;
     RECT  2.16 32.265 20.412 32.535 ;
     RECT  119.34 32.265 140.4 32.535 ;
     RECT  2.16 32.805 20.412 33.075 ;
     RECT  119.34 32.805 140.4 33.075 ;
     RECT  2.16 33.345 20.412 33.615 ;
     RECT  119.34 33.345 140.4 33.615 ;
     RECT  2.16 33.885 20.412 34.155 ;
     RECT  119.34 33.885 140.4 34.155 ;
     RECT  2.16 34.425 20.412 34.695 ;
     RECT  119.34 34.425 140.4 34.695 ;
     RECT  2.16 34.965 20.412 35.235 ;
     RECT  119.34 34.965 140.4 35.235 ;
     RECT  2.16 35.505 20.412 35.775 ;
     RECT  119.34 35.505 140.4 35.775 ;
     RECT  2.16 36.045 20.412 36.315 ;
     RECT  119.34 36.045 140.4 36.315 ;
     RECT  2.16 36.585 20.412 36.855 ;
     RECT  119.34 36.585 140.4 36.855 ;
     RECT  2.16 37.125 20.412 37.395 ;
     RECT  119.34 37.125 140.4 37.395 ;
     RECT  2.16 37.665 20.412 37.935 ;
     RECT  119.34 37.665 140.4 37.935 ;
     RECT  2.16 38.205 20.412 38.475 ;
     RECT  119.34 38.205 140.4 38.475 ;
     RECT  2.16 38.745 20.412 39.015 ;
     RECT  119.34 38.745 140.4 39.015 ;
     RECT  2.16 39.285 20.412 39.555 ;
     RECT  119.34 39.285 140.4 39.555 ;
     RECT  2.16 39.825 20.412 40.095 ;
     RECT  119.34 39.825 140.4 40.095 ;
     RECT  2.16 40.365 20.412 40.635 ;
     RECT  119.34 40.365 140.4 40.635 ;
     RECT  2.16 40.905 20.412 41.175 ;
     RECT  119.34 40.905 140.4 41.175 ;
     RECT  2.16 41.445 20.412 41.715 ;
     RECT  119.34 41.445 140.4 41.715 ;
     RECT  2.16 41.985 20.412 42.255 ;
     RECT  119.34 41.985 140.4 42.255 ;
     RECT  2.16 42.525 20.412 42.795 ;
     RECT  119.34 42.525 140.4 42.795 ;
     RECT  2.16 43.065 20.412 43.335 ;
     RECT  119.34 43.065 140.4 43.335 ;
     RECT  2.16 43.605 20.412 43.875 ;
     RECT  119.34 43.605 140.4 43.875 ;
     RECT  2.16 44.145 20.412 44.415 ;
     RECT  119.34 44.145 140.4 44.415 ;
     RECT  2.16 44.685 20.412 44.955 ;
     RECT  119.34 44.685 140.4 44.955 ;
     RECT  2.16 45.225 20.412 45.495 ;
     RECT  119.34 45.225 140.4 45.495 ;
     RECT  2.16 45.765 20.412 46.035 ;
     RECT  119.34 45.765 140.4 46.035 ;
     RECT  2.16 46.305 20.412 46.575 ;
     RECT  119.34 46.305 140.4 46.575 ;
     RECT  2.16 46.845 20.412 47.115 ;
     RECT  119.34 46.845 140.4 47.115 ;
     RECT  2.16 47.385 20.412 47.655 ;
     RECT  119.34 47.385 140.4 47.655 ;
     RECT  2.16 47.925 20.412 48.195 ;
     RECT  119.34 47.925 140.4 48.195 ;
     RECT  2.16 48.465 20.412 48.735 ;
     RECT  119.34 48.465 140.4 48.735 ;
     RECT  2.16 49.005 20.412 49.275 ;
     RECT  119.34 49.005 140.4 49.275 ;
     RECT  2.16 49.545 20.412 49.815 ;
     RECT  119.34 49.545 140.4 49.815 ;
     RECT  2.16 50.085 20.412 50.355 ;
     RECT  119.34 50.085 140.4 50.355 ;
     RECT  2.16 50.625 20.412 50.895 ;
     RECT  119.34 50.625 140.4 50.895 ;
     RECT  2.16 51.165 20.412 51.435 ;
     RECT  119.34 51.165 140.4 51.435 ;
     RECT  2.16 51.705 20.412 51.975 ;
     RECT  119.34 51.705 140.4 51.975 ;
     RECT  2.16 52.245 20.412 52.515 ;
     RECT  119.34 52.245 140.4 52.515 ;
     RECT  2.16 52.785 20.412 53.055 ;
     RECT  119.34 52.785 140.4 53.055 ;
     RECT  2.16 53.325 20.412 53.595 ;
     RECT  119.34 53.325 140.4 53.595 ;
     RECT  2.16 53.865 20.412 54.135 ;
     RECT  119.34 53.865 140.4 54.135 ;
     RECT  2.16 54.405 20.412 54.675 ;
     RECT  119.34 54.405 140.4 54.675 ;
     RECT  2.16 54.945 20.412 55.215 ;
     RECT  119.34 54.945 140.4 55.215 ;
     RECT  2.16 55.485 20.412 55.755 ;
     RECT  119.34 55.485 140.4 55.755 ;
     RECT  2.16 56.025 20.412 56.295 ;
     RECT  119.34 56.025 140.4 56.295 ;
     RECT  2.16 56.565 20.412 56.835 ;
     RECT  119.34 56.565 140.4 56.835 ;
     RECT  2.16 57.105 20.412 57.375 ;
     RECT  119.34 57.105 140.4 57.375 ;
     RECT  2.16 57.645 20.412 57.915 ;
     RECT  119.34 57.645 140.4 57.915 ;
     RECT  2.16 58.185 20.412 58.455 ;
     RECT  119.34 58.185 140.4 58.455 ;
     RECT  2.16 58.725 20.412 58.995 ;
     RECT  119.34 58.725 140.4 58.995 ;
     RECT  2.16 59.265 20.412 59.535 ;
     RECT  119.34 59.265 140.4 59.535 ;
     RECT  2.16 59.805 20.412 60.075 ;
     RECT  119.34 59.805 140.4 60.075 ;
     RECT  2.16 60.345 20.412 60.615 ;
     RECT  119.34 60.345 140.4 60.615 ;
     RECT  2.16 60.885 20.412 61.155 ;
     RECT  119.34 60.885 140.4 61.155 ;
     RECT  2.16 61.425 20.412 61.695 ;
     RECT  119.34 61.425 140.4 61.695 ;
     RECT  2.16 61.965 20.412 62.235 ;
     RECT  119.34 61.965 140.4 62.235 ;
     RECT  2.16 62.505 20.412 62.775 ;
     RECT  119.34 62.505 140.4 62.775 ;
     RECT  2.16 63.045 20.412 63.315 ;
     RECT  119.34 63.045 140.4 63.315 ;
     RECT  2.16 63.585 20.412 63.855 ;
     RECT  119.34 63.585 140.4 63.855 ;
     RECT  2.16 64.125 20.412 64.395 ;
     RECT  119.34 64.125 140.4 64.395 ;
     RECT  2.16 64.665 20.412 64.935 ;
     RECT  119.34 64.665 140.4 64.935 ;
     RECT  2.16 65.205 20.412 65.475 ;
     RECT  119.34 65.205 140.4 65.475 ;
     RECT  2.16 65.745 140.4 66.015 ;
     RECT  2.16 66.285 140.4 66.555 ;
     RECT  2.16 66.825 140.4 67.095 ;
     RECT  2.16 67.365 140.4 67.635 ;
     RECT  2.16 67.905 140.4 68.175 ;
     RECT  2.16 68.445 140.4 68.715 ;
     RECT  2.16 68.985 140.4 69.255 ;
     RECT  2.16 69.525 140.4 69.795 ;
     RECT  2.16 70.065 140.4 70.335 ;
     RECT  2.16 70.605 140.4 70.875 ;
     RECT  2.16 71.145 140.4 71.415 ;
     RECT  2.16 71.685 140.4 71.955 ;
     RECT  2.16 72.225 140.4 72.495 ;
     RECT  2.16 72.765 140.4 73.035 ;
     RECT  2.16 73.305 140.4 73.575 ;
     RECT  2.16 73.845 140.4 74.115 ;
     RECT  2.16 74.385 140.4 74.655 ;
     RECT  2.16 74.925 140.4 75.195 ;
     RECT  2.16 75.465 140.4 75.735 ;
     RECT  2.16 76.005 140.4 76.275 ;
     RECT  2.16 76.545 140.4 76.815 ;
     RECT  2.16 77.085 140.4 77.355 ;
     RECT  2.16 77.625 140.4 77.895 ;
     RECT  2.16 78.165 140.4 78.435 ;
     RECT  2.16 78.705 140.4 78.975 ;
     RECT  2.16 79.245 140.4 79.515 ;
     RECT  2.16 79.785 140.4 80.055 ;
     RECT  2.16 80.325 140.4 80.595 ;
     RECT  2.16 80.865 140.4 81.135 ;
     RECT  2.16 81.405 140.4 81.675 ;
     RECT  2.16 81.945 140.4 82.215 ;
     RECT  2.16 82.485 140.4 82.755 ;
     RECT  2.16 83.025 140.4 83.295 ;
     RECT  2.16 83.565 140.4 83.835 ;
     RECT  2.16 84.105 140.4 84.24 ;
    LAYER RVTP ;
     RECT  2.16 2.295 140.4 2.565 ;
     RECT  2.16 2.835 140.4 3.105 ;
     RECT  2.16 3.375 140.4 3.645 ;
     RECT  2.16 3.915 140.4 4.185 ;
     RECT  2.16 4.455 140.4 4.725 ;
     RECT  2.16 4.995 140.4 5.265 ;
     RECT  2.16 5.535 140.4 5.805 ;
     RECT  2.16 6.075 140.4 6.345 ;
     RECT  2.16 6.615 140.4 6.885 ;
     RECT  2.16 7.155 140.4 7.425 ;
     RECT  2.16 7.695 140.4 7.965 ;
     RECT  2.16 8.235 140.4 8.505 ;
     RECT  2.16 8.775 140.4 9.045 ;
     RECT  2.16 9.315 140.4 9.585 ;
     RECT  2.16 9.855 140.4 10.125 ;
     RECT  2.16 10.395 140.4 10.665 ;
     RECT  2.16 10.935 140.4 11.205 ;
     RECT  2.16 11.475 140.4 11.745 ;
     RECT  2.16 12.015 140.4 12.285 ;
     RECT  2.16 12.555 140.4 12.825 ;
     RECT  2.16 13.095 140.4 13.365 ;
     RECT  2.16 13.635 140.4 13.905 ;
     RECT  2.16 14.175 140.4 14.445 ;
     RECT  2.16 14.715 140.4 14.985 ;
     RECT  2.16 15.255 140.4 15.525 ;
     RECT  2.16 15.795 140.4 16.065 ;
     RECT  2.16 16.335 140.4 16.605 ;
     RECT  2.16 16.875 140.4 17.145 ;
     RECT  2.16 17.415 140.4 17.685 ;
     RECT  2.16 17.955 140.4 18.225 ;
     RECT  2.16 18.495 140.4 18.765 ;
     RECT  2.16 19.035 140.4 19.305 ;
     RECT  2.16 19.575 140.4 19.845 ;
     RECT  2.16 20.115 140.4 20.25 ;
     RECT  2.16 20.25 20.412 20.385 ;
     RECT  119.34 20.25 140.4 20.385 ;
     RECT  2.16 20.655 20.412 20.925 ;
     RECT  119.34 20.655 140.4 20.925 ;
     RECT  2.16 21.195 20.412 21.465 ;
     RECT  119.34 21.195 140.4 21.465 ;
     RECT  2.16 21.735 20.412 22.005 ;
     RECT  119.34 21.735 140.4 22.005 ;
     RECT  2.16 22.275 20.412 22.545 ;
     RECT  119.34 22.275 140.4 22.545 ;
     RECT  2.16 22.815 20.412 23.085 ;
     RECT  119.34 22.815 140.4 23.085 ;
     RECT  2.16 23.355 20.412 23.625 ;
     RECT  119.34 23.355 140.4 23.625 ;
     RECT  2.16 23.895 20.412 24.165 ;
     RECT  119.34 23.895 140.4 24.165 ;
     RECT  2.16 24.435 20.412 24.705 ;
     RECT  119.34 24.435 140.4 24.705 ;
     RECT  2.16 24.975 20.412 25.245 ;
     RECT  119.34 24.975 140.4 25.245 ;
     RECT  2.16 25.515 20.412 25.785 ;
     RECT  119.34 25.515 140.4 25.785 ;
     RECT  2.16 26.055 20.412 26.325 ;
     RECT  119.34 26.055 140.4 26.325 ;
     RECT  2.16 26.595 20.412 26.865 ;
     RECT  119.34 26.595 140.4 26.865 ;
     RECT  2.16 27.135 20.412 27.405 ;
     RECT  119.34 27.135 140.4 27.405 ;
     RECT  2.16 27.675 20.412 27.945 ;
     RECT  119.34 27.675 140.4 27.945 ;
     RECT  2.16 28.215 20.412 28.485 ;
     RECT  119.34 28.215 140.4 28.485 ;
     RECT  2.16 28.755 20.412 29.025 ;
     RECT  119.34 28.755 140.4 29.025 ;
     RECT  2.16 29.295 20.412 29.565 ;
     RECT  119.34 29.295 140.4 29.565 ;
     RECT  2.16 29.835 20.412 30.105 ;
     RECT  119.34 29.835 140.4 30.105 ;
     RECT  2.16 30.375 20.412 30.645 ;
     RECT  119.34 30.375 140.4 30.645 ;
     RECT  2.16 30.915 20.412 31.185 ;
     RECT  119.34 30.915 140.4 31.185 ;
     RECT  2.16 31.455 20.412 31.725 ;
     RECT  119.34 31.455 140.4 31.725 ;
     RECT  2.16 31.995 20.412 32.265 ;
     RECT  119.34 31.995 140.4 32.265 ;
     RECT  2.16 32.535 20.412 32.805 ;
     RECT  119.34 32.535 140.4 32.805 ;
     RECT  2.16 33.075 20.412 33.345 ;
     RECT  119.34 33.075 140.4 33.345 ;
     RECT  2.16 33.615 20.412 33.885 ;
     RECT  119.34 33.615 140.4 33.885 ;
     RECT  2.16 34.155 20.412 34.425 ;
     RECT  119.34 34.155 140.4 34.425 ;
     RECT  2.16 34.695 20.412 34.965 ;
     RECT  119.34 34.695 140.4 34.965 ;
     RECT  2.16 35.235 20.412 35.505 ;
     RECT  119.34 35.235 140.4 35.505 ;
     RECT  2.16 35.775 20.412 36.045 ;
     RECT  119.34 35.775 140.4 36.045 ;
     RECT  2.16 36.315 20.412 36.585 ;
     RECT  119.34 36.315 140.4 36.585 ;
     RECT  2.16 36.855 20.412 37.125 ;
     RECT  119.34 36.855 140.4 37.125 ;
     RECT  2.16 37.395 20.412 37.665 ;
     RECT  119.34 37.395 140.4 37.665 ;
     RECT  2.16 37.935 20.412 38.205 ;
     RECT  119.34 37.935 140.4 38.205 ;
     RECT  2.16 38.475 20.412 38.745 ;
     RECT  119.34 38.475 140.4 38.745 ;
     RECT  2.16 39.015 20.412 39.285 ;
     RECT  119.34 39.015 140.4 39.285 ;
     RECT  2.16 39.555 20.412 39.825 ;
     RECT  119.34 39.555 140.4 39.825 ;
     RECT  2.16 40.095 20.412 40.365 ;
     RECT  119.34 40.095 140.4 40.365 ;
     RECT  2.16 40.635 20.412 40.905 ;
     RECT  119.34 40.635 140.4 40.905 ;
     RECT  2.16 41.175 20.412 41.445 ;
     RECT  119.34 41.175 140.4 41.445 ;
     RECT  2.16 41.715 20.412 41.985 ;
     RECT  119.34 41.715 140.4 41.985 ;
     RECT  2.16 42.255 20.412 42.525 ;
     RECT  119.34 42.255 140.4 42.525 ;
     RECT  2.16 42.795 20.412 43.065 ;
     RECT  119.34 42.795 140.4 43.065 ;
     RECT  2.16 43.335 20.412 43.605 ;
     RECT  119.34 43.335 140.4 43.605 ;
     RECT  2.16 43.875 20.412 44.145 ;
     RECT  119.34 43.875 140.4 44.145 ;
     RECT  2.16 44.415 20.412 44.685 ;
     RECT  119.34 44.415 140.4 44.685 ;
     RECT  2.16 44.955 20.412 45.225 ;
     RECT  119.34 44.955 140.4 45.225 ;
     RECT  2.16 45.495 20.412 45.765 ;
     RECT  119.34 45.495 140.4 45.765 ;
     RECT  2.16 46.035 20.412 46.305 ;
     RECT  119.34 46.035 140.4 46.305 ;
     RECT  2.16 46.575 20.412 46.845 ;
     RECT  119.34 46.575 140.4 46.845 ;
     RECT  2.16 47.115 20.412 47.385 ;
     RECT  119.34 47.115 140.4 47.385 ;
     RECT  2.16 47.655 20.412 47.925 ;
     RECT  119.34 47.655 140.4 47.925 ;
     RECT  2.16 48.195 20.412 48.465 ;
     RECT  119.34 48.195 140.4 48.465 ;
     RECT  2.16 48.735 20.412 49.005 ;
     RECT  119.34 48.735 140.4 49.005 ;
     RECT  2.16 49.275 20.412 49.545 ;
     RECT  119.34 49.275 140.4 49.545 ;
     RECT  2.16 49.815 20.412 50.085 ;
     RECT  119.34 49.815 140.4 50.085 ;
     RECT  2.16 50.355 20.412 50.625 ;
     RECT  119.34 50.355 140.4 50.625 ;
     RECT  2.16 50.895 20.412 51.165 ;
     RECT  119.34 50.895 140.4 51.165 ;
     RECT  2.16 51.435 20.412 51.705 ;
     RECT  119.34 51.435 140.4 51.705 ;
     RECT  2.16 51.975 20.412 52.245 ;
     RECT  119.34 51.975 140.4 52.245 ;
     RECT  2.16 52.515 20.412 52.785 ;
     RECT  119.34 52.515 140.4 52.785 ;
     RECT  2.16 53.055 20.412 53.325 ;
     RECT  119.34 53.055 140.4 53.325 ;
     RECT  2.16 53.595 20.412 53.865 ;
     RECT  119.34 53.595 140.4 53.865 ;
     RECT  2.16 54.135 20.412 54.405 ;
     RECT  119.34 54.135 140.4 54.405 ;
     RECT  2.16 54.675 20.412 54.945 ;
     RECT  119.34 54.675 140.4 54.945 ;
     RECT  2.16 55.215 20.412 55.485 ;
     RECT  119.34 55.215 140.4 55.485 ;
     RECT  2.16 55.755 20.412 56.025 ;
     RECT  119.34 55.755 140.4 56.025 ;
     RECT  2.16 56.295 20.412 56.565 ;
     RECT  119.34 56.295 140.4 56.565 ;
     RECT  2.16 56.835 20.412 57.105 ;
     RECT  119.34 56.835 140.4 57.105 ;
     RECT  2.16 57.375 20.412 57.645 ;
     RECT  119.34 57.375 140.4 57.645 ;
     RECT  2.16 57.915 20.412 58.185 ;
     RECT  119.34 57.915 140.4 58.185 ;
     RECT  2.16 58.455 20.412 58.725 ;
     RECT  119.34 58.455 140.4 58.725 ;
     RECT  2.16 58.995 20.412 59.265 ;
     RECT  119.34 58.995 140.4 59.265 ;
     RECT  2.16 59.535 20.412 59.805 ;
     RECT  119.34 59.535 140.4 59.805 ;
     RECT  2.16 60.075 20.412 60.345 ;
     RECT  119.34 60.075 140.4 60.345 ;
     RECT  2.16 60.615 20.412 60.885 ;
     RECT  119.34 60.615 140.4 60.885 ;
     RECT  2.16 61.155 20.412 61.425 ;
     RECT  119.34 61.155 140.4 61.425 ;
     RECT  2.16 61.695 20.412 61.965 ;
     RECT  119.34 61.695 140.4 61.965 ;
     RECT  2.16 62.235 20.412 62.505 ;
     RECT  119.34 62.235 140.4 62.505 ;
     RECT  2.16 62.775 20.412 63.045 ;
     RECT  119.34 62.775 140.4 63.045 ;
     RECT  2.16 63.315 20.412 63.585 ;
     RECT  119.34 63.315 140.4 63.585 ;
     RECT  2.16 63.855 20.412 64.125 ;
     RECT  119.34 63.855 140.4 64.125 ;
     RECT  2.16 64.395 20.412 64.665 ;
     RECT  119.34 64.395 140.4 64.665 ;
     RECT  2.16 64.935 20.412 65.205 ;
     RECT  119.34 64.935 140.4 65.205 ;
     RECT  2.16 65.475 20.412 65.61 ;
     RECT  119.34 65.475 140.4 65.61 ;
     RECT  2.16 65.61 140.4 65.745 ;
     RECT  2.16 66.015 140.4 66.285 ;
     RECT  2.16 66.555 140.4 66.825 ;
     RECT  2.16 67.095 140.4 67.365 ;
     RECT  2.16 67.635 140.4 67.905 ;
     RECT  2.16 68.175 140.4 68.445 ;
     RECT  2.16 68.715 140.4 68.985 ;
     RECT  2.16 69.255 140.4 69.525 ;
     RECT  2.16 69.795 140.4 70.065 ;
     RECT  2.16 70.335 140.4 70.605 ;
     RECT  2.16 70.875 140.4 71.145 ;
     RECT  2.16 71.415 140.4 71.685 ;
     RECT  2.16 71.955 140.4 72.225 ;
     RECT  2.16 72.495 140.4 72.765 ;
     RECT  2.16 73.035 140.4 73.305 ;
     RECT  2.16 73.575 140.4 73.845 ;
     RECT  2.16 74.115 140.4 74.385 ;
     RECT  2.16 74.655 140.4 74.925 ;
     RECT  2.16 75.195 140.4 75.465 ;
     RECT  2.16 75.735 140.4 76.005 ;
     RECT  2.16 76.275 140.4 76.545 ;
     RECT  2.16 76.815 140.4 77.085 ;
     RECT  2.16 77.355 140.4 77.625 ;
     RECT  2.16 77.895 140.4 78.165 ;
     RECT  2.16 78.435 140.4 78.705 ;
     RECT  2.16 78.975 140.4 79.245 ;
     RECT  2.16 79.515 140.4 79.785 ;
     RECT  2.16 80.055 140.4 80.325 ;
     RECT  2.16 80.595 140.4 80.865 ;
     RECT  2.16 81.135 140.4 81.405 ;
     RECT  2.16 81.675 140.4 81.945 ;
     RECT  2.16 82.215 140.4 82.485 ;
     RECT  2.16 82.755 140.4 83.025 ;
     RECT  2.16 83.295 140.4 83.565 ;
     RECT  2.16 83.835 140.4 84.105 ;
    LAYER M1 ;
     RECT  2.16 2.151 140.4 20.259 ;
     RECT  22.464 22.464 117.288 63.528 ;
     RECT  2.16 20.259 20.412 65.601 ;
     RECT  119.34 20.259 140.4 65.601 ;
     RECT  2.16 65.601 140.4 84.249 ;
    LAYER M2 ;
     RECT  0.211 42.732 2.16 42.75 ;
     RECT  2.16 2.151 20.412 84.249 ;
     RECT  20.412 34.362 20.471 38.772 ;
     RECT  20.412 54.612 20.471 54.864 ;
     RECT  20.412 45 20.579 47.682 ;
     RECT  20.412 42.336 20.687 42.75 ;
     RECT  20.579 45 20.723 46.179 ;
     RECT  20.579 47.16 20.723 47.682 ;
     RECT  20.723 47.241 20.903 47.682 ;
     RECT  20.412 27.918 20.939 29.088 ;
     RECT  20.412 30.384 20.975 33.606 ;
     RECT  20.471 34.362 20.975 38.502 ;
     RECT  20.471 54.648 20.975 54.864 ;
     RECT  20.412 62.586 21.011 84.249 ;
     RECT  20.939 27.918 21.047 27.936 ;
     RECT  20.975 30.456 21.047 33.606 ;
     RECT  20.975 35.172 21.083 38.502 ;
     RECT  20.903 47.592 21.083 47.682 ;
     RECT  20.412 59.004 21.083 60.804 ;
     RECT  21.011 62.676 21.083 84.249 ;
     RECT  21.047 30.924 21.155 33.606 ;
     RECT  21.155 31.122 21.191 33.606 ;
     RECT  21.083 60.354 21.199 60.804 ;
     RECT  21.199 60.354 21.263 61.074 ;
     RECT  20.939 29.07 21.271 29.088 ;
     RECT  20.412 26.802 21.299 26.82 ;
     RECT  20.687 42.336 21.299 42.516 ;
     RECT  21.083 35.514 21.335 38.502 ;
     RECT  21.271 29.07 21.443 29.169 ;
     RECT  21.335 35.514 21.443 35.532 ;
     RECT  21.335 36.558 21.479 38.502 ;
     RECT  21.479 36.558 21.515 38.124 ;
     RECT  21.263 60.66 21.523 61.074 ;
     RECT  20.412 56.916 21.595 58.14 ;
     RECT  21.443 29.07 21.623 29.088 ;
     RECT  20.975 54.846 21.623 54.864 ;
     RECT  21.523 60.66 21.623 61.146 ;
     RECT  21.191 31.122 21.695 32.904 ;
     RECT  20.412 24.516 21.731 24.534 ;
     RECT  20.975 34.362 21.731 34.38 ;
     RECT  21.515 36.558 21.731 37.35 ;
     RECT  21.595 56.421 21.731 58.14 ;
     RECT  20.412 48.672 21.775 48.69 ;
     RECT  22.063 53.946 22.135 53.964 ;
     RECT  21.775 28.611 22.243 28.629 ;
     RECT  20.412 2.151 22.464 23.148 ;
     RECT  22.243 28.53 22.464 28.629 ;
     RECT  21.695 31.122 22.464 31.716 ;
     RECT  21.695 32.508 22.464 32.904 ;
     RECT  22.279 34.74 22.464 34.758 ;
     RECT  21.731 37.026 22.464 37.35 ;
     RECT  21.515 38.106 22.464 38.124 ;
     RECT  22.279 38.952 22.464 38.97 ;
     RECT  21.299 42.336 22.464 42.444 ;
     RECT  21.775 44.541 22.464 44.559 ;
     RECT  20.723 45.621 22.464 45.639 ;
     RECT  21.775 48.672 22.464 49.104 ;
     RECT  22.135 52.992 22.464 53.01 ;
     RECT  22.135 53.874 22.464 53.964 ;
     RECT  21.731 56.421 22.464 57.672 ;
     RECT  21.623 60.66 22.464 60.984 ;
     RECT  21.083 63.288 22.464 84.249 ;
     RECT  22.464 2.151 22.855 84.249 ;
     RECT  22.855 2.151 22.999 84.294 ;
     RECT  22.999 2.151 24.511 84.33 ;
     RECT  24.511 2.151 25.087 84.366 ;
     RECT  25.087 2.151 25.187 84.906 ;
     RECT  24.727 0.144 25.951 0.162 ;
     RECT  25.187 2.151 26.455 84.366 ;
     RECT  25.951 0.144 26.743 0.234 ;
     RECT  26.455 2.151 27.491 84.906 ;
     RECT  27.787 85.581 27.923 85.599 ;
     RECT  26.743 0.144 27.931 0.279 ;
     RECT  27.931 0.144 28.103 0.324 ;
     RECT  28.103 0.144 28.319 0.234 ;
     RECT  27.491 2.151 28.507 84.366 ;
     RECT  28.507 2.151 28.939 84.474 ;
     RECT  28.939 2.151 29.083 84.834 ;
     RECT  29.299 0.144 29.371 0.162 ;
     RECT  29.371 0.144 31.127 0.324 ;
     RECT  29.083 2.151 31.423 84.906 ;
     RECT  31.127 0.144 31.487 0.279 ;
     RECT  31.487 0.144 31.919 0.234 ;
     RECT  31.423 1.728 31.991 84.906 ;
     RECT  31.991 2.151 32.819 84.906 ;
     RECT  32.755 0.144 33.115 0.162 ;
     RECT  32.819 2.151 33.691 84.249 ;
     RECT  33.691 2.151 33.791 84.906 ;
     RECT  33.835 85.581 33.871 85.599 ;
     RECT  33.187 1.152 33.979 1.17 ;
     RECT  33.115 0.144 34.007 0.324 ;
     RECT  33.871 85.581 34.007 85.68 ;
     RECT  33.979 1.152 34.151 1.359 ;
     RECT  34.151 1.152 34.187 1.314 ;
     RECT  33.791 2.151 34.519 84.834 ;
     RECT  34.519 2.151 34.691 84.906 ;
     RECT  34.007 0.144 34.843 0.162 ;
     RECT  34.187 1.152 34.987 1.17 ;
     RECT  34.843 0.144 35.015 0.324 ;
     RECT  34.987 1.152 35.231 1.359 ;
     RECT  35.231 1.26 35.303 1.359 ;
     RECT  35.303 1.26 35.339 1.278 ;
     RECT  34.691 2.151 36.067 84.87 ;
     RECT  36.067 2.151 36.139 84.906 ;
     RECT  35.995 1.152 36.283 1.17 ;
     RECT  36.283 1.152 36.347 1.242 ;
     RECT  36.347 1.224 36.419 1.242 ;
     RECT  36.139 2.151 36.419 85.059 ;
     RECT  36.419 2.151 38.335 84.906 ;
     RECT  38.335 2.106 38.443 84.906 ;
     RECT  38.443 2.106 38.687 85.599 ;
     RECT  38.687 2.151 38.723 85.599 ;
     RECT  35.015 0.144 39.055 0.162 ;
     RECT  38.723 2.151 39.119 85.059 ;
     RECT  39.055 0.144 39.191 0.234 ;
     RECT  39.119 2.151 39.299 84.906 ;
     RECT  39.299 2.151 40.099 84.249 ;
     RECT  40.099 2.151 40.315 84.906 ;
     RECT  40.315 1.728 40.415 84.906 ;
     RECT  39.191 0.144 40.603 0.162 ;
     RECT  40.603 0.144 41.323 0.198 ;
     RECT  40.415 2.151 41.467 84.906 ;
     RECT  41.323 0.144 41.531 0.279 ;
     RECT  41.467 2.151 41.567 85.059 ;
     RECT  41.567 2.151 42.143 84.474 ;
     RECT  41.531 0.144 42.467 0.234 ;
     RECT  42.467 0.216 42.503 0.234 ;
     RECT  42.143 2.151 44.123 84.33 ;
     RECT  44.123 2.151 44.411 84.294 ;
     RECT  44.411 2.151 51.259 84.249 ;
     RECT  51.259 2.151 51.935 84.366 ;
     RECT  51.727 85.581 52.267 85.599 ;
     RECT  51.935 2.151 52.511 84.294 ;
     RECT  52.267 85.5 52.655 85.599 ;
     RECT  52.655 85.581 52.943 85.599 ;
     RECT  52.511 2.151 54.607 84.249 ;
     RECT  54.607 2.151 56.399 84.906 ;
     RECT  56.399 2.151 56.975 84.87 ;
     RECT  56.975 2.151 57.803 84.249 ;
     RECT  57.739 85.581 57.983 85.599 ;
     RECT  57.803 65.25 58.315 84.249 ;
     RECT  58.243 85.041 58.315 85.059 ;
     RECT  58.315 65.25 58.343 85.059 ;
     RECT  58.343 65.25 60.611 84.906 ;
     RECT  60.611 65.331 60.691 84.906 ;
     RECT  60.691 65.331 60.791 85.059 ;
     RECT  60.791 65.331 61.511 84.906 ;
     RECT  61.555 86.238 61.591 86.256 ;
     RECT  61.591 86.238 61.691 86.328 ;
     RECT  61.511 65.331 61.871 84.33 ;
     RECT  61.871 65.331 62.599 84.249 ;
     RECT  62.599 65.331 62.879 84.906 ;
     RECT  62.879 65.331 63.859 84.249 ;
     RECT  63.859 65.331 64.247 84.906 ;
     RECT  64.579 85.041 64.679 85.059 ;
     RECT  64.247 65.331 65.011 84.249 ;
     RECT  65.011 65.331 67.595 84.906 ;
     RECT  67.595 65.601 67.603 84.906 ;
     RECT  67.603 65.601 67.775 85.599 ;
     RECT  67.775 85.581 67.811 85.599 ;
     RECT  67.775 65.601 68.611 84.564 ;
     RECT  68.611 65.601 68.747 84.906 ;
     RECT  68.747 65.601 69.503 84.402 ;
     RECT  69.503 65.601 71.663 84.366 ;
     RECT  57.803 2.151 117.288 64.494 ;
     RECT  117.288 2.151 117.383 22.419 ;
     RECT  117.288 27.216 117.419 27.234 ;
     RECT  117.383 2.151 118.103 22.032 ;
     RECT  118.103 2.151 118.139 21.996 ;
     RECT  117.288 34.668 118.579 39.312 ;
     RECT  117.288 42.336 118.579 42.354 ;
     RECT  117.288 44.082 118.579 44.1 ;
     RECT  118.579 42.192 118.607 42.354 ;
     RECT  118.579 34.47 119.083 39.312 ;
     RECT  118.579 44.082 119.119 44.37 ;
     RECT  118.139 2.151 119.34 21.96 ;
     RECT  119.083 34.47 119.34 39.888 ;
     RECT  117.288 40.644 119.34 41.238 ;
     RECT  118.607 42.192 119.34 42.21 ;
     RECT  118.579 43.272 119.34 43.29 ;
     RECT  119.119 44.046 119.34 44.37 ;
     RECT  117.288 45.81 119.34 45.828 ;
     RECT  117.288 46.926 119.34 46.944 ;
     RECT  117.288 48.132 119.34 62.424 ;
     RECT  117.288 63.864 119.34 64.494 ;
     RECT  71.663 65.601 119.34 84.249 ;
     RECT  119.34 2.151 140.4 84.249 ;
     RECT  140.4 60.282 141.359 62.694 ;
     RECT  141.359 60.39 141.395 61.794 ;
     RECT  141.359 62.676 141.395 62.694 ;
     RECT  141.395 60.588 141.935 61.344 ;
     RECT  141.935 61.326 142.367 61.344 ;
     RECT  140.4 64.296 142.367 64.314 ;
     RECT  140.4 58.698 142.403 58.716 ;
    LAYER M3 ;
     RECT  24.48 0.108 42.786 0.523 ;
     RECT  24.372 0.523 42.786 1.147 ;
     RECT  24.372 1.147 42.858 2.143 ;
     RECT  24.015 2.143 42.858 2.263 ;
     RECT  24.015 2.263 43.29 2.371 ;
     RECT  2.415 2.143 2.505 2.413 ;
     RECT  7.815 2.143 7.905 2.413 ;
     RECT  13.215 2.143 13.305 2.413 ;
     RECT  18.615 2.143 18.705 2.413 ;
     RECT  45.615 2.143 45.705 2.413 ;
     RECT  51.015 2.143 51.105 2.413 ;
     RECT  56.415 2.143 56.505 2.413 ;
     RECT  61.815 2.143 61.905 2.413 ;
     RECT  67.215 2.143 67.305 2.413 ;
     RECT  72.615 2.143 72.705 2.413 ;
     RECT  78.015 2.143 78.105 2.413 ;
     RECT  83.415 2.143 83.505 2.413 ;
     RECT  88.815 2.143 88.905 2.413 ;
     RECT  94.215 2.143 94.305 2.413 ;
     RECT  99.615 2.143 99.705 2.413 ;
     RECT  105.015 2.143 105.105 2.413 ;
     RECT  110.415 2.143 110.505 2.413 ;
     RECT  115.815 2.143 115.905 2.413 ;
     RECT  121.215 2.143 121.305 2.413 ;
     RECT  126.615 2.143 126.705 2.413 ;
     RECT  132.015 2.143 132.105 2.413 ;
     RECT  137.415 2.143 137.505 2.413 ;
     RECT  24.012 2.371 43.47 2.569 ;
     RECT  23.976 2.569 43.47 2.641 ;
     RECT  23.868 2.641 43.47 3.569 ;
     RECT  23.94 3.569 43.47 4.801 ;
     RECT  23.796 4.801 43.47 6.283 ;
     RECT  23.724 6.283 43.47 6.539 ;
     RECT  23.832 6.539 43.47 6.809 ;
     RECT  21.348 6.781 21.366 7.087 ;
     RECT  23.976 6.809 43.47 7.231 ;
     RECT  21.348 7.087 21.654 7.429 ;
     RECT  6.228 6.421 6.246 7.501 ;
     RECT  13.215 2.413 13.497 7.663 ;
     RECT  51.015 2.413 51.297 7.771 ;
     RECT  20.124 7.699 20.142 7.861 ;
     RECT  20.052 7.861 20.142 7.897 ;
     RECT  21.096 7.429 21.654 7.897 ;
     RECT  23.976 7.231 43.722 8.401 ;
     RECT  23.976 8.401 43.794 8.491 ;
     RECT  23.94 8.491 43.794 8.509 ;
     RECT  23.724 8.509 43.794 8.671 ;
     RECT  45.615 2.413 45.897 8.671 ;
     RECT  18.615 2.413 18.897 9.049 ;
     RECT  6.228 7.501 6.678 9.085 ;
     RECT  23.328 8.671 43.794 9.121 ;
     RECT  18.504 9.049 18.897 9.283 ;
     RECT  16.992 8.311 17.01 9.589 ;
     RECT  49.212 9.787 49.23 9.824 ;
     RECT  23.328 9.121 44.082 9.931 ;
     RECT  22.824 9.931 44.082 10.129 ;
     RECT  51.015 7.771 51.714 10.435 ;
     RECT  20.052 7.897 21.654 10.471 ;
     RECT  50.832 10.435 51.714 10.685 ;
     RECT  56.415 2.413 56.697 10.831 ;
     RECT  67.215 2.413 67.497 10.831 ;
     RECT  78.015 2.413 78.297 10.831 ;
     RECT  88.815 2.413 89.097 10.831 ;
     RECT  99.615 2.413 99.897 10.831 ;
     RECT  110.415 2.413 110.697 10.831 ;
     RECT  47.016 7.663 47.034 10.843 ;
     RECT  56.304 10.831 56.697 10.877 ;
     RECT  67.104 10.831 67.497 10.877 ;
     RECT  77.904 10.831 78.297 10.877 ;
     RECT  88.704 10.831 89.097 10.877 ;
     RECT  99.504 10.831 99.897 10.877 ;
     RECT  110.304 10.831 110.697 10.877 ;
     RECT  16.992 9.589 17.442 10.903 ;
     RECT  18.288 9.283 18.897 10.903 ;
     RECT  114.588 10.027 114.606 10.973 ;
     RECT  16.992 10.903 18.897 11.011 ;
     RECT  19.62 10.471 21.654 11.011 ;
     RECT  52.236 10.975 52.254 11.011 ;
     RECT  50.832 10.685 51.297 11.039 ;
     RECT  22.392 10.129 44.082 11.137 ;
     RECT  56.415 10.877 56.697 11.137 ;
     RECT  56.415 11.137 57.402 11.213 ;
     RECT  52.236 11.011 52.398 11.237 ;
     RECT  16.992 11.011 21.654 11.281 ;
     RECT  22.392 11.137 44.118 11.281 ;
     RECT  48.996 11.137 49.014 11.281 ;
     RECT  45.18 8.671 45.897 11.371 ;
     RECT  118.296 10.561 118.314 11.371 ;
     RECT  45 11.371 45.897 11.407 ;
     RECT  46.728 10.843 47.034 11.407 ;
     RECT  16.992 11.281 44.226 11.551 ;
     RECT  45 11.407 47.034 11.551 ;
     RECT  47.808 11.137 47.826 11.641 ;
     RECT  48.996 11.281 49.338 11.641 ;
     RECT  47.808 11.641 49.338 11.693 ;
     RECT  57.636 11.281 57.654 11.705 ;
     RECT  48.924 11.693 49.338 12.091 ;
     RECT  118.296 11.371 118.89 12.181 ;
     RECT  47.808 11.693 47.862 12.245 ;
     RECT  118.296 12.181 118.926 12.451 ;
     RECT  16.992 11.551 47.034 12.605 ;
     RECT  48.924 12.091 49.878 12.797 ;
     RECT  15.948 10.705 15.966 12.865 ;
     RECT  50.976 11.039 51.297 13.003 ;
     RECT  50.976 13.003 51.318 13.051 ;
     RECT  52.38 11.237 52.398 13.051 ;
     RECT  50.976 13.051 52.398 13.091 ;
     RECT  15.912 12.865 15.966 13.171 ;
     RECT  16.992 12.605 44.37 13.171 ;
     RECT  15.156 11.371 15.174 13.369 ;
     RECT  15.912 13.171 44.37 13.369 ;
     RECT  49.86 12.797 49.878 13.397 ;
     RECT  45.324 12.605 47.034 13.405 ;
     RECT  47.844 12.245 47.862 13.405 ;
     RECT  45.324 13.405 47.862 13.433 ;
     RECT  110.415 10.877 110.697 13.525 ;
     RECT  56.415 11.213 56.697 13.531 ;
     RECT  67.215 10.877 67.497 13.531 ;
     RECT  78.015 10.877 78.297 13.531 ;
     RECT  88.815 10.877 89.097 13.531 ;
     RECT  99.615 10.877 99.897 13.531 ;
     RECT  56.304 13.531 56.697 14.009 ;
     RECT  67.104 13.531 67.497 14.009 ;
     RECT  77.904 13.531 78.297 14.009 ;
     RECT  88.704 13.531 89.097 14.009 ;
     RECT  99.504 13.531 99.897 14.009 ;
     RECT  110.304 13.525 110.697 14.009 ;
     RECT  114.588 13.531 114.606 14.141 ;
     RECT  15.156 13.369 44.37 14.189 ;
     RECT  47.268 13.433 47.862 14.285 ;
     RECT  118.296 12.451 118.962 14.341 ;
     RECT  48.924 12.797 48.942 14.377 ;
     RECT  48.852 14.377 48.942 14.429 ;
     RECT  15.156 14.189 31.878 14.549 ;
     RECT  33.048 14.189 44.37 14.669 ;
     RECT  33.048 14.669 33.894 14.711 ;
     RECT  34.668 14.669 44.37 14.881 ;
     RECT  50.976 13.091 51.297 15.089 ;
     RECT  47.844 14.285 47.862 15.295 ;
     RECT  48.924 14.429 48.942 15.331 ;
     RECT  47.304 15.295 47.862 15.485 ;
     RECT  110.415 14.009 110.697 15.685 ;
     RECT  56.415 14.009 56.697 15.691 ;
     RECT  67.215 14.009 67.497 15.691 ;
     RECT  78.015 14.009 78.297 15.691 ;
     RECT  88.815 14.009 89.097 15.691 ;
     RECT  99.615 14.009 99.897 15.691 ;
     RECT  110.304 15.685 110.697 15.725 ;
     RECT  56.304 15.691 56.697 15.728 ;
     RECT  67.104 15.691 67.497 15.728 ;
     RECT  77.904 15.691 78.297 15.728 ;
     RECT  88.704 15.691 89.097 15.728 ;
     RECT  99.504 15.691 99.897 15.728 ;
     RECT  114.588 15.691 114.606 15.821 ;
     RECT  121.215 2.413 121.497 15.871 ;
     RECT  120.852 15.871 121.497 16.231 ;
     RECT  45.324 13.433 46.314 16.259 ;
     RECT  118.152 14.341 118.962 16.267 ;
     RECT  52.38 13.091 52.398 16.295 ;
     RECT  48.924 15.331 49.158 16.349 ;
     RECT  61.815 2.413 62.097 16.363 ;
     RECT  61.815 16.363 62.694 16.541 ;
     RECT  120.492 16.231 121.497 16.651 ;
     RECT  51.015 15.089 51.297 16.807 ;
     RECT  118.152 16.267 119.322 16.807 ;
     RECT  49.14 16.349 49.158 16.835 ;
     RECT  50.796 16.807 51.297 16.907 ;
     RECT  52.416 16.807 52.434 16.907 ;
     RECT  117.684 16.807 119.322 17.077 ;
     RECT  120.42 16.651 121.497 17.077 ;
     RECT  56.415 15.728 56.697 17.311 ;
     RECT  58.968 16.303 58.986 17.323 ;
     RECT  56.304 17.311 56.697 17.357 ;
     RECT  117.684 17.077 121.497 17.611 ;
     RECT  61.815 16.541 62.097 17.851 ;
     RECT  59.868 17.899 59.886 17.951 ;
     RECT  45.324 16.259 45.897 17.959 ;
     RECT  54.72 17.851 54.738 17.981 ;
     RECT  61.815 17.851 62.73 17.981 ;
     RECT  74.664 17.851 74.682 17.981 ;
     RECT  86.652 17.851 86.67 17.981 ;
     RECT  98.604 17.851 98.622 17.981 ;
     RECT  106.596 17.851 106.614 17.981 ;
     RECT  114.588 17.851 114.606 17.981 ;
     RECT  33.336 14.711 33.894 18.193 ;
     RECT  23.328 14.549 31.878 18.221 ;
     RECT  32.76 18.193 33.894 18.221 ;
     RECT  58.716 17.323 58.986 18.221 ;
     RECT  45.324 17.959 46.026 18.841 ;
     RECT  45.324 18.841 46.746 18.845 ;
     RECT  34.668 14.881 44.442 18.931 ;
     RECT  45.504 18.845 46.746 19.075 ;
     RECT  34.668 18.931 44.478 19.201 ;
     RECT  56.415 17.357 56.697 19.471 ;
     RECT  67.215 15.728 67.497 19.471 ;
     RECT  78.015 15.728 78.297 19.471 ;
     RECT  88.815 15.728 89.097 19.471 ;
     RECT  99.615 15.728 99.897 19.471 ;
     RECT  110.415 15.725 110.697 19.471 ;
     RECT  34.668 19.201 44.514 19.543 ;
     RECT  34.668 19.543 44.622 19.573 ;
     RECT  45.504 19.075 46.818 19.573 ;
     RECT  114.588 19.483 114.606 19.613 ;
     RECT  34.668 19.573 46.818 19.643 ;
     RECT  15.156 14.549 22.41 19.723 ;
     RECT  23.328 18.221 31.626 19.723 ;
     RECT  51.015 16.907 51.297 19.997 ;
     RECT  61.815 17.981 62.097 19.997 ;
     RECT  72.615 2.413 72.897 19.997 ;
     RECT  83.415 2.413 83.697 19.997 ;
     RECT  94.215 2.413 94.497 19.997 ;
     RECT  105.015 2.413 105.297 19.997 ;
     RECT  115.815 2.413 116.097 19.997 ;
     RECT  110.304 19.471 110.697 20.045 ;
     RECT  56.304 19.471 56.697 20.048 ;
     RECT  67.104 19.471 67.497 20.048 ;
     RECT  77.904 19.471 78.297 20.048 ;
     RECT  88.704 19.471 89.097 20.048 ;
     RECT  99.504 19.471 99.897 20.048 ;
     RECT  34.668 19.643 46.782 20.141 ;
     RECT  15.156 19.723 31.626 20.267 ;
     RECT  51.207 19.997 51.297 20.267 ;
     RECT  56.607 20.048 56.697 20.267 ;
     RECT  62.007 19.997 62.097 20.267 ;
     RECT  67.407 20.048 67.497 20.267 ;
     RECT  72.807 19.997 72.897 20.267 ;
     RECT  78.207 20.048 78.297 20.267 ;
     RECT  83.607 19.997 83.697 20.267 ;
     RECT  89.007 20.048 89.097 20.267 ;
     RECT  94.407 19.997 94.497 20.267 ;
     RECT  99.807 20.048 99.897 20.267 ;
     RECT  105.207 19.997 105.297 20.267 ;
     RECT  110.607 20.045 110.697 20.267 ;
     RECT  116.007 19.997 116.097 20.267 ;
     RECT  34.668 20.141 46.746 20.429 ;
     RECT  34.668 20.429 36.738 20.489 ;
     RECT  33.552 18.221 33.894 20.491 ;
     RECT  34.668 20.489 36.63 20.491 ;
     RECT  33.552 20.491 36.63 20.534 ;
     RECT  37.584 20.429 46.746 20.615 ;
     RECT  37.584 20.615 46.386 20.669 ;
     RECT  15.156 20.267 28.926 20.765 ;
     RECT  2.415 2.413 2.697 20.827 ;
     RECT  15.156 20.765 27.162 20.957 ;
     RECT  35.496 20.534 36.63 20.957 ;
     RECT  11.304 20.317 11.322 21.001 ;
     RECT  28.26 20.765 28.926 21.005 ;
     RECT  37.584 20.669 45.774 21.005 ;
     RECT  23.328 20.957 27.162 21.053 ;
     RECT  50.184 20.551 50.202 21.053 ;
     RECT  23.328 21.053 24.354 21.101 ;
     RECT  13.215 7.663 14.166 21.115 ;
     RECT  15.156 20.957 22.338 21.115 ;
     RECT  58.968 18.221 58.986 21.115 ;
     RECT  10.188 19.345 10.206 21.163 ;
     RECT  25.344 21.053 27.162 21.245 ;
     RECT  58.716 21.115 59.346 21.245 ;
     RECT  34.668 20.534 34.686 21.341 ;
     RECT  37.584 21.005 44.442 21.341 ;
     RECT  37.584 21.341 43.398 21.461 ;
     RECT  33.552 20.534 33.894 21.485 ;
     RECT  38.7 21.461 43.398 21.485 ;
     RECT  38.772 21.485 43.398 21.497 ;
     RECT  6.228 9.085 6.75 21.541 ;
     RECT  2.415 20.827 3.33 21.631 ;
     RECT  25.92 21.245 27.162 21.677 ;
     RECT  33.552 21.485 33.57 21.677 ;
     RECT  37.584 21.461 37.602 21.677 ;
     RECT  42.3 21.497 43.398 21.677 ;
     RECT  44.172 21.341 44.442 21.677 ;
     RECT  45.216 21.005 45.774 21.677 ;
     RECT  7.815 2.413 8.097 21.691 ;
     RECT  8.82 21.403 8.838 21.691 ;
     RECT  35.496 20.957 36.486 21.691 ;
     RECT  38.772 21.497 41.31 21.725 ;
     RECT  10.188 21.163 10.458 21.739 ;
     RECT  44.352 21.677 44.442 21.979 ;
     RECT  45.216 21.677 45.234 21.979 ;
     RECT  13.215 21.115 22.338 22.072 ;
     RECT  7.815 21.691 8.838 22.075 ;
     RECT  13.104 22.072 22.338 22.109 ;
     RECT  13.215 22.109 22.338 22.464 ;
     RECT  23.328 21.101 23.634 22.464 ;
     RECT  25.92 21.677 26.802 22.464 ;
     RECT  27.936 21.979 27.954 22.464 ;
     RECT  28.908 21.005 28.926 22.464 ;
     RECT  30.276 20.267 31.626 22.464 ;
     RECT  32.76 18.221 32.778 22.464 ;
     RECT  34.776 21.691 36.594 22.464 ;
     RECT  38.772 21.725 38.862 22.464 ;
     RECT  39.78 21.725 41.31 22.464 ;
     RECT  42.516 21.677 43.398 22.464 ;
     RECT  44.352 21.979 45.234 22.464 ;
     RECT  47.844 15.485 47.862 22.464 ;
     RECT  117.216 17.611 121.497 22.464 ;
     RECT  2.415 21.631 3.582 23.549 ;
     RECT  2.415 23.549 3.33 23.585 ;
     RECT  13.215 22.464 121.497 24.763 ;
     RECT  13.104 24.763 121.497 24.809 ;
     RECT  7.815 22.075 8.982 25.723 ;
     RECT  9.828 21.739 10.458 25.723 ;
     RECT  6.228 21.541 7.002 25.987 ;
     RECT  7.815 25.723 10.458 26.107 ;
     RECT  11.304 21.001 11.898 26.107 ;
     RECT  6.228 25.987 7.074 26.123 ;
     RECT  13.215 24.809 121.497 26.813 ;
     RECT  7.815 26.107 11.898 26.833 ;
     RECT  13.215 26.813 119.43 28.445 ;
     RECT  118.296 28.445 119.43 28.637 ;
     RECT  13.215 28.445 117.45 28.651 ;
     RECT  118.404 28.637 119.43 28.925 ;
     RECT  6.228 26.123 6.75 29.515 ;
     RECT  12.96 28.651 117.45 29.789 ;
     RECT  6.228 29.515 6.822 30.721 ;
     RECT  120.276 26.813 121.497 30.845 ;
     RECT  120.384 30.845 121.497 31.229 ;
     RECT  118.656 28.925 119.43 31.421 ;
     RECT  12.96 29.789 117.414 31.495 ;
     RECT  12.888 31.495 117.414 31.661 ;
     RECT  7.815 26.833 11.97 32.233 ;
     RECT  12.888 31.661 117.288 32.233 ;
     RECT  7.815 32.233 117.288 33.067 ;
     RECT  7.815 33.067 117.378 33.245 ;
     RECT  5.112 29.611 5.13 33.355 ;
     RECT  6.048 30.721 6.822 33.355 ;
     RECT  120.564 31.229 121.497 33.437 ;
     RECT  120.6 33.437 121.497 34.109 ;
     RECT  120.636 34.109 121.497 34.205 ;
     RECT  118.728 31.421 119.43 34.397 ;
     RECT  120.888 34.205 121.497 34.493 ;
     RECT  119.412 34.397 119.43 34.589 ;
     RECT  7.815 33.245 117.288 34.651 ;
     RECT  7.815 34.651 117.378 34.735 ;
     RECT  119.808 34.627 119.862 34.861 ;
     RECT  119.808 34.861 120.114 35.167 ;
     RECT  119.808 35.167 120.402 35.195 ;
     RECT  118.584 34.465 118.602 35.339 ;
     RECT  7.815 34.735 117.414 35.465 ;
     RECT  120.276 35.195 120.402 35.611 ;
     RECT  5.112 33.355 6.822 35.851 ;
     RECT  120.276 35.611 120.474 35.995 ;
     RECT  121.215 34.493 121.497 35.995 ;
     RECT  119.088 35.851 119.106 36.091 ;
     RECT  120.276 35.995 121.497 36.419 ;
     RECT  119.088 36.091 119.502 36.605 ;
     RECT  119.484 36.605 119.502 36.887 ;
     RECT  7.815 35.465 117.378 36.922 ;
     RECT  7.815 36.922 117.414 36.989 ;
     RECT  118.62 36.895 118.638 37.049 ;
     RECT  120.312 36.419 121.497 37.435 ;
     RECT  7.815 36.989 117.378 38.005 ;
     RECT  120.06 37.435 121.497 38.011 ;
     RECT  7.815 38.005 117.414 38.045 ;
     RECT  5.04 35.851 6.822 38.203 ;
     RECT  5.04 38.203 6.858 38.333 ;
     RECT  119.988 38.011 121.497 38.741 ;
     RECT  5.04 38.333 6.822 39.181 ;
     RECT  7.815 38.045 117.378 39.317 ;
     RECT  120.096 38.741 121.497 39.317 ;
     RECT  4.644 39.181 6.822 39.389 ;
     RECT  120.276 39.317 121.497 39.581 ;
     RECT  119.088 39.865 119.106 39.965 ;
     RECT  120.348 39.581 121.497 40.315 ;
     RECT  120.276 40.315 121.497 40.567 ;
     RECT  7.815 39.317 117.288 40.603 ;
     RECT  120.168 40.567 121.497 41.215 ;
     RECT  7.815 40.603 117.378 41.243 ;
     RECT  120.096 41.215 121.497 41.369 ;
     RECT  5.04 39.389 6.822 41.995 ;
     RECT  120.276 41.369 121.497 42.139 ;
     RECT  5.04 41.995 6.894 42.173 ;
     RECT  7.815 41.243 117.288 42.325 ;
     RECT  118.584 42.187 118.602 42.359 ;
     RECT  119.628 42.139 121.497 42.359 ;
     RECT  7.815 42.325 117.414 42.365 ;
     RECT  120.276 42.359 121.497 42.845 ;
     RECT  2.415 23.585 2.697 42.871 ;
     RECT  2.412 42.871 2.697 43.141 ;
     RECT  2.376 43.141 2.697 43.295 ;
     RECT  0.216 42.187 0.234 43.325 ;
     RECT  120.492 42.845 121.497 43.675 ;
     RECT  118.584 43.267 118.602 43.771 ;
     RECT  120.276 43.675 121.497 43.835 ;
     RECT  7.815 42.365 117.288 44.059 ;
     RECT  118.584 43.771 119.142 44.069 ;
     RECT  4.032 43.501 4.05 44.105 ;
     RECT  7.815 44.059 117.378 44.105 ;
     RECT  5.04 42.173 6.822 44.347 ;
     RECT  4.212 44.221 4.23 44.375 ;
     RECT  118.584 44.069 118.602 44.375 ;
     RECT  7.815 44.105 117.288 44.419 ;
     RECT  119.592 44.347 119.61 44.581 ;
     RECT  120.492 43.835 121.497 44.581 ;
     RECT  5.04 44.347 7.002 44.609 ;
     RECT  7.74 44.419 117.288 44.645 ;
     RECT  7.776 44.645 117.288 44.681 ;
     RECT  119.592 44.581 121.497 44.753 ;
     RECT  5.04 44.609 6.858 44.987 ;
     RECT  7.815 44.681 117.288 45.023 ;
     RECT  120.276 44.753 121.497 45.149 ;
     RECT  11.664 45.023 117.288 45.787 ;
     RECT  11.664 45.787 117.378 45.833 ;
     RECT  7.815 45.023 10.854 45.869 ;
     RECT  120.384 45.149 121.497 45.967 ;
     RECT  11.664 45.833 117.288 46.139 ;
     RECT  120.276 45.967 121.497 46.849 ;
     RECT  11.952 46.139 117.288 46.921 ;
     RECT  120.168 46.849 121.497 46.949 ;
     RECT  11.952 46.921 117.414 46.973 ;
     RECT  11.952 46.973 117.288 48.091 ;
     RECT  120.276 46.949 121.497 48.199 ;
     RECT  120.096 48.199 121.497 48.389 ;
     RECT  120.276 48.389 121.497 48.797 ;
     RECT  118.584 48.811 118.602 48.955 ;
     RECT  118.584 48.955 119.142 49.379 ;
     RECT  120.42 48.797 121.497 49.549 ;
     RECT  119.088 49.379 119.106 49.661 ;
     RECT  120.24 49.549 121.497 49.747 ;
     RECT  11.952 48.091 117.378 49.882 ;
     RECT  11.952 49.882 117.414 50.237 ;
     RECT  120.168 49.747 121.497 50.431 ;
     RECT  120.06 50.431 121.497 50.791 ;
     RECT  119.988 50.791 121.497 50.999 ;
     RECT  118.584 50.899 118.602 51.089 ;
     RECT  11.952 50.237 117.378 51.241 ;
     RECT  11.952 51.241 117.414 51.581 ;
     RECT  120.06 50.999 121.497 51.629 ;
     RECT  120.06 51.629 120.186 51.739 ;
     RECT  119.52 51.739 120.186 51.745 ;
     RECT  119.088 51.745 120.186 51.907 ;
     RECT  118.584 51.907 120.186 52.169 ;
     RECT  118.584 52.169 118.674 52.241 ;
     RECT  118.584 52.241 118.602 52.277 ;
     RECT  119.412 52.169 120.186 52.447 ;
     RECT  7.815 45.869 10.818 52.459 ;
     RECT  11.952 51.581 117.378 52.459 ;
     RECT  119.412 52.447 120.402 52.547 ;
     RECT  11.88 52.459 117.378 52.591 ;
     RECT  119.448 52.547 120.402 52.745 ;
     RECT  119.844 52.745 120.402 53.015 ;
     RECT  120.096 53.015 120.402 53.527 ;
     RECT  121.215 51.629 121.497 53.527 ;
     RECT  120.096 53.527 121.497 53.597 ;
     RECT  120.096 53.597 120.402 53.761 ;
     RECT  119.988 53.761 120.402 54.031 ;
     RECT  118.584 53.221 118.602 54.173 ;
     RECT  11.88 52.591 117.414 54.269 ;
     RECT  118.62 54.211 118.638 54.337 ;
     RECT  118.62 54.337 118.674 54.401 ;
     RECT  119.88 54.031 120.402 54.427 ;
     RECT  121.215 53.597 121.497 54.427 ;
     RECT  118.656 54.401 118.674 54.436 ;
     RECT  118.656 54.436 118.71 54.437 ;
     RECT  119.88 54.427 121.497 54.473 ;
     RECT  118.692 54.437 118.71 54.607 ;
     RECT  119.88 54.473 120.474 54.607 ;
     RECT  118.692 54.607 119.07 54.671 ;
     RECT  119.052 54.671 119.07 54.679 ;
     RECT  119.808 54.607 120.474 54.679 ;
     RECT  119.052 54.679 120.474 54.749 ;
     RECT  119.88 54.749 120.474 55.229 ;
     RECT  119.88 55.229 120.294 55.319 ;
     RECT  119.052 54.749 119.106 55.325 ;
     RECT  120.276 55.319 120.294 55.421 ;
     RECT  11.88 54.269 117.378 55.552 ;
     RECT  11.88 55.552 117.414 55.613 ;
     RECT  120.384 55.957 120.402 55.997 ;
     RECT  118.584 55.453 118.674 56.021 ;
     RECT  118.656 56.021 118.674 56.219 ;
     RECT  120.276 56.251 120.294 56.291 ;
     RECT  119.088 56.335 119.106 56.477 ;
     RECT  120.204 56.461 120.222 56.569 ;
     RECT  11.88 55.613 117.378 56.632 ;
     RECT  119.592 56.569 120.222 56.669 ;
     RECT  119.592 56.669 119.898 56.795 ;
     RECT  7.815 52.459 11.106 57.019 ;
     RECT  11.88 56.632 117.414 57.019 ;
     RECT  7.815 57.019 117.414 57.437 ;
     RECT  119.736 56.795 119.898 57.569 ;
     RECT  118.584 57.001 118.746 57.595 ;
     RECT  119.736 57.569 119.826 57.595 ;
     RECT  118.584 57.595 119.826 57.641 ;
     RECT  7.815 57.437 117.378 58.261 ;
     RECT  118.584 57.641 118.746 58.423 ;
     RECT  119.7 57.641 119.826 58.423 ;
     RECT  118.584 58.423 119.826 58.459 ;
     RECT  118.584 58.459 120.006 58.649 ;
     RECT  119.556 58.649 119.574 58.721 ;
     RECT  118.584 58.649 118.638 58.877 ;
     RECT  139.428 58.657 139.446 59.035 ;
     RECT  139.428 59.035 140.058 59.071 ;
     RECT  120.312 59.035 120.33 59.099 ;
     RECT  118.584 58.877 118.602 59.611 ;
     RECT  119.736 59.467 120.114 59.611 ;
     RECT  138.528 59.071 138.654 59.809 ;
     RECT  139.428 59.071 140.274 59.809 ;
     RECT  142.38 58.693 142.398 59.851 ;
     RECT  142.308 59.851 142.398 59.885 ;
     RECT  138.528 59.809 140.274 60.173 ;
     RECT  118.584 59.611 120.114 60.221 ;
     RECT  7.815 58.261 117.414 60.283 ;
     RECT  141.336 60.277 141.354 60.317 ;
     RECT  7.815 60.283 117.45 60.341 ;
     RECT  118.584 60.221 118.602 60.413 ;
     RECT  119.592 60.221 120.114 60.413 ;
     RECT  141.372 60.385 141.39 60.461 ;
     RECT  142.308 59.885 142.326 60.571 ;
     RECT  138.528 60.173 139.878 60.575 ;
     RECT  141.912 60.571 142.326 60.715 ;
     RECT  141.912 60.715 142.362 61.079 ;
     RECT  138.528 60.575 139.518 61.115 ;
     RECT  119.736 60.413 120.114 61.187 ;
     RECT  137.415 2.413 137.697 61.231 ;
     RECT  138.528 61.115 139.302 61.231 ;
     RECT  118.584 61.195 118.602 61.243 ;
     RECT  119.736 61.187 119.79 61.243 ;
     RECT  142.344 61.079 142.362 61.349 ;
     RECT  137.415 61.231 139.302 61.385 ;
     RECT  7.815 60.341 117.414 61.591 ;
     RECT  118.584 61.243 119.79 61.691 ;
     RECT  118.584 61.691 118.746 61.763 ;
     RECT  7.815 61.591 117.45 61.853 ;
     RECT  118.584 61.763 118.602 61.889 ;
     RECT  141.372 61.771 141.39 62.131 ;
     RECT  119.628 61.691 119.79 62.159 ;
     RECT  141.336 62.131 141.39 62.203 ;
     RECT  137.415 61.385 139.086 62.239 ;
     RECT  7.815 61.853 117.414 62.339 ;
     RECT  7.815 62.339 117.378 62.429 ;
     RECT  137.415 62.239 139.626 62.545 ;
     RECT  140.796 62.203 141.39 62.621 ;
     RECT  119.988 62.311 120.186 62.699 ;
     RECT  141.372 62.621 141.39 62.909 ;
     RECT  137.415 62.545 139.914 62.941 ;
     RECT  137.415 62.941 139.95 63.121 ;
     RECT  7.815 62.429 117.288 63.528 ;
     RECT  7.815 63.528 23.238 63.734 ;
     RECT  137.415 63.121 140.274 63.779 ;
     RECT  28.512 63.528 28.53 63.821 ;
     RECT  137.415 63.779 139.41 63.917 ;
     RECT  137.415 63.917 139.086 64.049 ;
     RECT  44.712 63.528 44.73 64.267 ;
     RECT  142.344 62.731 142.362 64.319 ;
     RECT  31.32 63.528 31.338 64.363 ;
     RECT  32.328 63.528 33.066 64.363 ;
     RECT  41.04 64.315 41.058 64.363 ;
     RECT  140.256 63.779 140.274 64.391 ;
     RECT  137.415 64.049 139.05 64.445 ;
     RECT  31.32 64.363 33.318 64.507 ;
     RECT  34.308 63.528 34.326 64.507 ;
     RECT  138.528 64.445 139.05 64.589 ;
     RECT  52.488 63.528 52.83 64.651 ;
     RECT  51.48 63.528 51.498 64.669 ;
     RECT  52.488 64.651 52.974 64.669 ;
     RECT  53.964 63.528 53.982 64.699 ;
     RECT  51.48 64.669 52.974 64.741 ;
     RECT  53.964 64.699 54.522 64.741 ;
     RECT  38.448 63.528 39.222 64.795 ;
     RECT  29.376 63.528 29.394 64.831 ;
     RECT  38.448 64.795 39.87 64.939 ;
     RECT  46.188 64.363 46.782 64.939 ;
     RECT  27.18 64.507 27.198 64.987 ;
     RECT  138.528 64.589 138.834 65.165 ;
     RECT  138.564 65.165 138.834 65.213 ;
     RECT  62.928 64.987 62.946 65.227 ;
     RECT  41.04 64.363 41.202 65.275 ;
     RECT  42.228 63.528 42.246 65.275 ;
     RECT  60.588 65.245 60.606 65.281 ;
     RECT  38.052 64.939 39.87 65.323 ;
     RECT  43.164 63.528 43.182 65.323 ;
     RECT  67.644 63.528 67.662 65.326 ;
     RECT  56.016 64.747 56.034 65.443 ;
     RECT  41.04 65.275 42.246 65.515 ;
     RECT  43.128 65.323 43.182 65.515 ;
     RECT  44.136 64.267 44.73 65.515 ;
     RECT  31.32 64.507 34.326 65.563 ;
     RECT  28.656 64.831 29.394 65.593 ;
     RECT  30.744 65.563 34.326 65.593 ;
     RECT  37.98 65.323 39.87 65.593 ;
     RECT  40.752 65.515 42.246 65.593 ;
     RECT  45.972 64.939 46.782 65.593 ;
     RECT  51.48 64.741 54.522 65.593 ;
     RECT  56.016 65.443 56.25 65.593 ;
     RECT  67.572 65.326 67.662 65.593 ;
     RECT  138.564 65.213 138.582 65.693 ;
     RECT  28.656 65.593 29.697 65.755 ;
     RECT  24.207 65.593 24.297 65.785 ;
     RECT  45.807 65.593 46.782 65.785 ;
     RECT  62.007 65.593 62.097 65.803 ;
     RECT  60.444 65.281 60.606 65.821 ;
     RECT  23.904 65.785 24.297 65.837 ;
     RECT  45.504 65.785 46.782 65.837 ;
     RECT  30.744 65.593 35.097 65.849 ;
     RECT  51.207 65.593 54.522 65.863 ;
     RECT  67.407 65.593 67.662 65.863 ;
     RECT  72.807 65.593 72.897 65.863 ;
     RECT  78.207 65.593 78.297 65.863 ;
     RECT  83.607 65.593 83.697 65.863 ;
     RECT  89.007 65.593 89.097 65.863 ;
     RECT  94.407 65.593 94.497 65.863 ;
     RECT  99.807 65.593 99.897 65.863 ;
     RECT  105.207 65.593 105.297 65.863 ;
     RECT  110.607 65.593 110.697 65.863 ;
     RECT  116.007 65.593 116.097 65.863 ;
     RECT  45.615 65.837 46.782 65.899 ;
     RECT  67.215 65.863 67.662 65.911 ;
     RECT  59.076 65.479 59.094 65.947 ;
     RECT  60.228 65.821 60.606 65.947 ;
     RECT  61.704 65.803 62.097 65.947 ;
     RECT  62.892 65.227 62.946 65.947 ;
     RECT  64.008 65.407 64.026 65.947 ;
     RECT  45.615 65.899 46.89 66.077 ;
     RECT  36.828 64.939 36.846 66.091 ;
     RECT  37.98 65.593 42.246 66.091 ;
     RECT  43.128 65.515 44.73 66.091 ;
     RECT  61.596 65.947 62.097 66.451 ;
     RECT  62.892 65.947 64.026 66.451 ;
     RECT  61.596 66.451 64.026 66.487 ;
     RECT  51.015 65.863 54.522 66.571 ;
     RECT  31.932 65.849 35.097 66.667 ;
     RECT  35.892 66.091 35.91 66.667 ;
     RECT  37.98 66.091 44.73 66.667 ;
     RECT  30.744 65.849 30.762 66.829 ;
     RECT  51.015 66.571 54.63 66.829 ;
     RECT  57.78 64.705 57.798 66.829 ;
     RECT  59.076 65.947 60.606 66.829 ;
     RECT  24.015 65.837 24.297 66.901 ;
     RECT  56.016 65.593 56.697 66.901 ;
     RECT  24.015 66.901 24.354 66.991 ;
     RECT  30.744 66.829 30.798 66.991 ;
     RECT  45.615 66.077 46.782 66.991 ;
     RECT  51.015 66.829 54.774 66.991 ;
     RECT  57.78 66.829 60.606 67.003 ;
     RECT  61.524 66.487 64.026 67.003 ;
     RECT  56.016 66.901 56.754 67.051 ;
     RECT  57.78 67.003 64.026 67.063 ;
     RECT  23.904 66.991 24.354 67.091 ;
     RECT  30.744 66.991 30.87 67.091 ;
     RECT  30.744 67.091 30.834 67.339 ;
     RECT  51.015 66.991 54.81 67.387 ;
     RECT  50.724 67.387 54.81 67.435 ;
     RECT  55.944 67.051 56.754 67.441 ;
     RECT  57.78 67.063 64.422 67.441 ;
     RECT  30.708 67.339 30.834 67.469 ;
     RECT  30.708 67.469 30.798 67.531 ;
     RECT  30.6 67.531 30.798 67.661 ;
     RECT  50.724 67.435 54.846 67.661 ;
     RECT  30.6 67.661 30.762 67.675 ;
     RECT  36.684 66.091 36.846 67.675 ;
     RECT  30.492 67.675 30.762 67.829 ;
     RECT  23.904 67.091 24.297 68.009 ;
     RECT  45.504 66.991 46.782 68.009 ;
     RECT  45.615 68.009 46.782 68.107 ;
     RECT  50.724 67.661 54.738 68.141 ;
     RECT  45.615 68.107 46.818 68.285 ;
     RECT  31.932 66.667 35.91 68.347 ;
     RECT  36.684 67.675 36.99 68.347 ;
     RECT  50.976 68.141 54.738 68.381 ;
     RECT  65.16 66.475 65.178 68.779 ;
     RECT  31.932 68.347 36.99 69.451 ;
     RECT  37.728 66.667 44.73 69.451 ;
     RECT  31.932 69.451 44.73 70.075 ;
     RECT  66.564 65.911 67.662 70.375 ;
     RECT  50.976 68.381 54.63 70.507 ;
     RECT  7.815 63.734 23.094 70.565 ;
     RECT  50.976 70.507 54.738 70.681 ;
     RECT  50.724 70.681 54.738 70.771 ;
     RECT  55.944 67.441 64.422 70.771 ;
     RECT  30.744 67.829 30.762 70.795 ;
     RECT  65.16 68.779 65.286 70.915 ;
     RECT  66.168 70.375 67.662 70.915 ;
     RECT  50.724 70.771 64.422 70.928 ;
     RECT  65.16 70.915 67.662 70.928 ;
     RECT  30.744 70.795 30.798 71.077 ;
     RECT  68.616 63.528 68.634 71.185 ;
     RECT  50.724 70.928 67.662 71.311 ;
     RECT  50.724 71.311 67.734 71.455 ;
     RECT  24.015 68.009 24.297 71.752 ;
     RECT  31.932 70.075 44.802 71.752 ;
     RECT  45.615 68.285 46.782 71.752 ;
     RECT  68.616 71.185 68.85 71.761 ;
     RECT  69.84 71.221 69.858 71.761 ;
     RECT  50.724 71.455 67.806 71.887 ;
     RECT  11.088 70.565 23.094 71.951 ;
     RECT  50.724 71.887 67.878 72.149 ;
     RECT  23.904 71.752 24.297 72.329 ;
     RECT  31.932 71.752 46.782 72.329 ;
     RECT  7.815 70.565 10.242 72.455 ;
     RECT  50.724 72.149 67.662 72.689 ;
     RECT  5.04 44.987 6.822 72.725 ;
     RECT  50.832 72.689 67.662 72.797 ;
     RECT  68.616 71.761 69.03 72.841 ;
     RECT  10.224 72.455 10.242 72.869 ;
     RECT  50.868 72.797 67.662 72.931 ;
     RECT  68.436 72.841 69.03 72.931 ;
     RECT  69.768 71.761 69.966 72.931 ;
     RECT  50.868 72.931 69.966 72.995 ;
     RECT  49.068 73.003 49.086 73.111 ;
     RECT  49.032 73.111 49.086 73.339 ;
     RECT  24.015 72.329 24.297 73.471 ;
     RECT  31.932 72.329 44.802 73.471 ;
     RECT  45.615 72.329 46.782 73.471 ;
     RECT  28.26 65.755 29.697 73.579 ;
     RECT  50.904 72.995 69.966 73.819 ;
     RECT  23.904 73.471 24.297 74.048 ;
     RECT  31.932 73.471 46.782 74.048 ;
     RECT  28.26 73.579 30.006 74.353 ;
     RECT  30.744 71.077 30.978 74.353 ;
     RECT  15.66 71.951 23.094 74.381 ;
     RECT  7.815 72.455 9.378 74.417 ;
     RECT  49.032 73.339 49.122 74.461 ;
     RECT  49.86 65.323 49.878 74.461 ;
     RECT  11.088 71.951 14.598 74.489 ;
     RECT  49.032 74.461 49.878 74.489 ;
     RECT  49.068 74.489 49.878 74.579 ;
     RECT  28.26 74.353 30.978 74.659 ;
     RECT  49.068 74.579 49.122 74.669 ;
     RECT  45.615 74.048 46.782 74.683 ;
     RECT  31.932 74.048 44.802 74.687 ;
     RECT  49.86 74.579 49.878 74.821 ;
     RECT  50.724 73.819 69.966 74.821 ;
     RECT  45.615 74.683 46.818 74.827 ;
     RECT  9.036 74.417 9.378 74.849 ;
     RECT  45.615 74.827 46.89 74.957 ;
     RECT  49.068 74.669 49.086 74.957 ;
     RECT  70.776 74.731 70.794 75.091 ;
     RECT  28.26 74.659 31.05 75.259 ;
     RECT  11.088 74.489 14.562 75.299 ;
     RECT  28.26 75.259 31.194 75.437 ;
     RECT  11.088 75.299 14.382 75.533 ;
     RECT  49.86 74.821 69.966 75.541 ;
     RECT  70.776 75.091 70.974 75.541 ;
     RECT  24.015 74.048 24.297 75.631 ;
     RECT  25.02 68.971 25.038 75.631 ;
     RECT  32.076 74.687 44.802 75.631 ;
     RECT  45.615 74.957 46.782 75.631 ;
     RECT  24.015 75.631 25.038 75.677 ;
     RECT  7.815 74.417 8.298 76.037 ;
     RECT  24.015 75.677 24.297 76.171 ;
     RECT  49.032 75.811 49.05 76.441 ;
     RECT  11.124 75.533 14.382 76.469 ;
     RECT  23.904 76.171 24.297 76.477 ;
     RECT  25.02 75.677 25.038 76.477 ;
     RECT  15.876 74.381 23.094 76.577 ;
     RECT  32.076 75.631 46.782 76.649 ;
     RECT  28.26 75.437 31.086 76.747 ;
     RECT  49.86 75.541 70.974 77.009 ;
     RECT  18.18 76.577 23.094 77.035 ;
     RECT  23.904 76.477 25.038 77.035 ;
     RECT  49.032 76.441 49.122 77.089 ;
     RECT  49.86 77.009 49.878 77.089 ;
     RECT  45.615 76.649 46.782 77.161 ;
     RECT  11.124 76.469 11.142 77.189 ;
     RECT  5.076 72.725 6.822 77.315 ;
     RECT  11.88 76.469 14.382 77.351 ;
     RECT  49.032 77.089 49.878 77.387 ;
     RECT  11.916 77.351 14.382 77.515 ;
     RECT  26.712 64.987 27.198 77.521 ;
     RECT  11.916 77.515 14.85 77.645 ;
     RECT  49.032 77.387 49.122 77.645 ;
     RECT  45.615 77.161 46.818 77.659 ;
     RECT  26.64 77.521 27.486 77.701 ;
     RECT  28.26 76.747 31.158 77.701 ;
     RECT  32.076 76.649 44.802 77.791 ;
     RECT  45.615 77.659 46.926 77.791 ;
     RECT  49.032 77.645 49.086 77.819 ;
     RECT  32.076 77.791 46.926 77.837 ;
     RECT  15.876 76.577 17.262 77.927 ;
     RECT  18.18 77.035 25.038 77.963 ;
     RECT  32.076 77.837 46.89 77.963 ;
     RECT  26.64 77.701 31.194 77.971 ;
     RECT  32.076 77.963 46.782 77.971 ;
     RECT  50.616 77.009 70.974 78.089 ;
     RECT  25.848 63.528 25.866 78.091 ;
     RECT  26.64 77.971 46.782 78.091 ;
     RECT  18.54 77.963 25.038 78.133 ;
     RECT  18.54 78.133 25.074 78.197 ;
     RECT  50.796 78.089 70.974 78.269 ;
     RECT  18.615 78.197 25.074 78.367 ;
     RECT  25.848 78.091 46.782 78.367 ;
     RECT  15.912 77.927 17.262 78.467 ;
     RECT  9.036 74.849 9.054 78.503 ;
     RECT  49.068 77.819 49.086 78.503 ;
     RECT  18.615 78.367 46.782 78.809 ;
     RECT  11.916 77.645 14.202 79.007 ;
     RECT  45.615 78.809 46.782 79.349 ;
     RECT  45.615 79.349 46.278 79.511 ;
     RECT  17.244 78.467 17.262 79.619 ;
     RECT  49.86 77.387 49.878 79.717 ;
     RECT  50.832 78.269 70.974 79.717 ;
     RECT  49.86 79.717 70.974 80.329 ;
     RECT  12.096 79.007 14.202 80.393 ;
     RECT  12.096 80.393 14.166 80.429 ;
     RECT  18.615 78.809 44.802 80.429 ;
     RECT  20.88 80.429 44.802 80.591 ;
     RECT  18.615 80.429 19.854 80.789 ;
     RECT  46.728 80.671 46.746 80.897 ;
     RECT  49.86 80.329 71.19 80.941 ;
     RECT  20.88 80.591 44.514 81.095 ;
     RECT  20.88 81.095 21.942 81.131 ;
     RECT  5.112 77.315 6.822 81.239 ;
     RECT  18.615 80.789 19.674 81.671 ;
     RECT  5.652 81.239 6.822 81.707 ;
     RECT  6.696 81.707 6.822 81.743 ;
     RECT  49.86 80.941 71.226 81.751 ;
     RECT  19.656 81.671 19.674 81.905 ;
     RECT  20.88 81.131 21.834 81.941 ;
     RECT  22.68 81.095 44.514 81.977 ;
     RECT  15.912 78.467 16.506 82.211 ;
     RECT  5.652 81.707 5.706 82.247 ;
     RECT  12.24 80.429 14.166 82.319 ;
     RECT  20.88 81.941 21.618 82.589 ;
     RECT  6.804 81.743 6.822 82.751 ;
     RECT  12.24 82.319 13.554 82.781 ;
     RECT  45.615 79.511 45.954 82.823 ;
     RECT  45.615 82.823 45.897 83.083 ;
     RECT  5.688 82.247 5.706 83.117 ;
     RECT  13.104 82.781 13.554 83.129 ;
     RECT  22.68 81.977 44.478 83.191 ;
     RECT  45.504 83.083 45.897 83.191 ;
     RECT  18.615 81.671 18.897 83.263 ;
     RECT  15.912 82.211 15.93 83.399 ;
     RECT  49.86 81.751 71.334 83.461 ;
     RECT  20.88 82.589 20.898 83.561 ;
     RECT  22.68 83.191 45.897 83.569 ;
     RECT  49.86 83.461 71.442 83.641 ;
     RECT  49.86 83.641 71.874 83.731 ;
     RECT  72.615 65.863 72.897 83.731 ;
     RECT  49.86 83.731 72.897 83.789 ;
     RECT  49.86 83.789 71.874 83.795 ;
     RECT  18.615 83.263 18.954 83.803 ;
     RECT  13.215 83.129 13.554 83.867 ;
     RECT  18.615 83.803 18.99 83.933 ;
     RECT  12.24 82.781 12.258 83.939 ;
     RECT  49.86 83.795 71.658 83.939 ;
     RECT  2.415 43.295 2.697 83.987 ;
     RECT  7.815 76.037 8.097 83.987 ;
     RECT  13.215 83.867 13.497 83.987 ;
     RECT  18.615 83.933 18.897 83.987 ;
     RECT  22.644 83.569 45.897 83.987 ;
     RECT  72.615 83.789 72.897 83.987 ;
     RECT  78.015 65.863 78.297 83.987 ;
     RECT  83.415 65.863 83.697 83.987 ;
     RECT  88.815 65.863 89.097 83.987 ;
     RECT  94.215 65.863 94.497 83.987 ;
     RECT  99.615 65.863 99.897 83.987 ;
     RECT  105.015 65.863 105.297 83.987 ;
     RECT  110.415 65.863 110.697 83.987 ;
     RECT  115.815 65.863 116.097 83.987 ;
     RECT  121.215 54.473 121.497 83.987 ;
     RECT  126.615 2.413 126.897 83.987 ;
     RECT  132.015 2.413 132.297 83.987 ;
     RECT  137.415 64.445 137.697 83.987 ;
     RECT  22.644 83.987 45.705 84.137 ;
     RECT  22.644 84.137 23.166 84.173 ;
     RECT  22.644 84.173 23.022 84.181 ;
     RECT  24.015 84.137 45.705 84.221 ;
     RECT  2.415 83.987 2.505 84.257 ;
     RECT  7.815 83.987 7.905 84.257 ;
     RECT  13.215 83.987 13.305 84.257 ;
     RECT  18.615 83.987 18.705 84.257 ;
     RECT  24.015 84.221 42.894 84.257 ;
     RECT  44.1 84.221 45.705 84.257 ;
     RECT  72.615 83.987 72.705 84.257 ;
     RECT  78.015 83.987 78.105 84.257 ;
     RECT  83.415 83.987 83.505 84.257 ;
     RECT  88.815 83.987 88.905 84.257 ;
     RECT  94.215 83.987 94.305 84.257 ;
     RECT  99.615 83.987 99.705 84.257 ;
     RECT  105.015 83.987 105.105 84.257 ;
     RECT  110.415 83.987 110.505 84.257 ;
     RECT  115.815 83.987 115.905 84.257 ;
     RECT  121.215 83.987 121.305 84.257 ;
     RECT  126.615 83.987 126.705 84.257 ;
     RECT  132.015 83.987 132.105 84.257 ;
     RECT  137.415 83.987 137.505 84.257 ;
     RECT  44.1 84.257 44.982 84.269 ;
     RECT  44.1 84.269 44.406 84.299 ;
     RECT  50.328 83.939 71.658 84.299 ;
     RECT  50.328 84.299 70.758 84.317 ;
     RECT  22.572 84.181 23.022 84.335 ;
     RECT  44.1 84.299 44.118 84.335 ;
     RECT  70.74 84.317 70.758 84.335 ;
     RECT  71.64 84.299 71.658 84.371 ;
     RECT  24.336 84.257 42.894 84.461 ;
     RECT  50.328 84.317 69.786 84.989 ;
     RECT  22.572 84.335 22.59 85.229 ;
     RECT  24.336 84.461 42.786 85.517 ;
     RECT  50.832 84.989 69.786 85.517 ;
     RECT  24.48 85.517 42.786 86.268 ;
     RECT  51.48 85.517 69.786 86.268 ;
     RECT  61.596 86.268 61.686 86.333 ;
    LAYER M4 ;
     RECT  0.205 43.2 0.245 43.32 ;
     RECT  0.245 43.296 2.408 43.32 ;
     RECT  2.408 2.148 2.512 84.252 ;
     RECT  2.512 2.418 2.704 83.982 ;
     RECT  2.704 43.2 4.643 43.224 ;
     RECT  4.589 39.36 4.673 39.384 ;
     RECT  4.597 42.144 5.425 42.168 ;
     RECT  5.389 35.808 5.461 35.832 ;
     RECT  5.461 35.424 5.509 35.832 ;
     RECT  5.509 34.656 5.533 35.832 ;
     RECT  5.509 67.584 5.557 67.608 ;
     RECT  5.101 29.616 5.605 29.64 ;
     RECT  5.353 38.64 5.605 38.664 ;
     RECT  5.533 34.416 5.641 35.832 ;
     RECT  5.605 38.304 6.037 38.664 ;
     RECT  5.677 83.088 6.037 83.112 ;
     RECT  6.037 37.872 6.109 38.664 ;
     RECT  6.085 45.84 6.109 45.864 ;
     RECT  5.425 42.144 6.133 42.84 ;
     RECT  6.085 70.512 6.133 70.536 ;
     RECT  6.109 37.872 6.193 38.808 ;
     RECT  6.229 54.96 6.661 54.984 ;
     RECT  6.133 41.712 6.709 42.84 ;
     RECT  5.677 33.36 6.757 33.384 ;
     RECT  5.641 34.368 6.757 35.832 ;
     RECT  6.649 80.88 6.757 80.904 ;
     RECT  6.037 83.088 6.757 83.64 ;
     RECT  5.605 29.616 6.793 29.832 ;
     RECT  6.793 29.52 6.805 29.832 ;
     RECT  6.109 45.264 6.829 45.864 ;
     RECT  6.709 74.976 7.381 75 ;
     RECT  6.709 41.712 7.621 43.416 ;
     RECT  6.829 44.64 7.621 45.864 ;
     RECT  7.621 73.872 7.669 73.896 ;
     RECT  6.229 7.68 7.808 7.704 ;
     RECT  5.653 9.6 7.808 9.624 ;
     RECT  2.704 20.832 7.808 20.856 ;
     RECT  5.557 25.44 7.808 25.464 ;
     RECT  6.805 29.52 7.808 30.12 ;
     RECT  6.757 33.36 7.808 35.832 ;
     RECT  6.193 37.872 7.808 38.76 ;
     RECT  7.381 40.032 7.808 40.056 ;
     RECT  7.621 41.712 7.808 45.864 ;
     RECT  6.721 53.04 7.808 53.064 ;
     RECT  6.661 54.864 7.808 54.984 ;
     RECT  5.653 58.704 7.808 58.728 ;
     RECT  6.217 60.816 7.808 60.84 ;
     RECT  5.557 67.584 7.808 68.184 ;
     RECT  6.133 70.368 7.808 70.536 ;
     RECT  7.669 73.584 7.808 73.896 ;
     RECT  7.381 74.976 7.808 75.768 ;
     RECT  5.605 77.424 7.808 77.448 ;
     RECT  6.757 80.256 7.808 80.904 ;
     RECT  6.757 83.088 7.808 84.072 ;
     RECT  7.808 2.148 7.912 84.252 ;
     RECT  7.912 2.418 8.104 84.072 ;
     RECT  8.104 24.768 9.253 27.192 ;
     RECT  8.104 53.04 9.253 53.064 ;
     RECT  8.104 29.52 9.349 30.12 ;
     RECT  8.104 31.248 9.349 31.272 ;
     RECT  8.104 33.36 9.349 45.864 ;
     RECT  8.104 70.368 9.445 71.16 ;
     RECT  9.349 57.6 9.529 57.624 ;
     RECT  8.104 66.528 9.541 66.552 ;
     RECT  8.104 67.584 9.541 68.184 ;
     RECT  8.104 77.04 9.589 77.688 ;
     RECT  9.349 33.36 9.673 45.96 ;
     RECT  9.349 29.52 9.925 31.272 ;
     RECT  9.253 52.464 9.925 53.064 ;
     RECT  9.541 66.528 9.973 68.184 ;
     RECT  9.973 66.528 10.021 68.424 ;
     RECT  10.021 66.528 10.117 68.712 ;
     RECT  10.117 66.528 10.204 68.76 ;
     RECT  9.253 24.576 10.213 27.192 ;
     RECT  8.104 73.488 10.213 75.768 ;
     RECT  9.589 77.04 10.213 77.928 ;
     RECT  10.213 24.096 10.645 27.192 ;
     RECT  9.529 57.312 10.645 57.624 ;
     RECT  10.213 73.488 10.741 77.928 ;
     RECT  10.204 66.528 10.789 68.712 ;
     RECT  8.104 58.704 10.825 58.776 ;
     RECT  10.825 58.704 10.865 59.016 ;
     RECT  10.645 24.096 11.077 27.384 ;
     RECT  10.789 66 11.125 68.712 ;
     RECT  9.445 69.792 11.173 71.16 ;
     RECT  8.104 72.192 11.173 72.216 ;
     RECT  10.645 57.024 11.189 57.624 ;
     RECT  8.104 80.256 11.221 80.904 ;
     RECT  9.925 29.52 11.365 31.752 ;
     RECT  10.741 73.488 11.365 78.12 ;
     RECT  11.221 79.536 11.365 80.904 ;
     RECT  11.365 29.52 11.725 31.992 ;
     RECT  9.673 33.024 11.725 45.96 ;
     RECT  11.189 57.024 11.729 57.336 ;
     RECT  11.221 49.536 11.749 49.56 ;
     RECT  11.077 24.096 11.833 27.912 ;
     RECT  11.173 69.792 11.845 72.216 ;
     RECT  11.365 73.488 11.845 80.904 ;
     RECT  9.925 51.552 11.909 53.064 ;
     RECT  11.749 49.536 11.941 50.184 ;
     RECT  11.845 69.792 11.941 80.904 ;
     RECT  11.909 51.552 12.017 51.576 ;
     RECT  11.729 57.312 12.157 57.336 ;
     RECT  10.865 58.752 12.157 59.016 ;
     RECT  8.104 54.864 12.229 54.984 ;
     RECT  11.797 47.664 12.277 47.688 ;
     RECT  8.104 60.816 12.301 60.84 ;
     RECT  11.125 65.712 12.373 68.712 ;
     RECT  11.941 69.792 12.373 81.192 ;
     RECT  12.229 54.768 12.409 54.984 ;
     RECT  11.833 23.856 12.421 27.912 ;
     RECT  12.409 54.768 12.445 55.56 ;
     RECT  12.373 65.712 12.481 81.96 ;
     RECT  8.104 83.088 12.481 84.072 ;
     RECT  12.445 54.72 12.733 55.56 ;
     RECT  12.277 47.664 12.805 47.928 ;
     RECT  8.104 61.872 12.805 61.896 ;
     RECT  12.157 57.312 12.841 59.016 ;
     RECT  12.301 60.816 12.913 60.888 ;
     RECT  12.805 61.872 12.913 62.232 ;
     RECT  12.421 23.664 12.949 27.912 ;
     RECT  11.909 52.752 12.949 53.064 ;
     RECT  12.841 57.312 12.949 59.064 ;
     RECT  8.104 7.68 13.045 7.704 ;
     RECT  12.733 54.72 13.052 55.992 ;
     RECT  12.949 56.976 13.052 59.064 ;
     RECT  13.045 7.104 13.208 7.704 ;
     RECT  8.104 9.6 13.208 9.624 ;
     RECT  8.104 20.832 13.208 22.104 ;
     RECT  12.949 23.664 13.208 28.296 ;
     RECT  11.725 29.52 13.208 45.96 ;
     RECT  12.805 47.088 13.208 47.928 ;
     RECT  11.941 49.008 13.208 50.184 ;
     RECT  12.949 52.032 13.208 53.064 ;
     RECT  13.052 54.72 13.208 59.064 ;
     RECT  12.913 60.816 13.208 62.232 ;
     RECT  8.104 63.504 13.208 63.528 ;
     RECT  12.481 65.712 13.208 84.072 ;
     RECT  13.208 2.148 13.312 84.252 ;
     RECT  13.312 2.418 13.504 84.072 ;
     RECT  13.504 23.616 14.533 28.296 ;
     RECT  13.504 29.28 14.533 47.928 ;
     RECT  13.504 54.576 14.929 59.736 ;
     RECT  13.504 60.816 14.929 62.232 ;
     RECT  14.929 54.576 15.001 62.232 ;
     RECT  13.504 7.104 15.493 8.232 ;
     RECT  13.504 49.728 15.493 53.064 ;
     RECT  15.001 54.096 15.493 62.232 ;
     RECT  14.485 64.656 15.781 64.68 ;
     RECT  13.504 65.808 15.781 84.072 ;
     RECT  15.493 49.728 15.865 62.232 ;
     RECT  15.493 6.624 16.837 8.232 ;
     RECT  13.504 9.6 16.837 9.624 ;
     RECT  16.837 6.624 16.885 9.624 ;
     RECT  13.504 63.504 16.933 63.528 ;
     RECT  15.781 64.656 16.933 84.072 ;
     RECT  15.865 49.728 18.205 62.328 ;
     RECT  16.933 63.504 18.205 84.072 ;
     RECT  16.225 19.632 18.277 19.656 ;
     RECT  16.885 6.624 18.608 10.152 ;
     RECT  16.789 12.768 18.608 12.792 ;
     RECT  18.085 14.448 18.608 14.472 ;
     RECT  18.277 19.632 18.608 19.848 ;
     RECT  13.504 20.832 18.608 22.104 ;
     RECT  14.533 23.616 18.608 47.928 ;
     RECT  18.205 49.728 18.608 84.072 ;
     RECT  18.608 2.148 18.712 84.252 ;
     RECT  18.712 2.418 18.904 84.072 ;
     RECT  18.904 14.352 19.001 14.472 ;
     RECT  18.904 19.632 20.149 19.848 ;
     RECT  20.149 19.584 20.341 19.848 ;
     RECT  18.904 20.832 20.341 22.104 ;
     RECT  18.904 12.576 20.437 12.888 ;
     RECT  20.437 11.664 20.821 12.888 ;
     RECT  19.001 14.352 20.821 14.376 ;
     RECT  18.904 6.624 21.013 10.44 ;
     RECT  20.341 19.584 21.349 22.104 ;
     RECT  21.349 19.344 22.213 22.104 ;
     RECT  18.904 23.616 22.213 84.072 ;
     RECT  22.213 23.424 22.237 84.072 ;
     RECT  22.213 19.344 22.261 22.152 ;
     RECT  22.237 23.328 22.261 84.072 ;
     RECT  21.013 6.624 22.853 10.488 ;
     RECT  22.853 6.624 23.713 10.44 ;
     RECT  23.713 6.288 24.008 10.44 ;
     RECT  20.821 11.664 24.008 14.376 ;
     RECT  20.293 16.8 24.008 16.824 ;
     RECT  22.261 19.344 24.008 84.072 ;
     RECT  22.561 85.2 24.008 85.224 ;
     RECT  24.008 2.148 24.304 85.224 ;
     RECT  24.304 19.344 24.325 85.224 ;
     RECT  24.361 0.528 24.433 0.552 ;
     RECT  24.433 0.528 24.563 0.6 ;
     RECT  24.541 1.728 24.707 1.752 ;
     RECT  24.304 2.88 24.995 2.952 ;
     RECT  24.563 0.528 25.139 0.552 ;
     RECT  24.995 2.88 25.481 2.904 ;
     RECT  25.297 4.512 25.571 4.536 ;
     RECT  24.304 5.664 25.661 14.376 ;
     RECT  25.585 1.152 25.805 1.176 ;
     RECT  25.649 3.984 25.859 4.104 ;
     RECT  25.859 3.984 26.233 4.056 ;
     RECT  25.661 6.192 26.243 14.376 ;
     RECT  26.233 3.264 26.435 4.056 ;
     RECT  26.243 6.624 26.773 14.376 ;
     RECT  26.435 3.936 26.821 4.056 ;
     RECT  26.821 3.936 26.965 4.584 ;
     RECT  26.773 6.624 27.205 14.472 ;
     RECT  26.965 3.936 27.385 5.16 ;
     RECT  27.205 6.624 27.385 14.52 ;
     RECT  26.521 2.88 27.445 2.904 ;
     RECT  27.385 3.936 27.445 14.52 ;
     RECT  27.445 2.88 27.964 14.52 ;
     RECT  27.964 2.88 28.033 4.536 ;
     RECT  27.964 5.664 28.115 14.52 ;
     RECT  28.033 2.832 28.117 4.536 ;
     RECT  24.325 19.344 28.78 85.512 ;
     RECT  28.117 2.88 28.933 4.536 ;
     RECT  28.115 6.624 29.269 14.52 ;
     RECT  25.837 1.728 29.408 1.752 ;
     RECT  28.933 2.88 29.408 4.584 ;
     RECT  29.269 6.288 29.408 14.52 ;
     RECT  24.304 16.8 29.408 16.824 ;
     RECT  28.78 19.344 29.408 84.984 ;
     RECT  29.408 1.728 29.704 84.984 ;
     RECT  29.173 0.288 30.083 0.312 ;
     RECT  29.704 2.832 30.275 14.52 ;
     RECT  29.704 19.344 30.421 84.984 ;
     RECT  30.421 19.344 30.508 85.512 ;
     RECT  29.704 1.728 31.205 1.752 ;
     RECT  29.704 18.192 31.241 18.216 ;
     RECT  30.275 2.832 31.273 4.536 ;
     RECT  29.704 16.8 31.379 16.872 ;
     RECT  31.273 2.304 31.475 4.536 ;
     RECT  30.275 5.664 31.571 14.52 ;
     RECT  30.508 19.344 31.601 84.984 ;
     RECT  31.475 2.976 31.745 4.536 ;
     RECT  31.601 84.96 31.804 84.984 ;
     RECT  31.601 19.344 31.813 83.928 ;
     RECT  31.571 5.712 31.907 14.52 ;
     RECT  31.745 3.408 32.005 4.536 ;
     RECT  32.005 3.408 32.104 4.584 ;
     RECT  32.104 3.408 32.195 4.632 ;
     RECT  31.907 6.24 32.429 14.52 ;
     RECT  32.353 1.728 32.483 1.752 ;
     RECT  32.429 6.24 32.483 8.568 ;
     RECT  32.429 9.648 32.501 14.52 ;
     RECT  32.501 10.032 32.609 14.52 ;
     RECT  32.195 3.84 32.821 4.632 ;
     RECT  31.379 16.848 32.869 16.872 ;
     RECT  32.483 6.288 33.077 8.568 ;
     RECT  32.821 3.84 33.107 5.112 ;
     RECT  31.813 19.056 33.113 83.928 ;
     RECT  33.107 3.84 33.253 4.488 ;
     RECT  32.252 85.488 33.361 85.512 ;
     RECT  33.253 3.408 33.401 4.488 ;
     RECT  33.077 6.96 33.505 8.568 ;
     RECT  33.505 6.96 33.613 8.616 ;
     RECT  33.113 80.4 33.725 83.88 ;
     RECT  33.361 84.96 33.868 85.512 ;
     RECT  33.116 0.528 33.973 0.552 ;
     RECT  32.609 10.416 34.069 14.52 ;
     RECT  33.868 84.96 34.085 85.56 ;
     RECT  33.973 0.288 34.153 0.552 ;
     RECT  33.829 1.728 34.153 1.752 ;
     RECT  33.113 19.056 34.165 79.272 ;
     RECT  34.085 84.96 34.165 85.512 ;
     RECT  34.165 18.48 34.309 79.272 ;
     RECT  33.725 80.4 34.309 83.448 ;
     RECT  33.613 6.96 34.369 9.288 ;
     RECT  34.069 10.416 34.369 14.712 ;
     RECT  34.153 0.288 34.549 1.752 ;
     RECT  33.401 3.648 34.549 4.488 ;
     RECT  34.165 84.816 34.553 85.512 ;
     RECT  34.081 5.712 34.657 5.736 ;
     RECT  34.369 6.96 34.657 14.712 ;
     RECT  34.309 18.48 34.741 83.448 ;
     RECT  34.553 84.816 34.741 85.08 ;
     RECT  34.657 5.712 34.765 14.712 ;
     RECT  30.709 15.696 34.765 15.72 ;
     RECT  34.549 0.288 34.808 2.04 ;
     RECT  34.549 3.408 34.808 4.536 ;
     RECT  34.765 5.712 34.808 15.72 ;
     RECT  32.869 16.848 34.808 17.448 ;
     RECT  34.741 18.48 34.808 85.08 ;
     RECT  34.808 0.288 35.104 85.08 ;
     RECT  35.104 0.288 35.153 5.256 ;
     RECT  35.153 0.192 35.237 5.256 ;
     RECT  35.104 18.48 35.267 85.08 ;
     RECT  35.237 0.336 35.273 5.256 ;
     RECT  35.273 0.336 35.315 4.632 ;
     RECT  35.267 82.944 35.315 83.592 ;
     RECT  35.267 84.912 35.315 85.08 ;
     RECT  35.315 0.336 35.459 2.28 ;
     RECT  35.459 1.152 35.507 2.28 ;
     RECT  35.267 18.48 35.561 81.624 ;
     RECT  35.104 7.968 35.705 8.184 ;
     RECT  35.315 82.944 35.777 83.208 ;
     RECT  35.104 10.8 35.885 11.448 ;
     RECT  35.507 1.152 36.083 1.752 ;
     RECT  35.885 11.376 36.085 11.448 ;
     RECT  35.104 12.432 36.085 13.272 ;
     RECT  35.104 6.288 36.092 6.312 ;
     RECT  36.092 5.904 36.133 6.312 ;
     RECT  35.104 9.744 36.133 9.768 ;
     RECT  36.085 11.376 36.173 13.272 ;
     RECT  35.315 84.912 36.173 84.984 ;
     RECT  36.133 5.904 36.179 6.648 ;
     RECT  35.705 8.16 36.179 8.184 ;
     RECT  36.173 11.376 36.245 11.496 ;
     RECT  36.245 11.376 36.281 11.448 ;
     RECT  36.133 9.744 36.309 10.008 ;
     RECT  35.315 3.408 36.325 4.632 ;
     RECT  35.777 83.184 36.353 83.208 ;
     RECT  36.173 12.48 36.421 13.272 ;
     RECT  35.104 14.496 36.421 15.576 ;
     RECT  36.173 84.912 36.449 84.936 ;
     RECT  35.561 80.256 36.457 81.624 ;
     RECT  36.457 80.256 36.515 82.104 ;
     RECT  36.325 3.024 36.668 4.632 ;
     RECT  36.668 2.88 36.737 4.632 ;
     RECT  36.737 2.88 36.755 4.776 ;
     RECT  36.281 11.424 36.785 11.448 ;
     RECT  35.561 18.48 36.845 79.272 ;
     RECT  36.515 80.784 36.853 82.104 ;
     RECT  36.845 18.48 36.929 79.8 ;
     RECT  36.421 12.48 36.961 15.576 ;
     RECT  35.104 16.848 36.961 17.448 ;
     RECT  36.755 2.928 36.997 4.776 ;
     RECT  36.309 9.744 37.073 9.768 ;
     RECT  36.997 2.928 37.084 5.16 ;
     RECT  37.084 3.408 37.091 5.16 ;
     RECT  36.961 12.48 37.093 17.448 ;
     RECT  36.929 18.48 37.093 79.704 ;
     RECT  37.093 12.48 37.145 79.704 ;
     RECT  36.449 84.336 37.148 84.936 ;
     RECT  37.091 5.088 37.196 5.16 ;
     RECT  36.179 6.288 37.196 6.648 ;
     RECT  37.196 5.088 37.283 6.648 ;
     RECT  36.853 80.784 37.283 82.776 ;
     RECT  37.145 13.632 37.325 79.704 ;
     RECT  37.285 9.12 37.379 9.144 ;
     RECT  37.148 84.336 37.721 84.984 ;
     RECT  37.145 12.48 37.789 12.552 ;
     RECT  36.083 1.728 37.825 1.752 ;
     RECT  37.825 1.104 37.955 1.752 ;
     RECT  37.909 10.272 38.009 10.296 ;
     RECT  37.789 12.192 38.041 12.552 ;
     RECT  37.325 16.272 38.117 79.704 ;
     RECT  38.117 16.272 38.147 18.216 ;
     RECT  37.721 84.384 38.197 84.984 ;
     RECT  37.091 3.408 38.221 4.056 ;
     RECT  37.283 5.088 38.221 5.16 ;
     RECT  38.117 19.344 38.221 79.704 ;
     RECT  37.283 80.784 38.221 82.104 ;
     RECT  38.221 3.408 38.245 5.16 ;
     RECT  38.245 2.88 38.396 5.16 ;
     RECT  37.283 6.24 38.396 6.648 ;
     RECT  38.221 19.344 38.437 82.104 ;
     RECT  37.621 83.136 38.437 83.208 ;
     RECT  38.396 2.88 38.483 6.648 ;
     RECT  37.325 13.632 38.653 14.664 ;
     RECT  37.955 1.728 38.965 1.752 ;
     RECT  38.483 2.88 38.965 5.64 ;
     RECT  38.965 1.728 39.011 5.64 ;
     RECT  38.197 84.384 39.059 85.512 ;
     RECT  38.437 19.344 39.068 83.208 ;
     RECT  38.653 13.536 39.085 14.664 ;
     RECT  38.147 16.272 39.085 17.928 ;
     RECT  39.011 1.728 39.089 5.16 ;
     RECT  38.977 10.848 39.121 10.872 ;
     RECT  39.089 1.728 39.251 5.112 ;
     RECT  38.483 6.624 39.265 6.648 ;
     RECT  39.121 9.936 39.337 10.872 ;
     RECT  38.041 12.144 39.337 12.552 ;
     RECT  39.059 85.488 39.493 85.512 ;
     RECT  39.337 9.936 39.548 12.552 ;
     RECT  39.085 13.536 39.548 17.928 ;
     RECT  39.493 85.488 39.58 85.56 ;
     RECT  39.58 85.488 39.809 85.512 ;
     RECT  39.149 8.544 39.913 8.568 ;
     RECT  39.548 9.936 39.913 17.928 ;
     RECT  39.877 0.528 39.925 0.552 ;
     RECT  39.925 0.528 39.973 0.648 ;
     RECT  39.973 0.384 40.021 0.648 ;
     RECT  39.913 8.544 40.021 17.928 ;
     RECT  40.021 0.288 40.115 0.648 ;
     RECT  39.251 2.148 40.208 5.112 ;
     RECT  39.265 6.624 40.208 6.84 ;
     RECT  40.021 8.496 40.208 17.928 ;
     RECT  39.068 19.344 40.208 84.36 ;
     RECT  40.208 2.148 40.213 84.36 ;
     RECT  40.115 0.288 40.259 0.552 ;
     RECT  40.259 0.384 40.403 0.552 ;
     RECT  40.213 2.148 40.504 85.032 ;
     RECT  40.504 82.992 40.601 85.032 ;
     RECT  40.504 9.6 40.665 14.664 ;
     RECT  40.601 84.384 40.691 85.032 ;
     RECT  40.504 2.148 40.787 4.44 ;
     RECT  40.787 2.88 40.835 4.44 ;
     RECT  40.835 2.88 40.925 4.248 ;
     RECT  40.504 7.872 41.033 8.568 ;
     RECT  41.065 1.728 41.149 1.752 ;
     RECT  40.504 5.712 41.219 6.888 ;
     RECT  41.219 5.712 41.315 5.736 ;
     RECT  41.219 6.816 41.401 6.888 ;
     RECT  40.504 19.344 41.497 81.672 ;
     RECT  40.601 82.992 41.569 83.208 ;
     RECT  40.691 84.384 41.569 84.984 ;
     RECT  41.497 19.344 41.641 81.912 ;
     RECT  41.569 82.992 41.753 84.984 ;
     RECT  40.665 10.032 41.893 14.664 ;
     RECT  40.504 15.696 41.893 17.928 ;
     RECT  41.641 19.296 41.893 81.912 ;
     RECT  40.403 0.528 41.941 0.552 ;
     RECT  41.893 10.032 41.965 81.912 ;
     RECT  41.753 82.992 41.965 84.552 ;
     RECT  40.925 3.36 42.005 4.248 ;
     RECT  42.005 3.36 42.041 4.152 ;
     RECT  41.941 0.288 42.083 0.552 ;
     RECT  42.109 2.832 42.254 2.904 ;
     RECT  41.033 7.872 42.293 8.424 ;
     RECT  41.965 10.032 42.323 84.552 ;
     RECT  42.041 3.936 42.365 4.152 ;
     RECT  42.323 10.032 42.373 17.976 ;
     RECT  42.365 3.936 42.409 3.96 ;
     RECT  42.229 1.728 42.509 1.752 ;
     RECT  42.323 19.248 42.755 84.552 ;
     RECT  42.517 1.152 42.869 1.176 ;
     RECT  41.401 6.816 42.869 6.84 ;
     RECT  42.755 19.248 42.905 84.456 ;
     RECT  42.293 8.4 42.941 8.424 ;
     RECT  42.254 2.88 43.085 2.904 ;
     RECT  42.373 13.008 43.265 17.976 ;
     RECT  43.265 15.696 43.981 17.976 ;
     RECT  42.905 19.248 43.981 84.264 ;
     RECT  42.373 10.032 44.677 11.976 ;
     RECT  43.265 13.008 44.677 14.664 ;
     RECT  43.981 15.696 44.993 84.264 ;
     RECT  44.677 10.032 45.608 14.664 ;
     RECT  44.993 15.696 45.608 84.252 ;
     RECT  45.608 2.148 45.712 84.252 ;
     RECT  45.712 2.418 45.904 83.982 ;
     RECT  45.904 15.696 46.835 83.496 ;
     RECT  45.904 10.032 47.873 11.976 ;
     RECT  47.873 10.032 49.201 11.688 ;
     RECT  45.904 13.008 49.309 14.664 ;
     RECT  46.835 19.248 50.209 83.496 ;
     RECT  50.317 84.96 50.821 84.984 ;
     RECT  49.201 9.792 51.008 11.688 ;
     RECT  49.309 12.768 51.008 14.664 ;
     RECT  46.835 15.696 51.008 17.928 ;
     RECT  50.209 19.248 51.008 83.64 ;
     RECT  50.821 84.96 51.008 85.512 ;
     RECT  51.008 2.148 51.112 85.512 ;
     RECT  51.112 2.418 51.304 83.982 ;
     RECT  51.304 19.248 51.833 83.64 ;
     RECT  51.112 84.96 51.925 85.512 ;
     RECT  51.925 84.96 52.012 85.56 ;
     RECT  51.833 82.656 52.229 83.64 ;
     RECT  52.229 82.704 52.441 83.64 ;
     RECT  52.441 82.704 52.657 83.688 ;
     RECT  52.657 82.704 52.741 83.832 ;
     RECT  52.741 82.704 52.979 83.688 ;
     RECT  52.012 84.96 53.077 85.512 ;
     RECT  53.077 84.864 53.219 85.512 ;
     RECT  51.833 19.248 53.315 81.672 ;
     RECT  52.979 82.704 53.509 83.256 ;
     RECT  51.304 15.696 53.557 17.928 ;
     RECT  53.315 19.248 53.557 81.48 ;
     RECT  53.557 15.696 53.561 81.48 ;
     RECT  53.509 82.656 53.596 83.256 ;
     RECT  53.561 15.696 53.699 81.048 ;
     RECT  53.699 19.248 53.893 81.048 ;
     RECT  53.219 84.912 54.493 85.512 ;
     RECT  54.493 84.912 54.611 85.608 ;
     RECT  53.699 15.696 54.709 17.928 ;
     RECT  54.277 82.08 54.805 82.104 ;
     RECT  53.596 83.232 54.805 83.256 ;
     RECT  53.893 19.248 55.061 81 ;
     RECT  54.805 82.08 55.061 83.256 ;
     RECT  54.611 84.912 55.237 85.512 ;
     RECT  55.061 19.248 55.321 83.256 ;
     RECT  55.237 84.816 55.397 85.512 ;
     RECT  55.397 84.96 55.469 85.512 ;
     RECT  55.469 85.488 56.077 85.512 ;
     RECT  56.077 85.488 56.243 85.56 ;
     RECT  55.321 19.248 56.389 83.832 ;
     RECT  51.304 9.792 56.408 11.688 ;
     RECT  51.304 12.768 56.408 14.664 ;
     RECT  54.709 15.696 56.408 17.976 ;
     RECT  56.389 19.248 56.408 84.408 ;
     RECT  56.408 2.148 56.509 84.408 ;
     RECT  56.243 85.488 56.509 85.512 ;
     RECT  56.509 2.148 56.512 85.512 ;
     RECT  56.512 2.418 56.579 85.512 ;
     RECT  56.579 2.418 56.704 85.032 ;
     RECT  56.704 81.6 56.873 85.032 ;
     RECT  56.873 81.648 57.053 85.032 ;
     RECT  57.053 81.984 57.347 85.032 ;
     RECT  57.347 84.96 57.829 85.032 ;
     RECT  56.704 19.248 57.913 80.424 ;
     RECT  57.829 84.96 57.989 85.512 ;
     RECT  57.347 81.984 58.313 83.592 ;
     RECT  57.913 19.248 58.345 80.904 ;
     RECT  58.313 81.984 58.345 83.4 ;
     RECT  57.989 84.96 58.381 85.032 ;
     RECT  58.345 19.248 58.673 83.4 ;
     RECT  58.381 84.912 58.693 85.032 ;
     RECT  56.704 15.696 58.705 17.928 ;
     RECT  58.693 84.816 58.993 85.032 ;
     RECT  58.993 84.816 59.413 85.512 ;
     RECT  58.673 19.248 59.653 83.256 ;
     RECT  59.413 84.384 59.653 85.512 ;
     RECT  59.653 19.248 59.789 85.512 ;
     RECT  59.789 84.384 60.073 85.512 ;
     RECT  60.073 84.384 60.179 85.56 ;
     RECT  59.789 19.248 60.653 83.304 ;
     RECT  60.653 68.112 60.689 83.304 ;
     RECT  60.689 70.368 61.333 83.304 ;
     RECT  56.704 9.792 61.808 11.688 ;
     RECT  56.704 12.768 61.808 14.664 ;
     RECT  58.705 15.696 61.808 18.216 ;
     RECT  60.653 19.248 61.808 67.032 ;
     RECT  60.689 68.112 61.808 69.24 ;
     RECT  61.333 70.368 61.808 83.352 ;
     RECT  60.179 84.384 61.808 85.512 ;
     RECT  61.808 2.148 61.912 85.512 ;
     RECT  61.912 2.418 62.104 85.512 ;
     RECT  62.104 70.368 62.201 85.512 ;
     RECT  62.201 70.368 62.381 83.928 ;
     RECT  62.104 12.768 62.819 66.792 ;
     RECT  62.201 84.912 62.915 85.512 ;
     RECT  62.381 70.368 63.181 83.832 ;
     RECT  62.915 84.912 63.277 84.984 ;
     RECT  63.277 84.864 63.539 84.984 ;
     RECT  62.104 68.112 63.785 69.24 ;
     RECT  63.181 70.368 64.073 83.256 ;
     RECT  64.073 70.944 64.153 83.256 ;
     RECT  63.785 68.64 64.181 69.24 ;
     RECT  64.153 70.944 64.361 83.16 ;
     RECT  64.181 68.784 64.397 69.24 ;
     RECT  63.539 84.96 64.429 84.984 ;
     RECT  64.361 72.768 64.433 83.16 ;
     RECT  64.429 84.96 64.885 85.512 ;
     RECT  64.433 72.768 65.009 82.872 ;
     RECT  62.819 19.248 65.189 66.504 ;
     RECT  64.885 84.384 65.189 85.512 ;
     RECT  64.397 68.784 65.297 68.808 ;
     RECT  65.009 72.768 65.297 79.848 ;
     RECT  65.009 80.976 65.509 82.872 ;
     RECT  64.361 70.944 65.765 71.784 ;
     RECT  65.765 71.184 65.797 71.784 ;
     RECT  65.297 72.768 65.797 79.224 ;
     RECT  65.797 71.184 65.873 79.224 ;
     RECT  65.873 71.184 65.881 74.088 ;
     RECT  65.189 84.912 65.981 85.512 ;
     RECT  65.509 80.976 66.017 83.256 ;
     RECT  65.881 72.768 66.125 74.088 ;
     RECT  66.017 80.976 66.205 82.776 ;
     RECT  65.873 75.264 66.581 79.224 ;
     RECT  66.581 75.264 66.697 79.272 ;
     RECT  66.337 80.352 66.697 80.472 ;
     RECT  66.037 83.808 67.093 83.832 ;
     RECT  65.981 84.96 67.093 85.512 ;
     RECT  62.104 9.792 67.208 11.688 ;
     RECT  62.819 12.768 67.208 14.664 ;
     RECT  62.819 15.696 67.208 18.216 ;
     RECT  65.189 19.248 67.208 65.688 ;
     RECT  65.881 71.184 67.208 71.784 ;
     RECT  66.125 72.768 67.208 73.8 ;
     RECT  66.697 75.264 67.208 80.472 ;
     RECT  66.205 81.504 67.208 82.776 ;
     RECT  67.093 83.808 67.208 85.512 ;
     RECT  67.208 2.148 67.312 85.512 ;
     RECT  67.312 2.418 67.504 85.512 ;
     RECT  67.504 71.616 67.619 71.64 ;
     RECT  67.504 81.6 67.619 85.512 ;
     RECT  67.619 82.08 67.637 85.512 ;
     RECT  67.637 82.08 67.781 84.936 ;
     RECT  67.504 73.248 68.147 73.992 ;
     RECT  67.504 75.36 68.569 79.272 ;
     RECT  68.147 73.248 68.573 73.56 ;
     RECT  68.569 75.36 68.573 80.088 ;
     RECT  67.781 82.08 68.573 84.552 ;
     RECT  68.573 82.08 68.821 84.408 ;
     RECT  68.78 71.76 68.867 71.784 ;
     RECT  68.573 79.152 68.893 80.088 ;
     RECT  68.821 81.504 68.893 84.408 ;
     RECT  68.893 79.152 68.969 84.408 ;
     RECT  68.573 75.36 69.077 77.832 ;
     RECT  69.077 75.36 69.221 77.112 ;
     RECT  68.969 83.616 69.329 84.408 ;
     RECT  68.969 79.152 69.365 82.104 ;
     RECT  69.365 79.152 69.443 80.424 ;
     RECT  69.365 81.504 69.491 82.104 ;
     RECT  68.573 73.296 69.509 73.56 ;
     RECT  69.491 81.504 69.509 81.528 ;
     RECT  69.443 80.4 69.532 80.424 ;
     RECT  69.221 75.36 69.617 76.584 ;
     RECT  69.509 73.536 69.653 73.56 ;
     RECT  69.617 75.36 69.761 76.344 ;
     RECT  69.761 75.36 69.781 75.384 ;
     RECT  69.781 74.64 69.827 75.384 ;
     RECT  69.827 74.64 69.869 74.664 ;
     RECT  69.329 83.616 70.481 84.312 ;
     RECT  69.443 79.152 70.739 79.176 ;
     RECT  70.481 83.616 71.417 84.264 ;
     RECT  71.417 83.616 71.453 83.784 ;
     RECT  67.504 9.792 72.608 11.688 ;
     RECT  67.504 12.768 72.608 14.664 ;
     RECT  67.504 15.696 72.608 18.216 ;
     RECT  67.504 19.248 72.608 65.688 ;
     RECT  71.453 83.76 72.608 83.784 ;
     RECT  72.608 2.148 72.712 84.252 ;
     RECT  72.712 2.418 72.904 83.982 ;
     RECT  72.904 9.792 78.008 11.688 ;
     RECT  72.904 12.768 78.008 14.664 ;
     RECT  72.904 15.696 78.008 18.216 ;
     RECT  72.904 19.248 78.008 65.688 ;
     RECT  78.008 2.148 78.112 84.252 ;
     RECT  78.112 2.418 78.304 83.982 ;
     RECT  78.304 9.792 83.408 11.688 ;
     RECT  78.304 12.768 83.408 14.664 ;
     RECT  78.304 15.696 83.408 18.216 ;
     RECT  78.304 19.248 83.408 65.688 ;
     RECT  83.408 2.148 83.512 84.252 ;
     RECT  83.512 2.418 83.704 83.982 ;
     RECT  83.704 9.792 88.808 11.688 ;
     RECT  83.704 12.768 88.808 14.664 ;
     RECT  83.704 15.696 88.808 18.216 ;
     RECT  83.704 19.248 88.808 65.688 ;
     RECT  88.808 2.148 88.912 84.252 ;
     RECT  88.912 2.418 89.104 83.982 ;
     RECT  89.104 9.792 94.208 11.688 ;
     RECT  89.104 12.768 94.208 14.664 ;
     RECT  89.104 15.696 94.208 18.216 ;
     RECT  89.104 19.248 94.208 65.688 ;
     RECT  94.208 2.148 94.312 84.252 ;
     RECT  94.312 2.418 94.504 83.982 ;
     RECT  94.504 9.792 99.608 11.688 ;
     RECT  94.504 12.768 99.608 14.664 ;
     RECT  94.504 15.696 99.608 18.216 ;
     RECT  94.504 19.248 99.608 65.688 ;
     RECT  99.608 2.148 99.712 84.252 ;
     RECT  99.712 2.418 99.904 83.982 ;
     RECT  99.904 9.792 105.008 11.688 ;
     RECT  99.904 12.768 105.008 14.664 ;
     RECT  99.904 15.696 105.008 18.216 ;
     RECT  99.904 19.248 105.008 65.688 ;
     RECT  105.008 2.148 105.112 84.252 ;
     RECT  105.112 2.418 105.304 83.982 ;
     RECT  105.304 9.792 110.408 11.688 ;
     RECT  105.304 12.768 110.408 14.664 ;
     RECT  105.304 15.696 110.408 18.216 ;
     RECT  105.304 19.248 110.408 65.688 ;
     RECT  110.408 2.148 110.512 84.252 ;
     RECT  110.512 2.418 110.704 83.982 ;
     RECT  110.704 15.696 114.617 18.216 ;
     RECT  110.704 9.792 115.808 11.688 ;
     RECT  110.704 12.768 115.808 14.664 ;
     RECT  114.617 15.792 115.808 18.216 ;
     RECT  110.704 19.248 115.808 65.688 ;
     RECT  115.808 2.148 115.912 84.252 ;
     RECT  115.912 2.418 116.104 83.982 ;
     RECT  116.104 19.248 117.216 65.688 ;
     RECT  116.104 15.792 117.349 18.216 ;
     RECT  117.216 19.248 117.349 22.248 ;
     RECT  117.349 15.792 117.361 22.248 ;
     RECT  117.216 23.232 117.389 62.424 ;
     RECT  117.361 15.792 117.395 22.152 ;
     RECT  117.389 23.232 117.425 62.328 ;
     RECT  117.395 15.792 117.461 22.104 ;
     RECT  117.425 57.6 117.461 62.136 ;
     RECT  116.104 12.768 117.587 14.664 ;
     RECT  116.104 9.792 117.683 11.688 ;
     RECT  117.683 10.128 117.731 11.688 ;
     RECT  117.461 15.792 117.857 22.056 ;
     RECT  117.587 12.768 118.067 12.792 ;
     RECT  117.857 19.248 118.211 22.056 ;
     RECT  117.731 10.608 118.307 11.688 ;
     RECT  117.425 23.232 118.433 56.472 ;
     RECT  118.211 19.584 118.595 22.056 ;
     RECT  117.461 57.6 118.613 60.216 ;
     RECT  117.587 13.92 118.643 14.664 ;
     RECT  118.433 23.232 118.649 28.152 ;
     RECT  118.613 58.848 118.649 60.216 ;
     RECT  118.643 14.496 118.691 14.664 ;
     RECT  118.691 14.64 118.739 14.664 ;
     RECT  117.857 15.792 118.787 18.216 ;
     RECT  118.307 10.944 118.931 11.688 ;
     RECT  118.649 23.232 119.009 28.056 ;
     RECT  118.649 59.04 119.081 60.216 ;
     RECT  118.433 29.184 119.117 56.472 ;
     RECT  118.613 57.6 119.117 57.624 ;
     RECT  119.081 59.04 119.117 59.928 ;
     RECT  119.009 27.84 119.171 28.056 ;
     RECT  118.595 19.584 119.219 21.768 ;
     RECT  117.461 61.248 119.297 62.136 ;
     RECT  119.117 29.184 119.369 56.28 ;
     RECT  119.369 32.928 119.405 56.28 ;
     RECT  119.219 19.584 119.549 21.528 ;
     RECT  119.009 23.232 119.549 26.808 ;
     RECT  119.405 33.312 119.549 56.28 ;
     RECT  119.297 61.584 119.585 62.136 ;
     RECT  119.585 62.112 119.657 62.136 ;
     RECT  119.369 29.184 119.795 31.896 ;
     RECT  119.549 23.232 119.837 24.216 ;
     RECT  119.549 20.016 119.843 21.528 ;
     RECT  119.795 29.568 119.843 31.896 ;
     RECT  118.787 16.272 119.891 18.216 ;
     RECT  119.837 23.232 119.909 24.12 ;
     RECT  118.931 11.664 119.939 11.688 ;
     RECT  119.843 29.568 119.939 31.512 ;
     RECT  119.549 25.248 119.945 26.808 ;
     RECT  119.945 25.248 119.981 26.616 ;
     RECT  119.909 23.424 119.987 24.12 ;
     RECT  119.981 26.592 120.017 26.616 ;
     RECT  119.987 23.424 120.053 24.024 ;
     RECT  120.053 23.424 120.089 23.64 ;
     RECT  120.089 23.424 120.125 23.448 ;
     RECT  119.891 16.608 121.208 18.216 ;
     RECT  119.843 20.016 121.208 21.432 ;
     RECT  119.981 25.248 121.208 25.56 ;
     RECT  119.171 27.84 121.208 27.96 ;
     RECT  119.939 30.048 121.208 31.512 ;
     RECT  119.549 33.312 121.208 51.48 ;
     RECT  119.549 52.512 121.208 56.28 ;
     RECT  119.117 59.04 121.208 59.064 ;
     RECT  117.216 63.84 121.208 65.688 ;
     RECT  121.208 2.148 121.312 84.252 ;
     RECT  121.312 2.418 121.504 83.982 ;
     RECT  121.504 63.84 126.608 65.688 ;
     RECT  126.608 2.148 126.712 84.252 ;
     RECT  126.712 2.418 126.904 83.982 ;
     RECT  126.904 63.84 132.008 65.688 ;
     RECT  132.008 2.148 132.112 84.252 ;
     RECT  132.112 2.418 132.304 83.982 ;
     RECT  132.304 63.84 137.408 65.688 ;
     RECT  137.408 2.148 137.512 84.252 ;
     RECT  137.512 2.418 137.704 83.982 ;
     RECT  137.704 63.84 138.593 65.688 ;
     RECT  138.593 63.84 138.665 65.208 ;
     RECT  138.665 63.84 138.737 63.912 ;
     RECT  138.665 65.184 138.845 65.208 ;
     RECT  138.737 63.888 139.421 63.912 ;
     RECT  140.785 62.448 141.073 62.616 ;
     RECT  140.245 60.144 141.325 60.168 ;
     RECT  141.073 62.304 141.325 62.616 ;
     RECT  141.325 60.144 141.361 60.312 ;
     RECT  141.325 62.16 141.361 62.616 ;
     RECT  141.361 60.144 141.901 60.456 ;
     RECT  141.901 60.144 142.297 60.888 ;
     RECT  142.297 59.856 142.38 60.888 ;
     RECT  141.361 62.016 142.38 62.904 ;
     RECT  142.38 59.856 142.409 59.88 ;
    LAYER M5 ;
     RECT  24.528 0.144 42.84 0.611 ;
     RECT  24.672 0.611 42.84 2.137 ;
     RECT  2.4 2.137 2.52 2.151 ;
     RECT  7.8 2.137 7.92 2.151 ;
     RECT  13.2 2.137 13.32 2.151 ;
     RECT  18.6 2.137 18.72 2.151 ;
     RECT  45.6 2.137 45.72 2.151 ;
     RECT  51 2.137 51.12 2.151 ;
     RECT  56.4 2.137 56.52 2.151 ;
     RECT  61.8 2.137 61.92 2.151 ;
     RECT  67.2 2.137 67.32 2.151 ;
     RECT  72.6 2.137 72.72 2.151 ;
     RECT  78 2.137 78.12 2.151 ;
     RECT  83.4 2.137 83.52 2.151 ;
     RECT  88.8 2.137 88.92 2.151 ;
     RECT  94.2 2.137 94.32 2.151 ;
     RECT  99.6 2.137 99.72 2.151 ;
     RECT  105 2.137 105.12 2.151 ;
     RECT  110.4 2.137 110.52 2.151 ;
     RECT  115.8 2.137 115.92 2.151 ;
     RECT  121.2 2.137 121.32 2.151 ;
     RECT  126.6 2.137 126.72 2.151 ;
     RECT  132 2.137 132.12 2.151 ;
     RECT  137.4 2.137 137.52 2.151 ;
     RECT  24 2.137 42.84 2.915 ;
     RECT  24 2.915 42.12 2.963 ;
     RECT  25.536 2.963 42.12 3.925 ;
     RECT  25.536 3.925 42.36 4.547 ;
     RECT  26.256 4.547 42.36 5.171 ;
     RECT  24 2.963 24.312 5.653 ;
     RECT  37.248 5.171 42.36 5.699 ;
     RECT  26.256 5.171 36.216 6.181 ;
     RECT  26.208 6.181 36.216 6.275 ;
     RECT  24 5.653 24.792 6.515 ;
     RECT  15.504 6.613 15.528 6.661 ;
     RECT  26.208 6.275 30.552 6.803 ;
     RECT  27.792 6.803 30.552 6.851 ;
     RECT  13.2 2.151 13.512 7.093 ;
     RECT  15.504 6.661 16.152 7.189 ;
     RECT  26.208 6.803 26.616 7.381 ;
     RECT  20.544 7.333 20.568 7.477 ;
     RECT  15.504 7.189 17.016 7.717 ;
     RECT  13.056 7.093 13.512 7.861 ;
     RECT  13.056 7.861 13.848 7.909 ;
     RECT  27.888 6.851 30.552 7.957 ;
     RECT  31.584 6.275 36.216 7.957 ;
     RECT  13.056 7.909 14.088 8.197 ;
     RECT  27.888 7.957 36.216 8.531 ;
     RECT  27.888 8.531 32.232 8.579 ;
     RECT  33.264 8.531 36.216 8.579 ;
     RECT  39.168 5.699 42.36 8.579 ;
     RECT  33.552 8.579 36.216 8.627 ;
     RECT  28.08 8.579 32.232 8.819 ;
     RECT  25.632 7.381 26.616 9.155 ;
     RECT  37.344 5.699 38.04 9.155 ;
     RECT  6.24 7.669 6.264 9.589 ;
     RECT  34.464 8.627 36.216 9.683 ;
     RECT  28.176 8.819 32.232 9.731 ;
     RECT  39.744 8.579 40.68 9.925 ;
     RECT  34.8 9.683 36.216 9.973 ;
     RECT  20.256 7.477 20.568 10.021 ;
     RECT  117.648 9.781 117.672 10.117 ;
     RECT  26.448 9.155 26.616 10.259 ;
     RECT  18.6 2.151 18.912 10.405 ;
     RECT  20.208 10.021 20.568 10.405 ;
     RECT  18.6 10.405 20.568 10.453 ;
     RECT  117.648 10.117 117.72 10.597 ;
     RECT  61.8 2.151 62.112 10.645 ;
     RECT  39.696 9.925 40.68 10.691 ;
     RECT  39.696 10.691 40.512 10.837 ;
     RECT  28.464 9.731 32.232 10.883 ;
     RECT  45.6 2.151 45.912 10.885 ;
     RECT  61.8 10.645 62.712 10.885 ;
     RECT  117.648 10.597 118.296 10.933 ;
     RECT  54.24 11.173 54.264 11.221 ;
     RECT  41.856 8.579 42.36 11.269 ;
     RECT  54.144 11.221 54.264 11.363 ;
     RECT  28.608 10.883 32.232 11.459 ;
     RECT  39.552 10.837 40.512 11.795 ;
     RECT  39.6 11.795 40.512 11.941 ;
     RECT  41.568 11.269 42.36 11.941 ;
     RECT  37.872 9.155 38.04 12.467 ;
     RECT  39.6 11.941 42.36 12.515 ;
     RECT  26.448 10.259 26.52 12.563 ;
     RECT  28.608 11.459 32.184 12.563 ;
     RECT  38.016 12.467 38.04 12.563 ;
     RECT  42.336 12.515 42.36 12.563 ;
     RECT  45.6 10.885 46.248 12.565 ;
     RECT  31.344 12.563 32.184 13.045 ;
     RECT  28.608 12.563 29.712 13.139 ;
     RECT  34.8 9.973 36.264 13.235 ;
     RECT  36.24 13.235 36.264 13.283 ;
     RECT  31.344 13.045 32.952 13.621 ;
     RECT  117.648 10.933 118.92 13.621 ;
     RECT  117.552 13.621 118.92 14.101 ;
     RECT  18.6 10.453 21.048 14.149 ;
     RECT  22.032 9.061 22.056 14.149 ;
     RECT  44.688 12.565 46.248 14.245 ;
     RECT  47.328 11.173 47.352 14.245 ;
     RECT  53.04 13.045 53.064 14.389 ;
     RECT  54.144 11.363 54.168 14.389 ;
     RECT  18.6 14.149 22.056 14.437 ;
     RECT  34.8 13.235 35.112 14.677 ;
     RECT  39.6 12.515 41.064 15.397 ;
     RECT  42.816 15.349 42.84 15.397 ;
     RECT  31.344 13.621 33.096 15.685 ;
     RECT  117.504 14.101 118.92 16.261 ;
     RECT  119.904 11.653 119.928 16.261 ;
     RECT  117.504 16.261 119.928 16.597 ;
     RECT  121.2 2.151 121.512 16.597 ;
     RECT  60.48 16.357 60.504 16.645 ;
     RECT  61.8 10.885 62.808 16.645 ;
     RECT  27.504 13.621 27.528 16.835 ;
     RECT  30.72 15.685 33.096 16.835 ;
     RECT  60.48 16.645 62.808 16.885 ;
     RECT  63.792 16.597 63.816 16.885 ;
     RECT  60.48 16.885 63.816 16.931 ;
     RECT  39.6 15.397 42.84 17.077 ;
     RECT  60.48 16.931 63.288 17.413 ;
     RECT  39.312 17.077 42.84 17.557 ;
     RECT  36.432 13.621 36.456 17.653 ;
     RECT  38.16 14.197 38.184 17.653 ;
     RECT  36.432 17.653 38.184 17.893 ;
     RECT  39.312 17.557 43.08 17.893 ;
     RECT  29.4 13.139 29.712 18.181 ;
     RECT  30.72 16.835 30.744 18.181 ;
     RECT  60.144 17.413 63.288 18.181 ;
     RECT  44.688 14.245 47.352 18.901 ;
     RECT  44.4 18.901 47.352 19.043 ;
     RECT  31.92 16.835 33.096 19.045 ;
     RECT  53.04 14.389 54.168 19.285 ;
     RECT  29.4 18.181 30.744 19.381 ;
     RECT  34.08 14.677 35.112 19.381 ;
     RECT  36.432 17.893 43.08 19.381 ;
     RECT  18.096 14.437 22.056 19.717 ;
     RECT  18.096 19.717 22.824 19.907 ;
     RECT  34.08 19.381 43.704 20.197 ;
     RECT  44.688 19.043 47.352 20.197 ;
     RECT  56.4 2.151 56.712 20.293 ;
     RECT  28.32 19.381 30.744 20.389 ;
     RECT  51 2.151 51.312 20.485 ;
     RECT  52.464 19.285 54.168 20.485 ;
     RECT  26.496 12.563 26.52 20.869 ;
     RECT  27.6 20.389 30.744 20.869 ;
     RECT  24 6.515 24.312 20.917 ;
     RECT  31.824 19.045 33.096 20.917 ;
     RECT  34.08 20.197 47.352 20.917 ;
     RECT  117.504 16.597 121.512 20.965 ;
     RECT  51 20.485 54.168 21.013 ;
     RECT  50.4 21.013 54.168 21.061 ;
     RECT  60.048 18.181 63.288 21.109 ;
     RECT  23.856 20.917 24.312 21.205 ;
     RECT  26.256 20.869 30.744 21.541 ;
     RECT  31.824 20.917 47.352 21.541 ;
     RECT  23.856 21.205 24.792 21.637 ;
     RECT  26.256 21.541 47.352 21.637 ;
     RECT  23.856 21.637 47.448 21.973 ;
     RECT  59.232 21.109 63.288 21.973 ;
     RECT  18.096 19.907 22.392 22.117 ;
     RECT  23.376 21.973 47.448 22.117 ;
     RECT  117.408 20.965 121.512 22.117 ;
     RECT  117.36 22.117 121.512 22.213 ;
     RECT  13.056 8.197 14.184 23.653 ;
     RECT  10.224 24.085 10.248 24.181 ;
     RECT  10.224 24.181 10.824 24.565 ;
     RECT  15.456 7.717 17.016 24.661 ;
     RECT  7.8 2.151 8.112 24.757 ;
     RECT  9.264 24.565 10.824 24.757 ;
     RECT  5.664 9.589 6.264 25.429 ;
     RECT  15.216 24.661 17.016 25.525 ;
     RECT  18.096 22.117 47.448 25.525 ;
     RECT  7.8 24.757 10.824 26.053 ;
     RECT  7.8 26.053 11.352 26.533 ;
     RECT  12.432 23.653 14.184 26.533 ;
     RECT  7.8 26.533 14.184 26.629 ;
     RECT  15.216 25.525 47.448 26.629 ;
     RECT  5.568 25.429 6.264 30.085 ;
     RECT  7.8 26.629 47.448 30.085 ;
     RECT  117.312 22.213 121.512 30.947 ;
     RECT  117.312 30.947 119.832 31.907 ;
     RECT  117.312 31.907 119.256 32.867 ;
     RECT  119.184 32.867 119.256 33.059 ;
     RECT  117.312 32.867 118.104 33.107 ;
     RECT  119.184 33.059 119.208 33.155 ;
     RECT  118.08 33.107 118.104 33.539 ;
     RECT  5.568 30.085 47.448 34.645 ;
     RECT  5.52 34.645 47.448 39.349 ;
     RECT  4.608 39.349 47.448 43.235 ;
     RECT  5.52 43.235 47.448 63.827 ;
     RECT  56.4 20.293 57.048 64.211 ;
     RECT  5.52 63.827 47.4 65.027 ;
     RECT  27.264 65.027 47.4 66.083 ;
     RECT  27.264 66.083 46.2 67.283 ;
     RECT  5.52 65.027 26.28 67.619 ;
     RECT  49.584 21.061 54.168 67.715 ;
     RECT  5.568 67.619 26.28 68.195 ;
     RECT  5.616 68.195 26.28 69.011 ;
     RECT  47.328 66.083 47.4 69.491 ;
     RECT  41.616 67.283 46.2 70.115 ;
     RECT  49.584 67.715 53.4 71.221 ;
     RECT  49.584 71.221 54.36 71.557 ;
     RECT  67.2 2.151 67.512 71.605 ;
     RECT  49.584 71.557 54.744 71.699 ;
     RECT  47.376 69.491 47.4 72.035 ;
     RECT  56.4 64.211 56.712 72.133 ;
     RECT  49.584 71.699 54.36 72.419 ;
     RECT  59.232 21.973 63.864 72.661 ;
     RECT  58.704 72.661 63.864 72.851 ;
     RECT  41.616 70.115 46.008 72.947 ;
     RECT  49.584 72.419 53.4 73.333 ;
     RECT  49.008 73.333 53.4 73.475 ;
     RECT  55.776 72.133 56.712 73.477 ;
     RECT  58.944 72.851 63.864 73.477 ;
     RECT  68.832 71.749 68.856 73.571 ;
     RECT  58.944 73.477 64.68 73.765 ;
     RECT  65.808 72.325 65.832 73.765 ;
     RECT  67.2 71.605 67.608 73.957 ;
     RECT  58.944 73.765 65.832 74.053 ;
     RECT  54.96 73.477 56.712 74.099 ;
     RECT  49.584 73.475 53.4 74.533 ;
     RECT  43.632 72.947 46.008 74.627 ;
     RECT  70.704 16.789 70.728 74.629 ;
     RECT  49.008 74.533 53.4 74.675 ;
     RECT  56.4 74.099 56.712 74.677 ;
     RECT  54.96 74.099 54.984 75.253 ;
     RECT  56.4 74.677 57.672 75.253 ;
     RECT  5.616 69.011 24.312 75.299 ;
     RECT  69.792 74.629 70.728 75.395 ;
     RECT  25.632 69.011 26.28 75.635 ;
     RECT  58.944 74.053 65.976 75.875 ;
     RECT  5.616 75.299 22.2 76.019 ;
     RECT  5.616 76.019 17.064 76.259 ;
     RECT  65.952 75.875 65.976 76.357 ;
     RECT  67.2 73.957 68.136 76.357 ;
     RECT  10.752 76.259 17.064 76.547 ;
     RECT  18.048 76.019 22.2 76.595 ;
     RECT  45.024 74.627 46.008 76.787 ;
     RECT  10.752 76.547 15 76.835 ;
     RECT  54.96 75.253 57.672 76.885 ;
     RECT  58.944 75.875 64.872 76.885 ;
     RECT  49.584 74.675 53.4 76.979 ;
     RECT  54.96 76.885 64.872 76.979 ;
     RECT  65.952 76.357 68.136 76.979 ;
     RECT  5.616 76.259 9.624 77.171 ;
     RECT  5.616 77.171 8.376 77.459 ;
     RECT  65.952 76.979 67.656 77.509 ;
     RECT  10.752 76.835 14.76 77.555 ;
     RECT  16.08 76.547 17.064 77.603 ;
     RECT  25.632 75.635 26.232 77.605 ;
     RECT  27.264 67.283 40.512 77.605 ;
     RECT  49.584 76.979 51.48 77.605 ;
     RECT  6.048 77.459 8.376 77.699 ;
     RECT  49.008 77.605 51.48 77.699 ;
     RECT  49.008 77.699 51.312 77.747 ;
     RECT  18.048 76.595 21.144 77.795 ;
     RECT  16.224 77.603 17.064 77.891 ;
     RECT  55.104 76.979 64.872 77.893 ;
     RECT  9.6 77.171 9.624 77.939 ;
     RECT  55.104 77.893 64.92 78.037 ;
     RECT  65.904 77.509 67.656 78.037 ;
     RECT  10.752 77.555 13.512 78.131 ;
     RECT  11.232 78.131 13.512 78.179 ;
     RECT  18.048 77.795 18.912 78.179 ;
     RECT  22.176 76.595 22.2 78.181 ;
     RECT  23.376 75.299 24.312 78.181 ;
     RECT  52.464 76.979 53.4 78.373 ;
     RECT  18.096 78.179 18.912 78.419 ;
     RECT  22.176 78.181 24.312 78.419 ;
     RECT  25.632 77.605 40.512 78.515 ;
     RECT  52.464 78.373 53.544 78.565 ;
     RECT  52.464 78.565 53.976 78.613 ;
     RECT  55.104 78.037 67.656 78.613 ;
     RECT  52.464 78.613 67.656 78.661 ;
     RECT  20.112 77.795 21.144 78.707 ;
     RECT  25.632 78.515 26.232 78.707 ;
     RECT  14.736 77.555 14.76 78.803 ;
     RECT  45.024 76.787 45.912 78.947 ;
     RECT  70.704 75.395 70.728 79.187 ;
     RECT  52.464 78.661 68.328 79.237 ;
     RECT  23.376 78.419 24.312 79.283 ;
     RECT  41.616 72.947 42.264 79.283 ;
     RECT  11.232 78.179 11.976 79.571 ;
     RECT  52.464 79.237 68.856 79.813 ;
     RECT  43.632 74.627 43.656 79.859 ;
     RECT  22.176 78.419 22.2 79.907 ;
     RECT  49.584 77.747 51.312 80.341 ;
     RECT  52.464 79.813 69.432 80.341 ;
     RECT  49.584 80.341 69.432 80.389 ;
     RECT  23.616 79.283 24.312 80.435 ;
     RECT  41.616 79.283 42.216 80.435 ;
     RECT  6.048 77.699 8.112 80.627 ;
     RECT  23.904 80.435 24.312 80.675 ;
     RECT  21.072 78.707 21.144 80.819 ;
     RECT  13.008 78.179 13.512 81.107 ;
     RECT  11.952 79.571 11.976 81.203 ;
     RECT  18.432 78.419 18.912 81.635 ;
     RECT  27.264 78.515 40.512 81.683 ;
     RECT  49.584 80.389 69.48 81.923 ;
     RECT  26.208 78.707 26.232 82.115 ;
     RECT  42 80.435 42.216 82.115 ;
     RECT  50.4 81.923 69.48 82.115 ;
     RECT  16.224 77.891 16.536 82.451 ;
     RECT  50.4 82.115 68.664 82.451 ;
     RECT  42.192 82.115 42.216 82.643 ;
     RECT  16.416 82.451 16.536 82.739 ;
     RECT  21.072 80.819 21.096 82.787 ;
     RECT  27.408 81.683 40.512 83.173 ;
     RECT  51 82.451 68.664 83.363 ;
     RECT  24 80.675 24.312 83.509 ;
     RECT  6.048 80.627 6.792 83.651 ;
     RECT  52.656 83.363 68.664 83.701 ;
     RECT  69.792 83.605 69.816 83.701 ;
     RECT  42.672 83.749 42.696 83.797 ;
     RECT  16.512 82.739 16.536 83.843 ;
     RECT  6.768 83.651 6.792 84.083 ;
     RECT  42.096 83.797 42.696 84.229 ;
     RECT  2.4 2.151 2.712 84.249 ;
     RECT  7.8 80.627 8.112 84.249 ;
     RECT  13.2 81.107 13.512 84.249 ;
     RECT  18.6 81.635 18.912 84.249 ;
     RECT  45.6 78.947 45.912 84.249 ;
     RECT  72.6 2.151 72.912 84.249 ;
     RECT  78 2.151 78.312 84.249 ;
     RECT  83.4 2.151 83.712 84.249 ;
     RECT  88.8 2.151 89.112 84.249 ;
     RECT  94.2 2.151 94.512 84.249 ;
     RECT  99.6 2.151 99.912 84.249 ;
     RECT  105 2.151 105.312 84.249 ;
     RECT  110.4 2.151 110.712 84.249 ;
     RECT  115.8 2.151 116.112 84.249 ;
     RECT  121.2 30.947 121.512 84.249 ;
     RECT  126.6 2.151 126.912 84.249 ;
     RECT  132 2.151 132.312 84.249 ;
     RECT  137.4 2.151 137.712 84.249 ;
     RECT  2.4 84.249 2.52 84.263 ;
     RECT  7.8 84.249 7.92 84.263 ;
     RECT  13.2 84.249 13.32 84.263 ;
     RECT  18.6 84.249 18.72 84.263 ;
     RECT  24 83.509 24.984 84.263 ;
     RECT  45.6 84.249 45.72 84.263 ;
     RECT  51 83.363 51.312 84.263 ;
     RECT  72.6 84.249 72.72 84.263 ;
     RECT  78 84.249 78.12 84.263 ;
     RECT  83.4 84.249 83.52 84.263 ;
     RECT  88.8 84.249 88.92 84.263 ;
     RECT  94.2 84.249 94.32 84.263 ;
     RECT  99.6 84.249 99.72 84.263 ;
     RECT  105 84.249 105.12 84.263 ;
     RECT  110.4 84.249 110.52 84.263 ;
     RECT  115.8 84.249 115.92 84.263 ;
     RECT  121.2 84.249 121.32 84.263 ;
     RECT  126.6 84.249 126.72 84.263 ;
     RECT  132 84.249 132.12 84.263 ;
     RECT  137.4 84.249 137.52 84.263 ;
     RECT  26.544 83.173 40.968 84.325 ;
     RECT  24.528 84.263 24.984 84.373 ;
     RECT  25.968 84.325 40.968 84.373 ;
     RECT  42.096 84.229 42.84 84.373 ;
     RECT  52.656 83.701 69.816 84.949 ;
     RECT  51.312 84.949 69.816 85.091 ;
     RECT  24.528 84.373 42.84 86.224 ;
     RECT  51.504 85.091 69.816 86.224 ;
     RECT  24.528 0.611 24.672 2.137 ;
     RECT  42.12 2.915 42.36 3.925 ;
     RECT  24.312 2.963 25.536 4.547 ;
     RECT  24.312 4.547 26.256 5.653 ;
     RECT  36.216 5.171 37.248 5.699 ;
     RECT  24.792 5.653 26.256 6.181 ;
     RECT  36.216 5.699 37.344 9.155 ;
     RECT  38.04 5.699 39.168 8.579 ;
     RECT  24.792 6.181 26.208 6.515 ;
     RECT  30.552 6.275 31.584 7.957 ;
     RECT  24.312 6.515 26.208 7.381 ;
     RECT  26.616 6.803 27.792 6.851 ;
     RECT  26.616 6.851 27.888 8.579 ;
     RECT  24.312 7.381 25.632 9.155 ;
     RECT  18.912 7.477 20.256 10.021 ;
     RECT  14.088 7.909 15.456 8.197 ;
     RECT  14.184 8.197 15.456 24.661 ;
     RECT  32.232 8.531 33.264 8.579 ;
     RECT  26.616 8.579 28.08 8.819 ;
     RECT  32.232 8.579 33.552 8.627 ;
     RECT  39.696 8.579 39.744 9.925 ;
     RECT  40.68 8.579 41.856 10.691 ;
     RECT  20.568 9.061 22.032 10.453 ;
     RECT  36.216 9.155 36.264 9.973 ;
     RECT  18.912 10.021 20.208 10.405 ;
     RECT  21.048 10.453 22.032 14.149 ;
     RECT  40.512 10.691 41.856 11.269 ;
     RECT  38.04 10.837 39.552 11.795 ;
     RECT  46.248 11.173 47.328 14.245 ;
     RECT  40.512 11.269 41.568 11.941 ;
     RECT  118.92 11.653 119.904 16.261 ;
     RECT  119.928 11.653 121.2 16.597 ;
     RECT  41.064 12.515 42.336 12.563 ;
     RECT  53.064 13.045 54.144 14.389 ;
     RECT  35.112 13.235 36.24 13.283 ;
     RECT  35.112 13.283 36.264 13.621 ;
     RECT  26.52 13.621 27.504 16.835 ;
     RECT  35.112 13.621 36.432 19.381 ;
     RECT  116.112 13.621 117.552 14.101 ;
     RECT  116.112 14.101 117.504 20.965 ;
     RECT  38.184 14.197 39.6 17.077 ;
     RECT  17.016 14.437 18.096 25.525 ;
     RECT  33.096 14.677 34.08 20.917 ;
     RECT  29.712 15.685 30.72 18.181 ;
     RECT  60.504 16.357 61.8 16.645 ;
     RECT  62.808 16.597 63.792 16.885 ;
     RECT  30.744 16.835 31.92 19.045 ;
     RECT  38.184 17.077 39.312 17.893 ;
     RECT  43.08 18.901 44.4 19.043 ;
     RECT  43.08 19.043 44.688 19.381 ;
     RECT  30.744 19.045 31.824 21.541 ;
     RECT  51.312 19.285 52.464 20.485 ;
     RECT  43.704 19.381 44.688 20.197 ;
     RECT  22.824 19.717 24 19.907 ;
     RECT  22.392 19.907 24 20.917 ;
     RECT  26.52 20.389 27.6 20.869 ;
     RECT  22.392 20.917 23.856 21.973 ;
     RECT  116.112 20.965 117.408 22.117 ;
     RECT  24.792 21.205 26.256 21.637 ;
     RECT  22.392 21.973 23.376 22.117 ;
     RECT  116.112 22.117 117.36 22.213 ;
     RECT  116.112 22.213 117.312 33.107 ;
     RECT  8.112 24.565 9.264 24.757 ;
     RECT  14.184 24.661 15.216 26.629 ;
     RECT  11.352 26.053 12.432 26.533 ;
     RECT  119.832 30.947 121.2 31.907 ;
     RECT  118.104 32.867 119.184 33.155 ;
     RECT  26.28 65.027 27.264 75.635 ;
     RECT  46.2 66.083 47.328 69.491 ;
     RECT  40.512 67.283 41.616 80.435 ;
     RECT  24.312 69.011 25.632 78.707 ;
     RECT  46.2 69.491 47.376 70.115 ;
     RECT  46.008 70.115 47.376 72.035 ;
     RECT  54.36 71.699 54.744 72.133 ;
     RECT  67.608 71.749 68.832 73.571 ;
     RECT  54.36 72.133 55.776 72.419 ;
     RECT  65.832 72.325 67.2 74.053 ;
     RECT  54.96 72.419 55.776 73.477 ;
     RECT  42.264 72.947 43.632 79.283 ;
     RECT  49.008 73.475 49.584 74.533 ;
     RECT  64.68 73.477 65.808 73.765 ;
     RECT  67.608 73.571 68.136 73.957 ;
     RECT  65.976 74.053 67.2 76.357 ;
     RECT  54.984 74.099 56.4 75.253 ;
     RECT  43.656 74.627 45.024 78.947 ;
     RECT  57.672 74.677 58.944 76.885 ;
     RECT  22.2 75.299 23.376 78.181 ;
     RECT  26.232 75.635 27.264 77.605 ;
     RECT  64.872 75.875 65.952 77.509 ;
     RECT  17.064 76.019 18.048 77.891 ;
     RECT  9.624 76.259 10.752 77.939 ;
     RECT  15 76.547 16.08 76.835 ;
     RECT  21.144 76.595 22.176 79.907 ;
     RECT  14.76 76.835 16.08 77.603 ;
     RECT  51.48 76.979 52.464 77.699 ;
     RECT  8.376 77.171 9.6 77.699 ;
     RECT  64.872 77.509 65.904 77.893 ;
     RECT  13.512 77.555 14.736 78.803 ;
     RECT  14.76 77.603 16.224 78.803 ;
     RECT  8.112 77.699 9.6 77.939 ;
     RECT  51.312 77.699 52.464 80.341 ;
     RECT  18.912 77.795 20.112 78.707 ;
     RECT  16.536 77.891 18.048 78.179 ;
     RECT  64.92 77.893 65.904 78.037 ;
     RECT  11.976 78.179 13.008 81.107 ;
     RECT  22.2 78.419 23.376 79.283 ;
     RECT  26.232 78.515 27.264 81.683 ;
     RECT  53.976 78.565 55.104 78.613 ;
     RECT  22.2 79.283 23.616 79.907 ;
     RECT  42.216 79.283 43.632 79.859 ;
     RECT  40.512 80.435 42 82.115 ;
     RECT  6.792 80.627 7.8 84.083 ;
     RECT  11.976 81.107 13.2 81.203 ;
     RECT  26.232 81.683 27.408 82.115 ;
     RECT  26.544 82.115 27.408 83.173 ;
     RECT  40.512 82.115 42.192 82.643 ;
     RECT  68.664 82.115 69.48 83.605 ;
     RECT  40.512 82.643 42.216 83.173 ;
     RECT  40.968 83.173 42.216 83.749 ;
     RECT  51.312 83.363 52.656 84.949 ;
     RECT  68.664 83.605 69.792 83.701 ;
     RECT  40.968 83.749 42.672 83.797 ;
     RECT  40.968 83.797 42.096 84.373 ;
     RECT  24.984 84.325 25.968 84.373 ;
  END
END ot_s81_pq_aq_mem_native
END LIBRARY
